VERSION 5.7 ;
  NOWIREEXTENSIONATPIN ON ;
  DIVIDERCHAR "/" ;
  BUSBITCHARS "[]" ;
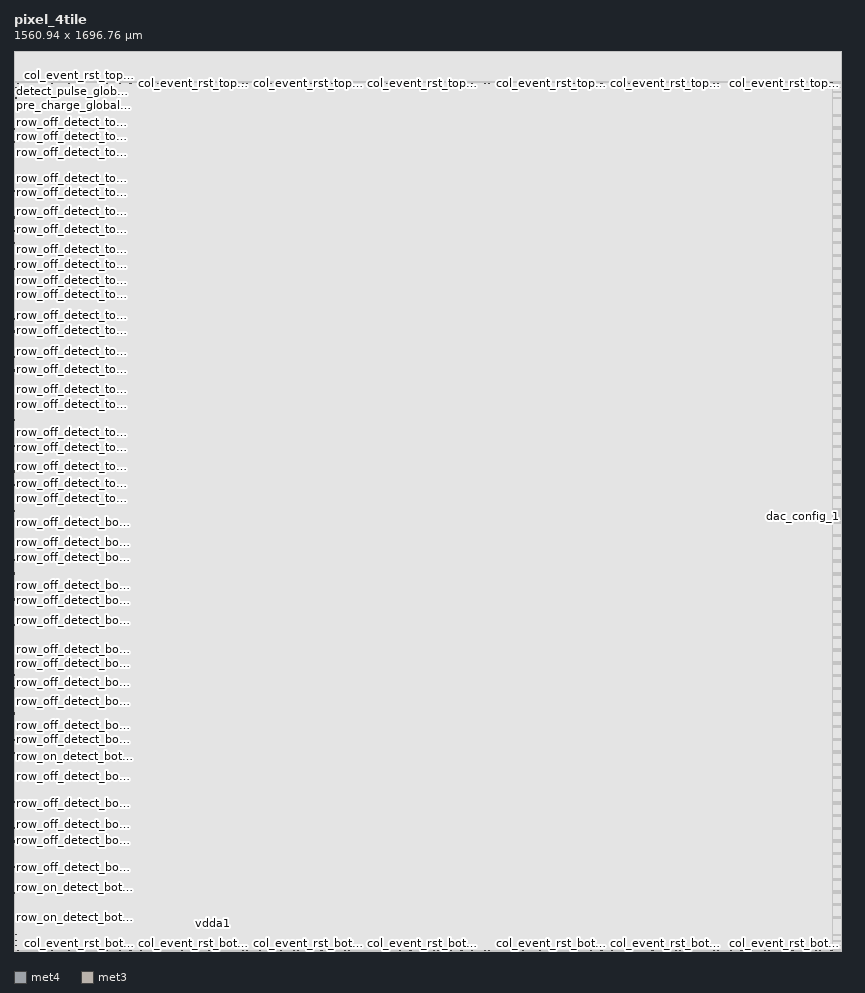
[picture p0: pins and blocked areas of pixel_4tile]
MACRO pixel_4tile
  CLASS BLOCK ;
  FOREIGN pixel_4tile ;
  ORIGIN 0.940 0.005 ;
  SIZE 1560.940 BY 1696.755 ;
  PIN vdda1
    ANTENNADIFFAREA 37975.105469 ;
    PORT
      LAYER met4 ;
        RECT 368.795 50.390 380.585 52.050 ;
    END
  END vdda1
  PIN array_col_top_right<8>
    ANTENNADIFFAREA 0.870000 ;
    PORT
      LAYER met3 ;
        RECT 1438.365 1635.345 1439.135 1635.645 ;
    END
  END array_col_top_right<8>
  PIN array_col_top_right<9>
    ANTENNADIFFAREA 0.870000 ;
    PORT
      LAYER met3 ;
        RECT 1422.245 1635.345 1423.015 1635.645 ;
    END
  END array_col_top_right<9>
  PIN array_col_top_right<12>
    ANTENNADIFFAREA 0.870000 ;
    PORT
      LAYER met3 ;
        RECT 1390.365 1635.345 1391.135 1635.645 ;
    END
  END array_col_top_right<12>
  PIN array_col_top_right<13>
    ANTENNADIFFAREA 0.870000 ;
    PORT
      LAYER met3 ;
        RECT 1374.245 1635.345 1375.015 1635.645 ;
    END
  END array_col_top_right<13>
  PIN array_col_top_right<16>
    ANTENNADIFFAREA 0.870000 ;
    PORT
      LAYER met3 ;
        RECT 1342.365 1635.345 1343.135 1635.645 ;
    END
  END array_col_top_right<16>
  PIN row_off_detect_bot<21>
    ANTENNAGATEAREA 8.064000 ;
    PORT
      LAYER met3 ;
        RECT 0.000 565.610 0.300 565.910 ;
    END
  END row_off_detect_bot<21>
  PIN array_col_top_right<26>
    ANTENNADIFFAREA 0.870000 ;
    PORT
      LAYER met3 ;
        RECT 1222.365 1635.345 1223.135 1635.645 ;
    END
  END array_col_top_right<26>
  PIN row_off_detect_bot<22>
    ANTENNAGATEAREA 8.064000 ;
    PORT
      LAYER met3 ;
        RECT 0.000 544.530 0.300 544.830 ;
    END
  END row_off_detect_bot<22>
  PIN detect_pulse_global_bot_left
    ANTENNAGATEAREA 147.199997 ;
    PORT
      LAYER met3 ;
        RECT 2.740 18.920 3.040 19.220 ;
    END
  END detect_pulse_global_bot_left
  PIN row_on_detect_bot<5>
    ANTENNAGATEAREA 16.128000 ;
    PORT
      LAYER met3 ;
        RECT 0.000 758.730 0.300 759.030 ;
    END
  END row_on_detect_bot<5>
  PIN row_off_detect_top<12>
    ANTENNAGATEAREA 8.064000 ;
    PORT
      LAYER met3 ;
        RECT 0.000 1432.610 0.300 1432.910 ;
    END
  END row_off_detect_top<12>
  PIN row_on_detect_top<13>
    ANTENNAGATEAREA 16.128000 ;
    PORT
      LAYER met3 ;
        RECT 0.000 1430.570 0.300 1430.870 ;
    END
  END row_on_detect_top<13>
  PIN detect_pulse_global_top_left
    ANTENNAGATEAREA 147.199997 ;
    PORT
      LAYER met3 ;
        RECT 2.740 1619.640 3.040 1619.940 ;
    END
  END detect_pulse_global_top_left
  PIN row_on_detect_top<1>
    ANTENNAGATEAREA 16.128000 ;
    PORT
      LAYER met3 ;
        RECT 0.000 1574.730 0.300 1575.030 ;
    END
  END row_on_detect_top<1>
  PIN col_event_rst_top_right<40>
    ANTENNAGATEAREA 4.032000 ;
    PORT
      LAYER met3 ;
        RECT 1057.595 1635.225 1057.895 1635.525 ;
    END
  END col_event_rst_top_right<40>
  PIN col_event_rst_top_right<39>
    ANTENNAGATEAREA 4.032000 ;
    PORT
      LAYER met3 ;
        RECT 1059.500 1635.225 1059.800 1635.525 ;
    END
  END col_event_rst_top_right<39>
  PIN col_event_rst_top_right<38>
    ANTENNAGATEAREA 4.032000 ;
    PORT
      LAYER met3 ;
        RECT 1081.595 1635.225 1081.895 1635.525 ;
    END
  END col_event_rst_top_right<38>
  PIN col_event_rst_top_right<37>
    ANTENNAGATEAREA 4.032000 ;
    PORT
      LAYER met3 ;
        RECT 1083.500 1635.225 1083.800 1635.525 ;
    END
  END col_event_rst_top_right<37>
  PIN col_event_rst_top_right<36>
    ANTENNAGATEAREA 4.032000 ;
    PORT
      LAYER met3 ;
        RECT 1105.595 1635.225 1105.895 1635.525 ;
    END
  END col_event_rst_top_right<36>
  PIN col_event_rst_top_right<35>
    ANTENNAGATEAREA 4.032000 ;
    PORT
      LAYER met3 ;
        RECT 1107.500 1635.225 1107.800 1635.525 ;
    END
  END col_event_rst_top_right<35>
  PIN col_event_rst_top_right<34>
    ANTENNAGATEAREA 4.032000 ;
    PORT
      LAYER met3 ;
        RECT 1129.595 1635.225 1129.895 1635.525 ;
    END
  END col_event_rst_top_right<34>
  PIN col_event_rst_top_right<33>
    ANTENNAGATEAREA 4.032000 ;
    PORT
      LAYER met3 ;
        RECT 1131.500 1635.225 1131.800 1635.525 ;
    END
  END col_event_rst_top_right<33>
  PIN col_event_rst_top_right<27>
    ANTENNAGATEAREA 4.032000 ;
    PORT
      LAYER met3 ;
        RECT 1203.500 1635.225 1203.800 1635.525 ;
    END
  END col_event_rst_top_right<27>
  PIN col_event_rst_top_right<32>
    ANTENNAGATEAREA 4.032000 ;
    PORT
      LAYER met3 ;
        RECT 1153.595 1635.225 1153.895 1635.525 ;
    END
  END col_event_rst_top_right<32>
  PIN col_event_rst_top_right<26>
    ANTENNAGATEAREA 4.032000 ;
    PORT
      LAYER met3 ;
        RECT 1225.595 1635.225 1225.895 1635.525 ;
    END
  END col_event_rst_top_right<26>
  PIN col_event_rst_top_right<25>
    ANTENNAGATEAREA 4.032000 ;
    PORT
      LAYER met3 ;
        RECT 1227.500 1635.225 1227.800 1635.525 ;
    END
  END col_event_rst_top_right<25>
  PIN col_event_rst_top_right<24>
    ANTENNAGATEAREA 4.032000 ;
    PORT
      LAYER met3 ;
        RECT 1249.595 1635.225 1249.895 1635.525 ;
    END
  END col_event_rst_top_right<24>
  PIN col_event_rst_top_right<23>
    ANTENNAGATEAREA 4.032000 ;
    PORT
      LAYER met3 ;
        RECT 1251.500 1635.225 1251.800 1635.525 ;
    END
  END col_event_rst_top_right<23>
  PIN col_event_rst_top_right<22>
    ANTENNAGATEAREA 4.032000 ;
    PORT
      LAYER met3 ;
        RECT 1273.595 1635.225 1273.895 1635.525 ;
    END
  END col_event_rst_top_right<22>
  PIN col_event_rst_top_right<21>
    ANTENNAGATEAREA 4.032000 ;
    PORT
      LAYER met3 ;
        RECT 1275.500 1635.225 1275.800 1635.525 ;
    END
  END col_event_rst_top_right<21>
  PIN col_event_rst_top_right<20>
    ANTENNAGATEAREA 4.032000 ;
    PORT
      LAYER met3 ;
        RECT 1297.595 1635.225 1297.895 1635.525 ;
    END
  END col_event_rst_top_right<20>
  PIN col_event_rst_top_right<19>
    ANTENNAGATEAREA 4.032000 ;
    PORT
      LAYER met3 ;
        RECT 1299.500 1635.225 1299.800 1635.525 ;
    END
  END col_event_rst_top_right<19>
  PIN col_event_rst_top_right<18>
    ANTENNAGATEAREA 4.032000 ;
    PORT
      LAYER met3 ;
        RECT 1321.595 1635.225 1321.895 1635.525 ;
    END
  END col_event_rst_top_right<18>
  PIN col_event_rst_top_right<17>
    ANTENNAGATEAREA 4.032000 ;
    PORT
      LAYER met3 ;
        RECT 1323.500 1635.225 1323.800 1635.525 ;
    END
  END col_event_rst_top_right<17>
  PIN col_event_rst_top_right<16>
    ANTENNAGATEAREA 4.032000 ;
    PORT
      LAYER met3 ;
        RECT 1345.595 1635.225 1345.895 1635.525 ;
    END
  END col_event_rst_top_right<16>
  PIN col_event_rst_top_right<15>
    ANTENNAGATEAREA 4.032000 ;
    PORT
      LAYER met3 ;
        RECT 1347.500 1635.225 1347.800 1635.525 ;
    END
  END col_event_rst_top_right<15>
  PIN col_event_rst_top_right<14>
    ANTENNAGATEAREA 4.032000 ;
    PORT
      LAYER met3 ;
        RECT 1369.595 1635.225 1369.895 1635.525 ;
    END
  END col_event_rst_top_right<14>
  PIN col_event_rst_top_right<13>
    ANTENNAGATEAREA 4.032000 ;
    PORT
      LAYER met3 ;
        RECT 1371.500 1635.225 1371.800 1635.525 ;
    END
  END col_event_rst_top_right<13>
  PIN col_event_rst_top_right<12>
    ANTENNAGATEAREA 4.032000 ;
    PORT
      LAYER met3 ;
        RECT 1393.595 1635.225 1393.895 1635.525 ;
    END
  END col_event_rst_top_right<12>
  PIN col_event_rst_top_right<11>
    ANTENNAGATEAREA 4.032000 ;
    PORT
      LAYER met3 ;
        RECT 1395.500 1635.225 1395.800 1635.525 ;
    END
  END col_event_rst_top_right<11>
  PIN col_event_rst_top_right<10>
    ANTENNAGATEAREA 4.032000 ;
    PORT
      LAYER met3 ;
        RECT 1417.595 1635.225 1417.895 1635.525 ;
    END
  END col_event_rst_top_right<10>
  PIN col_event_rst_top_right<9>
    ANTENNAGATEAREA 4.032000 ;
    PORT
      LAYER met3 ;
        RECT 1419.500 1635.225 1419.800 1635.525 ;
    END
  END col_event_rst_top_right<9>
  PIN col_event_rst_top_right<8>
    ANTENNAGATEAREA 4.032000 ;
    PORT
      LAYER met3 ;
        RECT 1441.595 1635.225 1441.895 1635.525 ;
    END
  END col_event_rst_top_right<8>
  PIN col_event_rst_top_right<7>
    ANTENNAGATEAREA 4.032000 ;
    PORT
      LAYER met3 ;
        RECT 1443.500 1635.225 1443.800 1635.525 ;
    END
  END col_event_rst_top_right<7>
  PIN col_event_rst_top_right<6>
    ANTENNAGATEAREA 4.032000 ;
    PORT
      LAYER met3 ;
        RECT 1465.595 1635.225 1465.895 1635.525 ;
    END
  END col_event_rst_top_right<6>
  PIN col_event_rst_top_right<5>
    ANTENNAGATEAREA 4.032000 ;
    PORT
      LAYER met3 ;
        RECT 1467.500 1635.225 1467.800 1635.525 ;
    END
  END col_event_rst_top_right<5>
  PIN col_event_rst_top_right<4>
    ANTENNAGATEAREA 4.032000 ;
    PORT
      LAYER met3 ;
        RECT 1489.595 1635.225 1489.895 1635.525 ;
    END
  END col_event_rst_top_right<4>
  PIN col_event_rst_top_right<3>
    ANTENNAGATEAREA 4.032000 ;
    PORT
      LAYER met3 ;
        RECT 1491.500 1635.225 1491.800 1635.525 ;
    END
  END col_event_rst_top_right<3>
  PIN col_event_rst_top_right<2>
    ANTENNAGATEAREA 4.032000 ;
    PORT
      LAYER met3 ;
        RECT 1513.595 1635.225 1513.895 1635.525 ;
    END
  END col_event_rst_top_right<2>
  PIN col_event_rst_top_right<1>
    ANTENNAGATEAREA 4.032000 ;
    PORT
      LAYER met3 ;
        RECT 1515.500 1635.225 1515.800 1635.525 ;
    END
  END col_event_rst_top_right<1>
  PIN col_event_rst_top_right<0>
    ANTENNAGATEAREA 4.032000 ;
    PORT
      LAYER met3 ;
        RECT 1537.595 1635.225 1537.895 1635.525 ;
    END
  END col_event_rst_top_right<0>
  PIN col_event_rst_bot_right<63>
    ANTENNAGATEAREA 4.032000 ;
    PORT
      LAYER met3 ;
        RECT 771.500 0.245 771.800 0.545 ;
    END
  END col_event_rst_bot_right<63>
  PIN col_event_rst_bot_right<62>
    ANTENNAGATEAREA 4.032000 ;
    PORT
      LAYER met3 ;
        RECT 793.595 1.580 793.895 1.880 ;
    END
  END col_event_rst_bot_right<62>
  PIN col_event_rst_bot_right<61>
    ANTENNAGATEAREA 4.032000 ;
    PORT
      LAYER met3 ;
        RECT 795.500 1.580 795.800 1.880 ;
    END
  END col_event_rst_bot_right<61>
  PIN col_event_rst_bot_right<60>
    ANTENNAGATEAREA 4.032000 ;
    PORT
      LAYER met3 ;
        RECT 817.595 1.580 817.895 1.880 ;
    END
  END col_event_rst_bot_right<60>
  PIN col_event_rst_bot_right<59>
    ANTENNAGATEAREA 4.032000 ;
    PORT
      LAYER met3 ;
        RECT 819.500 1.580 819.800 1.880 ;
    END
  END col_event_rst_bot_right<59>
  PIN col_event_rst_bot_right<58>
    ANTENNAGATEAREA 4.032000 ;
    PORT
      LAYER met3 ;
        RECT 841.595 1.580 841.895 1.880 ;
    END
  END col_event_rst_bot_right<58>
  PIN col_event_rst_bot_right<57>
    ANTENNAGATEAREA 4.032000 ;
    PORT
      LAYER met3 ;
        RECT 843.500 1.580 843.800 1.880 ;
    END
  END col_event_rst_bot_right<57>
  PIN col_event_rst_bot_right<56>
    ANTENNAGATEAREA 4.032000 ;
    PORT
      LAYER met3 ;
        RECT 865.595 1.580 865.895 1.880 ;
    END
  END col_event_rst_bot_right<56>
  PIN col_event_rst_bot_right<55>
    ANTENNAGATEAREA 4.032000 ;
    PORT
      LAYER met3 ;
        RECT 867.500 1.580 867.800 1.880 ;
    END
  END col_event_rst_bot_right<55>
  PIN col_event_rst_bot_right<54>
    ANTENNAGATEAREA 4.032000 ;
    PORT
      LAYER met3 ;
        RECT 889.595 1.580 889.895 1.880 ;
    END
  END col_event_rst_bot_right<54>
  PIN col_event_rst_bot_right<53>
    ANTENNAGATEAREA 4.032000 ;
    PORT
      LAYER met3 ;
        RECT 891.500 1.580 891.800 1.880 ;
    END
  END col_event_rst_bot_right<53>
  PIN col_event_rst_bot_right<52>
    ANTENNAGATEAREA 4.032000 ;
    PORT
      LAYER met3 ;
        RECT 913.595 1.580 913.895 1.880 ;
    END
  END col_event_rst_bot_right<52>
  PIN col_event_rst_bot_right<51>
    ANTENNAGATEAREA 4.032000 ;
    PORT
      LAYER met3 ;
        RECT 915.500 1.580 915.800 1.880 ;
    END
  END col_event_rst_bot_right<51>
  PIN col_event_rst_bot_right<50>
    ANTENNAGATEAREA 4.032000 ;
    PORT
      LAYER met3 ;
        RECT 937.595 1.580 937.895 1.880 ;
    END
  END col_event_rst_bot_right<50>
  PIN col_event_rst_bot_right<49>
    ANTENNAGATEAREA 4.032000 ;
    PORT
      LAYER met3 ;
        RECT 939.500 1.580 939.800 1.880 ;
    END
  END col_event_rst_bot_right<49>
  PIN col_event_rst_bot_right<48>
    ANTENNAGATEAREA 4.032000 ;
    PORT
      LAYER met3 ;
        RECT 961.595 1.580 961.895 1.880 ;
    END
  END col_event_rst_bot_right<48>
  PIN col_event_rst_bot_right<47>
    ANTENNAGATEAREA 4.032000 ;
    PORT
      LAYER met3 ;
        RECT 963.500 1.580 963.800 1.880 ;
    END
  END col_event_rst_bot_right<47>
  PIN col_event_rst_bot_right<46>
    ANTENNAGATEAREA 4.032000 ;
    PORT
      LAYER met3 ;
        RECT 985.595 1.580 985.895 1.880 ;
    END
  END col_event_rst_bot_right<46>
  PIN col_event_rst_bot_right<45>
    ANTENNAGATEAREA 4.032000 ;
    PORT
      LAYER met3 ;
        RECT 987.500 1.580 987.800 1.880 ;
    END
  END col_event_rst_bot_right<45>
  PIN col_event_rst_bot_right<44>
    ANTENNAGATEAREA 4.032000 ;
    PORT
      LAYER met3 ;
        RECT 1009.595 1.580 1009.895 1.880 ;
    END
  END col_event_rst_bot_right<44>
  PIN col_event_rst_bot_right<43>
    ANTENNAGATEAREA 4.032000 ;
    PORT
      LAYER met3 ;
        RECT 1011.500 1.580 1011.800 1.880 ;
    END
  END col_event_rst_bot_right<43>
  PIN col_event_rst_bot_right<42>
    ANTENNAGATEAREA 4.032000 ;
    PORT
      LAYER met3 ;
        RECT 1033.595 1.580 1033.895 1.880 ;
    END
  END col_event_rst_bot_right<42>
  PIN col_event_rst_bot_right<41>
    ANTENNAGATEAREA 4.032000 ;
    PORT
      LAYER met3 ;
        RECT 1035.500 1.580 1035.800 1.880 ;
    END
  END col_event_rst_bot_right<41>
  PIN col_event_rst_bot_right<40>
    ANTENNAGATEAREA 4.032000 ;
    PORT
      LAYER met3 ;
        RECT 1057.595 1.580 1057.895 1.880 ;
    END
  END col_event_rst_bot_right<40>
  PIN col_event_rst_bot_right<39>
    ANTENNAGATEAREA 4.032000 ;
    PORT
      LAYER met3 ;
        RECT 1059.500 1.580 1059.800 1.880 ;
    END
  END col_event_rst_bot_right<39>
  PIN col_event_rst_bot_right<38>
    ANTENNAGATEAREA 4.032000 ;
    PORT
      LAYER met3 ;
        RECT 1081.595 1.580 1081.895 1.880 ;
    END
  END col_event_rst_bot_right<38>
  PIN col_event_rst_bot_right<37>
    ANTENNAGATEAREA 4.032000 ;
    PORT
      LAYER met3 ;
        RECT 1083.500 1.580 1083.800 1.880 ;
    END
  END col_event_rst_bot_right<37>
  PIN col_event_rst_bot_right<36>
    ANTENNAGATEAREA 4.032000 ;
    PORT
      LAYER met3 ;
        RECT 1105.595 1.580 1105.895 1.880 ;
    END
  END col_event_rst_bot_right<36>
  PIN col_event_rst_bot_right<35>
    ANTENNAGATEAREA 4.032000 ;
    PORT
      LAYER met3 ;
        RECT 1107.500 1.580 1107.800 1.880 ;
    END
  END col_event_rst_bot_right<35>
  PIN col_event_rst_bot_right<34>
    ANTENNAGATEAREA 4.032000 ;
    PORT
      LAYER met3 ;
        RECT 1129.595 1.580 1129.895 1.880 ;
    END
  END col_event_rst_bot_right<34>
  PIN col_event_rst_bot_right<33>
    ANTENNAGATEAREA 4.032000 ;
    PORT
      LAYER met3 ;
        RECT 1131.500 1.580 1131.800 1.880 ;
    END
  END col_event_rst_bot_right<33>
  PIN col_event_rst_bot_right<32>
    ANTENNAGATEAREA 4.032000 ;
    PORT
      LAYER met3 ;
        RECT 1153.595 1.580 1153.895 1.880 ;
    END
  END col_event_rst_bot_right<32>
  PIN col_event_rst_bot_right<31>
    ANTENNAGATEAREA 4.032000 ;
    PORT
      LAYER met3 ;
        RECT 1155.500 1.580 1155.800 1.880 ;
    END
  END col_event_rst_bot_right<31>
  PIN col_event_rst_bot_right<30>
    ANTENNAGATEAREA 4.032000 ;
    PORT
      LAYER met3 ;
        RECT 1177.595 1.580 1177.895 1.880 ;
    END
  END col_event_rst_bot_right<30>
  PIN col_event_rst_bot_right<29>
    ANTENNAGATEAREA 4.032000 ;
    PORT
      LAYER met3 ;
        RECT 1179.500 1.580 1179.800 1.880 ;
    END
  END col_event_rst_bot_right<29>
  PIN col_event_rst_bot_right<28>
    ANTENNAGATEAREA 4.032000 ;
    PORT
      LAYER met3 ;
        RECT 1201.595 1.580 1201.895 1.880 ;
    END
  END col_event_rst_bot_right<28>
  PIN col_event_rst_bot_right<27>
    ANTENNAGATEAREA 4.032000 ;
    PORT
      LAYER met3 ;
        RECT 1203.500 1.580 1203.800 1.880 ;
    END
  END col_event_rst_bot_right<27>
  PIN col_event_rst_bot_right<26>
    ANTENNAGATEAREA 4.032000 ;
    PORT
      LAYER met3 ;
        RECT 1225.595 1.580 1225.895 1.880 ;
    END
  END col_event_rst_bot_right<26>
  PIN col_event_rst_bot_right<25>
    ANTENNAGATEAREA 4.032000 ;
    PORT
      LAYER met3 ;
        RECT 1227.500 1.580 1227.800 1.880 ;
    END
  END col_event_rst_bot_right<25>
  PIN col_event_rst_bot_right<24>
    ANTENNAGATEAREA 4.032000 ;
    PORT
      LAYER met3 ;
        RECT 1249.595 1.580 1249.895 1.880 ;
    END
  END col_event_rst_bot_right<24>
  PIN col_event_rst_bot_right<23>
    ANTENNAGATEAREA 4.032000 ;
    PORT
      LAYER met3 ;
        RECT 1251.500 1.580 1251.800 1.880 ;
    END
  END col_event_rst_bot_right<23>
  PIN col_event_rst_bot_right<22>
    ANTENNAGATEAREA 4.032000 ;
    PORT
      LAYER met3 ;
        RECT 1273.595 1.580 1273.895 1.880 ;
    END
  END col_event_rst_bot_right<22>
  PIN col_event_rst_bot_right<21>
    ANTENNAGATEAREA 4.032000 ;
    PORT
      LAYER met3 ;
        RECT 1275.500 1.580 1275.800 1.880 ;
    END
  END col_event_rst_bot_right<21>
  PIN col_event_rst_bot_right<20>
    ANTENNAGATEAREA 4.032000 ;
    PORT
      LAYER met3 ;
        RECT 1297.595 1.580 1297.895 1.880 ;
    END
  END col_event_rst_bot_right<20>
  PIN col_event_rst_bot_right<19>
    ANTENNAGATEAREA 4.032000 ;
    PORT
      LAYER met3 ;
        RECT 1299.500 1.580 1299.800 1.880 ;
    END
  END col_event_rst_bot_right<19>
  PIN col_event_rst_bot_right<18>
    ANTENNAGATEAREA 4.032000 ;
    PORT
      LAYER met3 ;
        RECT 1321.595 1.580 1321.895 1.880 ;
    END
  END col_event_rst_bot_right<18>
  PIN col_event_rst_bot_right<17>
    ANTENNAGATEAREA 4.032000 ;
    PORT
      LAYER met3 ;
        RECT 1323.500 1.580 1323.800 1.880 ;
    END
  END col_event_rst_bot_right<17>
  PIN col_event_rst_bot_right<16>
    ANTENNAGATEAREA 4.032000 ;
    PORT
      LAYER met3 ;
        RECT 1345.595 1.580 1345.895 1.880 ;
    END
  END col_event_rst_bot_right<16>
  PIN col_event_rst_bot_right<15>
    ANTENNAGATEAREA 4.032000 ;
    PORT
      LAYER met3 ;
        RECT 1347.500 1.580 1347.800 1.880 ;
    END
  END col_event_rst_bot_right<15>
  PIN col_event_rst_bot_right<14>
    ANTENNAGATEAREA 4.032000 ;
    PORT
      LAYER met3 ;
        RECT 1369.595 1.580 1369.895 1.880 ;
    END
  END col_event_rst_bot_right<14>
  PIN col_event_rst_bot_right<13>
    ANTENNAGATEAREA 4.032000 ;
    PORT
      LAYER met3 ;
        RECT 1371.500 1.580 1371.800 1.880 ;
    END
  END col_event_rst_bot_right<13>
  PIN col_event_rst_bot_right<12>
    ANTENNAGATEAREA 4.032000 ;
    PORT
      LAYER met3 ;
        RECT 1393.595 1.580 1393.895 1.880 ;
    END
  END col_event_rst_bot_right<12>
  PIN col_event_rst_bot_right<11>
    ANTENNAGATEAREA 4.032000 ;
    PORT
      LAYER met3 ;
        RECT 1395.500 1.580 1395.800 1.880 ;
    END
  END col_event_rst_bot_right<11>
  PIN col_event_rst_bot_right<10>
    ANTENNAGATEAREA 4.032000 ;
    PORT
      LAYER met3 ;
        RECT 1417.595 1.580 1417.895 1.880 ;
    END
  END col_event_rst_bot_right<10>
  PIN col_event_rst_bot_right<9>
    ANTENNAGATEAREA 4.032000 ;
    PORT
      LAYER met3 ;
        RECT 1419.500 1.580 1419.800 1.880 ;
    END
  END col_event_rst_bot_right<9>
  PIN col_event_rst_bot_right<8>
    ANTENNAGATEAREA 4.032000 ;
    PORT
      LAYER met3 ;
        RECT 1441.595 1.580 1441.895 1.880 ;
    END
  END col_event_rst_bot_right<8>
  PIN col_event_rst_bot_right<7>
    ANTENNAGATEAREA 4.032000 ;
    PORT
      LAYER met3 ;
        RECT 1443.500 1.580 1443.800 1.880 ;
    END
  END col_event_rst_bot_right<7>
  PIN col_event_rst_bot_right<6>
    ANTENNAGATEAREA 4.032000 ;
    PORT
      LAYER met3 ;
        RECT 1465.595 1.580 1465.895 1.880 ;
    END
  END col_event_rst_bot_right<6>
  PIN col_event_rst_bot_right<5>
    ANTENNAGATEAREA 4.032000 ;
    PORT
      LAYER met3 ;
        RECT 1467.500 1.580 1467.800 1.880 ;
    END
  END col_event_rst_bot_right<5>
  PIN col_event_rst_bot_right<4>
    ANTENNAGATEAREA 4.032000 ;
    PORT
      LAYER met3 ;
        RECT 1489.595 1.580 1489.895 1.880 ;
    END
  END col_event_rst_bot_right<4>
  PIN col_event_rst_bot_right<3>
    ANTENNAGATEAREA 4.032000 ;
    PORT
      LAYER met3 ;
        RECT 1491.500 1.580 1491.800 1.880 ;
    END
  END col_event_rst_bot_right<3>
  PIN col_event_rst_bot_right<2>
    ANTENNAGATEAREA 4.032000 ;
    PORT
      LAYER met3 ;
        RECT 1513.595 1.580 1513.895 1.880 ;
    END
  END col_event_rst_bot_right<2>
  PIN col_event_rst_bot_right<1>
    ANTENNAGATEAREA 4.032000 ;
    PORT
      LAYER met3 ;
        RECT 1515.500 1.580 1515.800 1.880 ;
    END
  END col_event_rst_bot_right<1>
  PIN col_event_rst_bot_right<0>
    ANTENNAGATEAREA 4.032000 ;
    PORT
      LAYER met3 ;
        RECT 1537.595 1.580 1537.895 1.880 ;
    END
  END col_event_rst_bot_right<0>
  PIN col_event_rst_bot_left<63>
    ANTENNAGATEAREA 4.032000 ;
    PORT
      LAYER met3 ;
        RECT 3.500 0.245 3.800 0.545 ;
    END
  END col_event_rst_bot_left<63>
  PIN col_event_rst_bot_left<62>
    ANTENNAGATEAREA 4.032000 ;
    PORT
      LAYER met3 ;
        RECT 25.595 1.580 25.895 1.880 ;
    END
  END col_event_rst_bot_left<62>
  PIN col_event_rst_bot_left<61>
    ANTENNAGATEAREA 4.032000 ;
    PORT
      LAYER met3 ;
        RECT 27.500 1.580 27.800 1.880 ;
    END
  END col_event_rst_bot_left<61>
  PIN col_event_rst_bot_left<60>
    ANTENNAGATEAREA 4.032000 ;
    PORT
      LAYER met3 ;
        RECT 49.595 1.580 49.895 1.880 ;
    END
  END col_event_rst_bot_left<60>
  PIN col_event_rst_bot_left<59>
    ANTENNAGATEAREA 4.032000 ;
    PORT
      LAYER met3 ;
        RECT 51.500 1.580 51.800 1.880 ;
    END
  END col_event_rst_bot_left<59>
  PIN col_event_rst_bot_left<58>
    ANTENNAGATEAREA 4.032000 ;
    PORT
      LAYER met3 ;
        RECT 73.595 1.580 73.895 1.880 ;
    END
  END col_event_rst_bot_left<58>
  PIN col_event_rst_bot_left<57>
    ANTENNAGATEAREA 4.032000 ;
    PORT
      LAYER met3 ;
        RECT 75.500 1.580 75.800 1.880 ;
    END
  END col_event_rst_bot_left<57>
  PIN col_event_rst_bot_left<56>
    ANTENNAGATEAREA 4.032000 ;
    PORT
      LAYER met3 ;
        RECT 97.595 1.580 97.895 1.880 ;
    END
  END col_event_rst_bot_left<56>
  PIN col_event_rst_bot_left<55>
    ANTENNAGATEAREA 4.032000 ;
    PORT
      LAYER met3 ;
        RECT 99.500 1.580 99.800 1.880 ;
    END
  END col_event_rst_bot_left<55>
  PIN col_event_rst_bot_left<54>
    ANTENNAGATEAREA 4.032000 ;
    PORT
      LAYER met3 ;
        RECT 121.595 1.580 121.895 1.880 ;
    END
  END col_event_rst_bot_left<54>
  PIN col_event_rst_bot_left<53>
    ANTENNAGATEAREA 4.032000 ;
    PORT
      LAYER met3 ;
        RECT 123.500 1.580 123.800 1.880 ;
    END
  END col_event_rst_bot_left<53>
  PIN col_event_rst_bot_left<52>
    ANTENNAGATEAREA 4.032000 ;
    PORT
      LAYER met3 ;
        RECT 145.595 1.580 145.895 1.880 ;
    END
  END col_event_rst_bot_left<52>
  PIN col_event_rst_bot_left<51>
    ANTENNAGATEAREA 4.032000 ;
    PORT
      LAYER met3 ;
        RECT 147.500 1.580 147.800 1.880 ;
    END
  END col_event_rst_bot_left<51>
  PIN col_event_rst_bot_left<50>
    ANTENNAGATEAREA 4.032000 ;
    PORT
      LAYER met3 ;
        RECT 169.595 1.580 169.895 1.880 ;
    END
  END col_event_rst_bot_left<50>
  PIN col_event_rst_bot_left<49>
    ANTENNAGATEAREA 4.032000 ;
    PORT
      LAYER met3 ;
        RECT 171.500 1.580 171.800 1.880 ;
    END
  END col_event_rst_bot_left<49>
  PIN col_event_rst_bot_left<48>
    ANTENNAGATEAREA 4.032000 ;
    PORT
      LAYER met3 ;
        RECT 193.595 1.580 193.895 1.880 ;
    END
  END col_event_rst_bot_left<48>
  PIN col_event_rst_bot_left<47>
    ANTENNAGATEAREA 4.032000 ;
    PORT
      LAYER met3 ;
        RECT 195.500 1.580 195.800 1.880 ;
    END
  END col_event_rst_bot_left<47>
  PIN col_event_rst_bot_left<46>
    ANTENNAGATEAREA 4.032000 ;
    PORT
      LAYER met3 ;
        RECT 217.595 1.580 217.895 1.880 ;
    END
  END col_event_rst_bot_left<46>
  PIN col_event_rst_bot_left<45>
    ANTENNAGATEAREA 4.032000 ;
    PORT
      LAYER met3 ;
        RECT 219.500 1.580 219.800 1.880 ;
    END
  END col_event_rst_bot_left<45>
  PIN col_event_rst_bot_left<44>
    ANTENNAGATEAREA 4.032000 ;
    PORT
      LAYER met3 ;
        RECT 241.595 1.580 241.895 1.880 ;
    END
  END col_event_rst_bot_left<44>
  PIN col_event_rst_bot_left<43>
    ANTENNAGATEAREA 4.032000 ;
    PORT
      LAYER met3 ;
        RECT 243.500 1.580 243.800 1.880 ;
    END
  END col_event_rst_bot_left<43>
  PIN col_event_rst_bot_left<42>
    ANTENNAGATEAREA 4.032000 ;
    PORT
      LAYER met3 ;
        RECT 265.595 1.580 265.895 1.880 ;
    END
  END col_event_rst_bot_left<42>
  PIN col_event_rst_bot_left<41>
    ANTENNAGATEAREA 4.032000 ;
    PORT
      LAYER met3 ;
        RECT 267.500 1.580 267.800 1.880 ;
    END
  END col_event_rst_bot_left<41>
  PIN col_event_rst_bot_left<40>
    ANTENNAGATEAREA 4.032000 ;
    PORT
      LAYER met3 ;
        RECT 289.595 1.580 289.895 1.880 ;
    END
  END col_event_rst_bot_left<40>
  PIN col_event_rst_bot_left<39>
    ANTENNAGATEAREA 4.032000 ;
    PORT
      LAYER met3 ;
        RECT 291.500 1.580 291.800 1.880 ;
    END
  END col_event_rst_bot_left<39>
  PIN col_event_rst_bot_left<38>
    ANTENNAGATEAREA 4.032000 ;
    PORT
      LAYER met3 ;
        RECT 313.595 1.580 313.895 1.880 ;
    END
  END col_event_rst_bot_left<38>
  PIN col_event_rst_bot_left<37>
    ANTENNAGATEAREA 4.032000 ;
    PORT
      LAYER met3 ;
        RECT 315.500 1.580 315.800 1.880 ;
    END
  END col_event_rst_bot_left<37>
  PIN col_event_rst_bot_left<36>
    ANTENNAGATEAREA 4.032000 ;
    PORT
      LAYER met3 ;
        RECT 337.595 1.580 337.895 1.880 ;
    END
  END col_event_rst_bot_left<36>
  PIN col_event_rst_bot_left<35>
    ANTENNAGATEAREA 4.032000 ;
    PORT
      LAYER met3 ;
        RECT 339.500 1.580 339.800 1.880 ;
    END
  END col_event_rst_bot_left<35>
  PIN col_event_rst_bot_left<34>
    ANTENNAGATEAREA 4.032000 ;
    PORT
      LAYER met3 ;
        RECT 361.595 1.580 361.895 1.880 ;
    END
  END col_event_rst_bot_left<34>
  PIN col_event_rst_bot_left<33>
    ANTENNAGATEAREA 4.032000 ;
    PORT
      LAYER met3 ;
        RECT 363.500 1.580 363.800 1.880 ;
    END
  END col_event_rst_bot_left<33>
  PIN col_event_rst_bot_left<32>
    ANTENNAGATEAREA 4.032000 ;
    PORT
      LAYER met3 ;
        RECT 385.595 1.580 385.895 1.880 ;
    END
  END col_event_rst_bot_left<32>
  PIN col_event_rst_bot_left<31>
    ANTENNAGATEAREA 4.032000 ;
    PORT
      LAYER met3 ;
        RECT 387.500 1.580 387.800 1.880 ;
    END
  END col_event_rst_bot_left<31>
  PIN col_event_rst_bot_left<30>
    ANTENNAGATEAREA 4.032000 ;
    PORT
      LAYER met3 ;
        RECT 409.595 1.580 409.895 1.880 ;
    END
  END col_event_rst_bot_left<30>
  PIN col_event_rst_bot_left<29>
    ANTENNAGATEAREA 4.032000 ;
    PORT
      LAYER met3 ;
        RECT 411.500 1.580 411.800 1.880 ;
    END
  END col_event_rst_bot_left<29>
  PIN col_event_rst_bot_left<28>
    ANTENNAGATEAREA 4.032000 ;
    PORT
      LAYER met3 ;
        RECT 433.595 1.580 433.895 1.880 ;
    END
  END col_event_rst_bot_left<28>
  PIN col_event_rst_bot_left<27>
    ANTENNAGATEAREA 4.032000 ;
    PORT
      LAYER met3 ;
        RECT 435.500 1.580 435.800 1.880 ;
    END
  END col_event_rst_bot_left<27>
  PIN col_event_rst_bot_left<26>
    ANTENNAGATEAREA 4.032000 ;
    PORT
      LAYER met3 ;
        RECT 457.595 1.580 457.895 1.880 ;
    END
  END col_event_rst_bot_left<26>
  PIN col_event_rst_bot_left<25>
    ANTENNAGATEAREA 4.032000 ;
    PORT
      LAYER met3 ;
        RECT 459.500 1.580 459.800 1.880 ;
    END
  END col_event_rst_bot_left<25>
  PIN col_event_rst_bot_left<24>
    ANTENNAGATEAREA 4.032000 ;
    PORT
      LAYER met3 ;
        RECT 481.595 1.580 481.895 1.880 ;
    END
  END col_event_rst_bot_left<24>
  PIN col_event_rst_bot_left<23>
    ANTENNAGATEAREA 4.032000 ;
    PORT
      LAYER met3 ;
        RECT 483.500 1.580 483.800 1.880 ;
    END
  END col_event_rst_bot_left<23>
  PIN col_event_rst_bot_left<22>
    ANTENNAGATEAREA 4.032000 ;
    PORT
      LAYER met3 ;
        RECT 505.595 1.580 505.895 1.880 ;
    END
  END col_event_rst_bot_left<22>
  PIN col_event_rst_bot_left<21>
    ANTENNAGATEAREA 4.032000 ;
    PORT
      LAYER met3 ;
        RECT 507.500 1.580 507.800 1.880 ;
    END
  END col_event_rst_bot_left<21>
  PIN col_event_rst_bot_left<20>
    ANTENNAGATEAREA 4.032000 ;
    PORT
      LAYER met3 ;
        RECT 529.595 1.580 529.895 1.880 ;
    END
  END col_event_rst_bot_left<20>
  PIN col_event_rst_bot_left<19>
    ANTENNAGATEAREA 4.032000 ;
    PORT
      LAYER met3 ;
        RECT 531.500 1.580 531.800 1.880 ;
    END
  END col_event_rst_bot_left<19>
  PIN col_event_rst_bot_left<18>
    ANTENNAGATEAREA 4.032000 ;
    PORT
      LAYER met3 ;
        RECT 553.595 1.580 553.895 1.880 ;
    END
  END col_event_rst_bot_left<18>
  PIN col_event_rst_bot_left<17>
    ANTENNAGATEAREA 4.032000 ;
    PORT
      LAYER met3 ;
        RECT 555.500 1.580 555.800 1.880 ;
    END
  END col_event_rst_bot_left<17>
  PIN col_event_rst_bot_left<16>
    ANTENNAGATEAREA 4.032000 ;
    PORT
      LAYER met3 ;
        RECT 577.595 1.580 577.895 1.880 ;
    END
  END col_event_rst_bot_left<16>
  PIN col_event_rst_bot_left<15>
    ANTENNAGATEAREA 4.032000 ;
    PORT
      LAYER met3 ;
        RECT 579.500 1.580 579.800 1.880 ;
    END
  END col_event_rst_bot_left<15>
  PIN col_event_rst_bot_left<14>
    ANTENNAGATEAREA 4.032000 ;
    PORT
      LAYER met3 ;
        RECT 601.595 1.580 601.895 1.880 ;
    END
  END col_event_rst_bot_left<14>
  PIN col_event_rst_bot_left<13>
    ANTENNAGATEAREA 4.032000 ;
    PORT
      LAYER met3 ;
        RECT 603.500 1.580 603.800 1.880 ;
    END
  END col_event_rst_bot_left<13>
  PIN col_event_rst_bot_left<12>
    ANTENNAGATEAREA 4.032000 ;
    PORT
      LAYER met3 ;
        RECT 625.595 1.580 625.895 1.880 ;
    END
  END col_event_rst_bot_left<12>
  PIN col_event_rst_bot_left<11>
    ANTENNAGATEAREA 4.032000 ;
    PORT
      LAYER met3 ;
        RECT 627.500 1.580 627.800 1.880 ;
    END
  END col_event_rst_bot_left<11>
  PIN col_event_rst_bot_left<10>
    ANTENNAGATEAREA 4.032000 ;
    PORT
      LAYER met3 ;
        RECT 649.595 1.580 649.895 1.880 ;
    END
  END col_event_rst_bot_left<10>
  PIN col_event_rst_bot_left<9>
    ANTENNAGATEAREA 4.032000 ;
    PORT
      LAYER met3 ;
        RECT 651.500 1.580 651.800 1.880 ;
    END
  END col_event_rst_bot_left<9>
  PIN col_event_rst_bot_left<8>
    ANTENNAGATEAREA 4.032000 ;
    PORT
      LAYER met3 ;
        RECT 673.595 1.580 673.895 1.880 ;
    END
  END col_event_rst_bot_left<8>
  PIN col_event_rst_bot_left<7>
    ANTENNAGATEAREA 4.032000 ;
    PORT
      LAYER met3 ;
        RECT 675.500 1.580 675.800 1.880 ;
    END
  END col_event_rst_bot_left<7>
  PIN col_event_rst_bot_left<6>
    ANTENNAGATEAREA 4.032000 ;
    PORT
      LAYER met3 ;
        RECT 697.595 1.580 697.895 1.880 ;
    END
  END col_event_rst_bot_left<6>
  PIN col_event_rst_bot_left<5>
    ANTENNAGATEAREA 4.032000 ;
    PORT
      LAYER met3 ;
        RECT 699.500 1.580 699.800 1.880 ;
    END
  END col_event_rst_bot_left<5>
  PIN col_event_rst_bot_left<4>
    ANTENNAGATEAREA 4.032000 ;
    PORT
      LAYER met3 ;
        RECT 721.595 1.580 721.895 1.880 ;
    END
  END col_event_rst_bot_left<4>
  PIN col_event_rst_bot_left<3>
    ANTENNAGATEAREA 4.032000 ;
    PORT
      LAYER met3 ;
        RECT 723.500 1.580 723.800 1.880 ;
    END
  END col_event_rst_bot_left<3>
  PIN col_event_rst_bot_left<2>
    ANTENNAGATEAREA 4.032000 ;
    PORT
      LAYER met3 ;
        RECT 745.595 1.580 745.895 1.880 ;
    END
  END col_event_rst_bot_left<2>
  PIN col_event_rst_bot_left<1>
    ANTENNAGATEAREA 4.032000 ;
    PORT
      LAYER met3 ;
        RECT 747.500 1.580 747.800 1.880 ;
    END
  END col_event_rst_bot_left<1>
  PIN col_event_rst_bot_left<0>
    ANTENNAGATEAREA 4.032000 ;
    PORT
      LAYER met3 ;
        RECT 769.595 1.580 769.895 1.880 ;
    END
  END col_event_rst_bot_left<0>
  PIN vssa1
    ANTENNADIFFAREA 30668.416016 ;
    PORT
      LAYER met3 ;
        RECT 1539.250 1637.930 1542.950 1638.230 ;
    END
    PORT
      LAYER met3 ;
        RECT 1539.250 0.295 1542.950 0.595 ;
    END
  END vssa1
  PIN array_col_top_left<9>
    ANTENNADIFFAREA 0.870000 ;
    PORT
      LAYER met3 ;
        RECT 654.245 1635.345 655.015 1635.645 ;
    END
  END array_col_top_left<9>
  PIN row_on_detect_top<35>
    ANTENNAGATEAREA 16.128000 ;
    PORT
      LAYER met3 ;
        RECT 0.000 1166.730 0.300 1167.030 ;
    END
  END row_on_detect_top<35>
  PIN row_off_detect_top<34>
    ANTENNAGATEAREA 8.064000 ;
    PORT
      LAYER met3 ;
        RECT 0.000 1168.770 0.300 1169.070 ;
    END
  END row_off_detect_top<34>
  PIN row_off_detect_top<14>
    ANTENNAGATEAREA 8.064000 ;
    PORT
      LAYER met3 ;
        RECT 0.000 1408.810 0.300 1409.110 ;
    END
  END row_off_detect_top<14>
  PIN array_col_top_left<13>
    ANTENNADIFFAREA 0.870000 ;
    PORT
      LAYER met3 ;
        RECT 606.245 1635.345 607.015 1635.645 ;
    END
  END array_col_top_left<13>
  PIN array_col_bot_left<60>
    ANTENNADIFFAREA 0.870000 ;
    PORT
      LAYER met3 ;
        RECT 46.365 1.460 47.135 1.760 ;
    END
  END array_col_bot_left<60>
  PIN array_col_bot_left<55>
    ANTENNADIFFAREA 0.870000 ;
    PORT
      LAYER met3 ;
        RECT 102.245 1.460 103.015 1.760 ;
    END
  END array_col_bot_left<55>
  PIN array_col_top_left<47>
    ANTENNADIFFAREA 0.870000 ;
    PORT
      LAYER met3 ;
        RECT 198.245 1635.345 199.015 1635.645 ;
    END
  END array_col_top_left<47>
  PIN array_col_bot_left<42>
    ANTENNADIFFAREA 0.870000 ;
    PORT
      LAYER met3 ;
        RECT 262.365 1.460 263.135 1.760 ;
    END
  END array_col_bot_left<42>
  PIN array_col_bot_left<41>
    ANTENNADIFFAREA 0.870000 ;
    PORT
      LAYER met3 ;
        RECT 270.245 1.460 271.015 1.760 ;
    END
  END array_col_bot_left<41>
  PIN array_col_top_right<25>
    ANTENNADIFFAREA 0.870000 ;
    PORT
      LAYER met3 ;
        RECT 1230.245 1635.345 1231.015 1635.645 ;
    END
  END array_col_top_right<25>
  PIN array_col_top_right<24>
    ANTENNADIFFAREA 0.870000 ;
    PORT
      LAYER met3 ;
        RECT 1246.365 1635.345 1247.135 1635.645 ;
    END
  END array_col_top_right<24>
  PIN array_col_bot_left<40>
    ANTENNADIFFAREA 0.870000 ;
    PORT
      LAYER met3 ;
        RECT 286.365 1.460 287.135 1.760 ;
    END
  END array_col_bot_left<40>
  PIN array_col_top_right<23>
    ANTENNADIFFAREA 0.870000 ;
    PORT
      LAYER met3 ;
        RECT 1254.245 1635.345 1255.015 1635.645 ;
    END
  END array_col_top_right<23>
  PIN array_col_top_right<22>
    ANTENNADIFFAREA 0.870000 ;
    PORT
      LAYER met3 ;
        RECT 1270.365 1635.345 1271.135 1635.645 ;
    END
  END array_col_top_right<22>
  PIN array_col_top_left<26>
    ANTENNADIFFAREA 0.870000 ;
    PORT
      LAYER met3 ;
        RECT 454.365 1635.345 455.135 1635.645 ;
    END
  END array_col_top_left<26>
  PIN array_col_top_right<21>
    ANTENNADIFFAREA 0.870000 ;
    PORT
      LAYER met3 ;
        RECT 1278.245 1635.345 1279.015 1635.645 ;
    END
  END array_col_top_right<21>
  PIN array_col_bot_left<20>
    ANTENNADIFFAREA 0.870000 ;
    PORT
      LAYER met3 ;
        RECT 526.365 1.460 527.135 1.760 ;
    END
  END array_col_bot_left<20>
  PIN array_col_bot_left<21>
    ANTENNADIFFAREA 0.870000 ;
    PORT
      LAYER met3 ;
        RECT 510.245 1.460 511.015 1.760 ;
    END
  END array_col_bot_left<21>
  PIN pre_charge_global_top_left
    ANTENNAGATEAREA 1024.000000 ;
    PORT
      LAYER met3 ;
        RECT 2.740 1608.050 3.040 1608.350 ;
    END
  END pre_charge_global_top_left
  PIN row_on_detect_bot<20>
    ANTENNAGATEAREA 16.128000 ;
    PORT
      LAYER met3 ;
        RECT 0.000 567.650 0.300 567.950 ;
    END
  END row_on_detect_bot<20>
  PIN row_on_detect_top<19>
    ANTENNAGATEAREA 16.128000 ;
    PORT
      LAYER met3 ;
        RECT 0.000 1358.490 0.300 1358.790 ;
    END
  END row_on_detect_top<19>
  PIN row_on_detect_top<18>
    ANTENNAGATEAREA 16.128000 ;
    PORT
      LAYER met3 ;
        RECT 0.000 1359.850 0.300 1360.150 ;
    END
  END row_on_detect_top<18>
  PIN col_event_rst_top_left<5>
    ANTENNAGATEAREA 4.032000 ;
    PORT
      LAYER met3 ;
        RECT 699.500 1635.225 699.800 1635.525 ;
    END
  END col_event_rst_top_left<5>
  PIN row_on_detect_bot<1>
    ANTENNAGATEAREA 16.128000 ;
    PORT
      LAYER met3 ;
        RECT 0.000 806.330 0.300 806.630 ;
    END
  END row_on_detect_bot<1>
  PIN row_on_detect_bot<0>
    ANTENNAGATEAREA 16.128000 ;
    PORT
      LAYER met3 ;
        RECT 0.000 807.690 0.300 807.990 ;
    END
  END row_on_detect_bot<0>
  PIN array_col_bot_left<22>
    ANTENNADIFFAREA 0.870000 ;
    PORT
      LAYER met3 ;
        RECT 502.365 1.460 503.135 1.760 ;
    END
  END array_col_bot_left<22>
  PIN array_col_bot_left<23>
    ANTENNADIFFAREA 0.870000 ;
    PORT
      LAYER met3 ;
        RECT 486.245 1.460 487.015 1.760 ;
    END
  END array_col_bot_left<23>
  PIN array_col_top_left<49>
    ANTENNADIFFAREA 0.870000 ;
    PORT
      LAYER met3 ;
        RECT 174.245 1635.345 175.015 1635.645 ;
    END
  END array_col_top_left<49>
  PIN array_col_top_right<20>
    ANTENNADIFFAREA 0.870000 ;
    PORT
      LAYER met3 ;
        RECT 1294.365 1635.345 1295.135 1635.645 ;
    END
  END array_col_top_right<20>
  PIN array_col_bot_left<16>
    ANTENNADIFFAREA 0.870000 ;
    PORT
      LAYER met3 ;
        RECT 574.365 1.460 575.135 1.760 ;
    END
  END array_col_bot_left<16>
  PIN row_on_detect_top<8>
    ANTENNAGATEAREA 16.128000 ;
    PORT
      LAYER met3 ;
        RECT 0.000 1479.530 0.300 1479.830 ;
    END
  END row_on_detect_top<8>
  PIN array_col_bot_left<45>
    ANTENNADIFFAREA 0.870000 ;
    PORT
      LAYER met3 ;
        RECT 222.245 1.460 223.015 1.760 ;
    END
  END array_col_bot_left<45>
  PIN array_col_top_left<17>
    ANTENNADIFFAREA 0.870000 ;
    PORT
      LAYER met3 ;
        RECT 558.245 1635.345 559.015 1635.645 ;
    END
  END array_col_top_left<17>
  PIN array_col_bot_right<3>
    ANTENNADIFFAREA 0.870000 ;
    PORT
      LAYER met3 ;
        RECT 1494.245 1.460 1495.015 1.760 ;
    END
  END array_col_bot_right<3>
  PIN array_col_bot_right<15>
    ANTENNADIFFAREA 0.870000 ;
    PORT
      LAYER met3 ;
        RECT 1350.245 1.460 1351.015 1.760 ;
    END
  END array_col_bot_right<15>
  PIN row_off_detect_bot<36>
    ANTENNAGATEAREA 8.064000 ;
    PORT
      LAYER met3 ;
        RECT 0.000 376.570 0.300 376.870 ;
    END
  END row_off_detect_bot<36>
  PIN row_on_detect_bot<26>
    ANTENNAGATEAREA 16.128000 ;
    PORT
      LAYER met3 ;
        RECT 0.000 495.570 0.300 495.870 ;
    END
  END row_on_detect_bot<26>
  PIN array_col_top_right<19>
    ANTENNADIFFAREA 0.870000 ;
    PORT
      LAYER met3 ;
        RECT 1302.245 1635.345 1303.015 1635.645 ;
    END
  END array_col_top_right<19>
  PIN array_col_bot_right<9>
    ANTENNADIFFAREA 0.870000 ;
    PORT
      LAYER met3 ;
        RECT 1422.245 1.460 1423.015 1.760 ;
    END
  END array_col_bot_right<9>
  PIN array_col_top_right<18>
    ANTENNADIFFAREA 0.870000 ;
    PORT
      LAYER met3 ;
        RECT 1318.365 1635.345 1319.135 1635.645 ;
    END
  END array_col_top_right<18>
  PIN array_col_top_right<15>
    ANTENNADIFFAREA 0.870000 ;
    PORT
      LAYER met3 ;
        RECT 1350.245 1635.345 1351.015 1635.645 ;
    END
  END array_col_top_right<15>
  PIN array_col_top_right<10>
    ANTENNADIFFAREA 0.870000 ;
    PORT
      LAYER met3 ;
        RECT 1414.365 1635.345 1415.135 1635.645 ;
    END
  END array_col_top_right<10>
  PIN array_col_top_right<7>
    ANTENNADIFFAREA 0.870000 ;
    PORT
      LAYER met3 ;
        RECT 1446.245 1635.345 1447.015 1635.645 ;
    END
  END array_col_top_right<7>
  PIN col_event_rst_top_left<38>
    ANTENNAGATEAREA 4.032000 ;
    PORT
      LAYER met3 ;
        RECT 313.595 1635.225 313.895 1635.525 ;
    END
  END col_event_rst_top_left<38>
  PIN col_event_rst_top_left<32>
    ANTENNAGATEAREA 4.032000 ;
    PORT
      LAYER met3 ;
        RECT 385.595 1635.225 385.895 1635.525 ;
    END
  END col_event_rst_top_left<32>
  PIN col_event_rst_top_left<21>
    ANTENNAGATEAREA 4.032000 ;
    PORT
      LAYER met3 ;
        RECT 507.500 1635.225 507.800 1635.525 ;
    END
  END col_event_rst_top_left<21>
  PIN col_event_rst_top_left<19>
    ANTENNAGATEAREA 4.032000 ;
    PORT
      LAYER met3 ;
        RECT 531.500 1635.225 531.800 1635.525 ;
    END
  END col_event_rst_top_left<19>
  PIN array_col_bot_right<16>
    ANTENNADIFFAREA 0.870000 ;
    PORT
      LAYER met3 ;
        RECT 1342.365 1.460 1343.135 1.760 ;
    END
  END array_col_bot_right<16>
  PIN array_col_bot_left<31>
    ANTENNADIFFAREA 0.870000 ;
    PORT
      LAYER met3 ;
        RECT 390.245 1.460 391.015 1.760 ;
    END
  END array_col_bot_left<31>
  PIN array_col_bot_left<7>
    ANTENNADIFFAREA 0.870000 ;
    PORT
      LAYER met3 ;
        RECT 678.245 1.460 679.015 1.760 ;
    END
  END array_col_bot_left<7>
  PIN row_off_detect_top<29>
    ANTENNAGATEAREA 8.064000 ;
    PORT
      LAYER met3 ;
        RECT 0.000 1237.450 0.300 1237.750 ;
    END
  END row_off_detect_top<29>
  PIN row_on_detect_top<28>
    ANTENNAGATEAREA 16.128000 ;
    PORT
      LAYER met3 ;
        RECT 0.000 1239.490 0.300 1239.790 ;
    END
  END row_on_detect_top<28>
  PIN col_event_rst_top_left<9>
    ANTENNAGATEAREA 4.032000 ;
    PORT
      LAYER met3 ;
        RECT 651.500 1635.225 651.800 1635.525 ;
    END
  END col_event_rst_top_left<9>
  PIN col_event_rst_top_left<60>
    ANTENNAGATEAREA 4.032000 ;
    PORT
      LAYER met3 ;
        RECT 49.595 1635.225 49.895 1635.525 ;
    END
  END col_event_rst_top_left<60>
  PIN col_event_rst_top_left<20>
    ANTENNAGATEAREA 4.032000 ;
    PORT
      LAYER met3 ;
        RECT 529.595 1635.225 529.895 1635.525 ;
    END
  END col_event_rst_top_left<20>
  PIN col_event_rst_top_left<12>
    ANTENNAGATEAREA 4.032000 ;
    PORT
      LAYER met3 ;
        RECT 625.595 1635.225 625.895 1635.525 ;
    END
  END col_event_rst_top_left<12>
  PIN array_col_bot_right<26>
    ANTENNADIFFAREA 0.870000 ;
    PORT
      LAYER met3 ;
        RECT 1222.365 1.460 1223.135 1.760 ;
    END
  END array_col_bot_right<26>
  PIN array_col_bot_right<23>
    ANTENNADIFFAREA 0.870000 ;
    PORT
      LAYER met3 ;
        RECT 1254.245 1.460 1255.015 1.760 ;
    END
  END array_col_bot_right<23>
  PIN row_off_detect_top<53>
    ANTENNAGATEAREA 8.064000 ;
    PORT
      LAYER met3 ;
        RECT 0.000 949.130 0.300 949.430 ;
    END
  END row_off_detect_top<53>
  PIN row_off_detect_bot<50>
    ANTENNAGATEAREA 8.064000 ;
    PORT
      LAYER met3 ;
        RECT 0.000 208.610 0.300 208.910 ;
    END
  END row_off_detect_bot<50>
  PIN row_off_detect_bot<52>
    ANTENNAGATEAREA 8.064000 ;
    PORT
      LAYER met3 ;
        RECT 0.000 184.810 0.300 185.110 ;
    END
  END row_off_detect_bot<52>
  PIN row_on_detect_top<9>
    ANTENNAGATEAREA 16.128000 ;
    PORT
      LAYER met3 ;
        RECT 0.000 1478.850 0.300 1479.150 ;
    END
  END row_on_detect_top<9>
  PIN row_off_detect_top<8>
    ANTENNAGATEAREA 8.064000 ;
    PORT
      LAYER met3 ;
        RECT 0.000 1480.890 0.300 1481.190 ;
    END
  END row_off_detect_top<8>
  PIN row_off_detect_top<46>
    ANTENNAGATEAREA 8.064000 ;
    PORT
      LAYER met3 ;
        RECT 0.000 1024.610 0.300 1024.910 ;
    END
  END row_off_detect_top<46>
  PIN array_col_top_left<34>
    ANTENNADIFFAREA 0.870000 ;
    PORT
      LAYER met3 ;
        RECT 358.365 1635.345 359.135 1635.645 ;
    END
  END array_col_top_left<34>
  PIN col_event_rst_top_left<6>
    ANTENNAGATEAREA 4.032000 ;
    PORT
      LAYER met3 ;
        RECT 697.595 1635.225 697.895 1635.525 ;
    END
  END col_event_rst_top_left<6>
  PIN array_col_bot_left<43>
    ANTENNADIFFAREA 0.870000 ;
    PORT
      LAYER met3 ;
        RECT 246.245 1.460 247.015 1.760 ;
    END
  END array_col_bot_left<43>
  PIN col_event_rst_top_left<61>
    ANTENNAGATEAREA 4.032000 ;
    PORT
      LAYER met3 ;
        RECT 27.500 1635.225 27.800 1635.525 ;
    END
  END col_event_rst_top_left<61>
  PIN col_event_rst_top_left<48>
    ANTENNAGATEAREA 4.032000 ;
    PORT
      LAYER met3 ;
        RECT 193.595 1635.225 193.895 1635.525 ;
    END
  END col_event_rst_top_left<48>
  PIN col_event_rst_top_left<36>
    ANTENNAGATEAREA 4.032000 ;
    PORT
      LAYER met3 ;
        RECT 337.595 1635.225 337.895 1635.525 ;
    END
  END col_event_rst_top_left<36>
  PIN array_col_top_left<50>
    ANTENNADIFFAREA 0.870000 ;
    PORT
      LAYER met3 ;
        RECT 166.365 1635.345 167.135 1635.645 ;
    END
  END array_col_top_left<50>
  PIN row_off_detect_bot<40>
    ANTENNAGATEAREA 8.064000 ;
    PORT
      LAYER met3 ;
        RECT 0.000 328.970 0.300 329.270 ;
    END
  END row_off_detect_bot<40>
  PIN array_col_top_left<12>
    ANTENNADIFFAREA 0.870000 ;
    PORT
      LAYER met3 ;
        RECT 622.365 1635.345 623.135 1635.645 ;
    END
  END array_col_top_left<12>
  PIN row_on_detect_bot<7>
    ANTENNAGATEAREA 16.128000 ;
    PORT
      LAYER met3 ;
        RECT 0.000 734.930 0.300 735.230 ;
    END
  END row_on_detect_bot<7>
  PIN row_on_detect_bot<13>
    ANTENNAGATEAREA 16.128000 ;
    PORT
      LAYER met3 ;
        RECT 0.000 662.850 0.300 663.150 ;
    END
  END row_on_detect_bot<13>
  PIN row_off_detect_top<7>
    ANTENNAGATEAREA 8.064000 ;
    PORT
      LAYER met3 ;
        RECT 0.000 1501.290 0.300 1501.590 ;
    END
  END row_off_detect_top<7>
  PIN array_col_top_right<31>
    ANTENNADIFFAREA 0.870000 ;
    PORT
      LAYER met3 ;
        RECT 1158.245 1635.345 1159.015 1635.645 ;
    END
  END array_col_top_right<31>
  PIN array_col_bot_right<11>
    ANTENNADIFFAREA 0.870000 ;
    PORT
      LAYER met3 ;
        RECT 1398.245 1.460 1399.015 1.760 ;
    END
  END array_col_bot_right<11>
  PIN array_col_top_left<51>
    ANTENNADIFFAREA 0.870000 ;
    PORT
      LAYER met3 ;
        RECT 150.245 1635.345 151.015 1635.645 ;
    END
  END array_col_top_left<51>
  PIN col_event_rst_top_left<24>
    ANTENNAGATEAREA 4.032000 ;
    PORT
      LAYER met3 ;
        RECT 481.595 1635.225 481.895 1635.525 ;
    END
  END col_event_rst_top_left<24>
  PIN array_col_top_left<25>
    ANTENNADIFFAREA 0.870000 ;
    PORT
      LAYER met3 ;
        RECT 462.245 1635.345 463.015 1635.645 ;
    END
  END array_col_top_left<25>
  PIN row_on_detect_top<4>
    ANTENNAGATEAREA 16.128000 ;
    PORT
      LAYER met3 ;
        RECT 0.000 1527.810 0.300 1528.110 ;
    END
  END row_on_detect_top<4>
  PIN array_col_top_left<8>
    ANTENNADIFFAREA 0.870000 ;
    PORT
      LAYER met3 ;
        RECT 670.365 1635.345 671.135 1635.645 ;
    END
  END array_col_top_left<8>
  PIN array_col_top_left<53>
    ANTENNADIFFAREA 0.870000 ;
    PORT
      LAYER met3 ;
        RECT 126.245 1635.345 127.015 1635.645 ;
    END
  END array_col_top_left<53>
  PIN array_col_top_left<38>
    ANTENNADIFFAREA 0.870000 ;
    PORT
      LAYER met3 ;
        RECT 310.365 1635.345 311.135 1635.645 ;
    END
  END array_col_top_left<38>
  PIN array_col_top_left<54>
    ANTENNADIFFAREA 0.870000 ;
    PORT
      LAYER met3 ;
        RECT 118.365 1635.345 119.135 1635.645 ;
    END
  END array_col_top_left<54>
  PIN row_on_detect_top<25>
    ANTENNAGATEAREA 16.128000 ;
    PORT
      LAYER met3 ;
        RECT 0.000 1286.410 0.300 1286.710 ;
    END
  END row_on_detect_top<25>
  PIN row_on_detect_top<24>
    ANTENNAGATEAREA 16.128000 ;
    PORT
      LAYER met3 ;
        RECT 0.000 1287.770 0.300 1288.070 ;
    END
  END row_on_detect_top<24>
  PIN row_on_detect_top<36>
    ANTENNAGATEAREA 16.128000 ;
    PORT
      LAYER met3 ;
        RECT 0.000 1143.610 0.300 1143.910 ;
    END
  END row_on_detect_top<36>
  PIN array_col_top_left<40>
    ANTENNADIFFAREA 0.870000 ;
    PORT
      LAYER met3 ;
        RECT 286.365 1635.345 287.135 1635.645 ;
    END
  END array_col_top_left<40>
  PIN row_off_detect_top<40>
    ANTENNAGATEAREA 8.064000 ;
    PORT
      LAYER met3 ;
        RECT 0.000 1096.690 0.300 1096.990 ;
    END
  END row_off_detect_top<40>
  PIN array_col_top_left<41>
    ANTENNADIFFAREA 0.870000 ;
    PORT
      LAYER met3 ;
        RECT 270.245 1635.345 271.015 1635.645 ;
    END
  END array_col_top_left<41>
  PIN array_col_top_left<57>
    ANTENNADIFFAREA 0.870000 ;
    PORT
      LAYER met3 ;
        RECT 78.245 1635.345 79.015 1635.645 ;
    END
  END array_col_top_left<57>
  PIN array_col_top_left<58>
    ANTENNADIFFAREA 0.870000 ;
    PORT
      LAYER met3 ;
        RECT 70.365 1635.345 71.135 1635.645 ;
    END
  END array_col_top_left<58>
  PIN array_col_top_left<27>
    ANTENNADIFFAREA 0.870000 ;
    PORT
      LAYER met3 ;
        RECT 438.245 1635.345 439.015 1635.645 ;
    END
  END array_col_top_left<27>
  PIN array_col_top_left<60>
    ANTENNADIFFAREA 0.870000 ;
    PORT
      LAYER met3 ;
        RECT 46.365 1635.345 47.135 1635.645 ;
    END
  END array_col_top_left<60>
  PIN array_col_top_left<45>
    ANTENNADIFFAREA 0.870000 ;
    PORT
      LAYER met3 ;
        RECT 222.245 1635.345 223.015 1635.645 ;
    END
  END array_col_top_left<45>
  PIN array_col_top_left<61>
    ANTENNADIFFAREA 0.870000 ;
    PORT
      LAYER met3 ;
        RECT 30.245 1635.345 31.015 1635.645 ;
    END
  END array_col_top_left<61>
  PIN row_on_detect_top<11>
    ANTENNAGATEAREA 16.128000 ;
    PORT
      LAYER met3 ;
        RECT 0.000 1454.370 0.300 1454.670 ;
    END
  END row_on_detect_top<11>
  PIN array_col_bot_left<1>
    ANTENNADIFFAREA 0.870000 ;
    PORT
      LAYER met3 ;
        RECT 750.245 1.460 751.015 1.760 ;
    END
  END array_col_bot_left<1>
  PIN dac_config_0
    ANTENNAGATEAREA 36576.000000 ;
    PORT
      LAYER met3 ;
        RECT 1559.700 816.530 1560.000 816.830 ;
    END
  END dac_config_0
  PIN row_on_detect_top<14>
    ANTENNAGATEAREA 16.128000 ;
    PORT
      LAYER met3 ;
        RECT 0.000 1407.450 0.300 1407.750 ;
    END
  END row_on_detect_top<14>
  PIN array_col_top_left<32>
    ANTENNADIFFAREA 0.870000 ;
    PORT
      LAYER met3 ;
        RECT 382.365 1635.345 383.135 1635.645 ;
    END
  END array_col_top_left<32>
  PIN array_col_bot_right<14>
    ANTENNADIFFAREA 0.870000 ;
    PORT
      LAYER met3 ;
        RECT 1366.365 1.460 1367.135 1.760 ;
    END
  END array_col_bot_right<14>
  PIN row_on_detect_top<38>
    ANTENNAGATEAREA 16.128000 ;
    PORT
      LAYER met3 ;
        RECT 0.000 1119.810 0.300 1120.110 ;
    END
  END row_on_detect_top<38>
  PIN row_off_detect_top<38>
    ANTENNAGATEAREA 8.064000 ;
    PORT
      LAYER met3 ;
        RECT 0.000 1120.490 0.300 1120.790 ;
    END
  END row_off_detect_top<38>
  PIN row_off_detect_top<43>
    ANTENNAGATEAREA 8.064000 ;
    PORT
      LAYER met3 ;
        RECT 0.000 1069.490 0.300 1069.790 ;
    END
  END row_off_detect_top<43>
  PIN row_on_detect_top<41>
    ANTENNAGATEAREA 16.128000 ;
    PORT
      LAYER met3 ;
        RECT 0.000 1094.650 0.300 1094.950 ;
    END
  END row_on_detect_top<41>
  PIN row_on_detect_top<30>
    ANTENNAGATEAREA 16.128000 ;
    PORT
      LAYER met3 ;
        RECT 0.000 1215.690 0.300 1215.990 ;
    END
  END row_on_detect_top<30>
  PIN row_off_detect_top<30>
    ANTENNAGATEAREA 8.064000 ;
    PORT
      LAYER met3 ;
        RECT 0.000 1216.370 0.300 1216.670 ;
    END
  END row_off_detect_top<30>
  PIN dac_config_2
    ANTENNAGATEAREA 36864.000000 ;
    PORT
      LAYER met3 ;
        RECT 1559.700 826.730 1560.000 827.030 ;
    END
  END dac_config_2
  PIN array_col_top_left<48>
    ANTENNADIFFAREA 0.870000 ;
    PORT
      LAYER met3 ;
        RECT 190.365 1635.345 191.135 1635.645 ;
    END
  END array_col_top_left<48>
  PIN dac_config_6
    ANTENNAGATEAREA 38.399998 ;
    PORT
      LAYER met3 ;
        RECT 1559.700 814.490 1560.000 814.790 ;
    END
  END dac_config_6
  PIN array_col_top_left<19>
    ANTENNADIFFAREA 0.870000 ;
    PORT
      LAYER met3 ;
        RECT 534.245 1635.345 535.015 1635.645 ;
    END
  END array_col_top_left<19>
  PIN row_on_detect_bot<21>
    ANTENNAGATEAREA 16.128000 ;
    PORT
      LAYER met3 ;
        RECT 0.000 566.290 0.300 566.590 ;
    END
  END row_on_detect_bot<21>
  PIN array_col_top_right<29>
    ANTENNADIFFAREA 0.870000 ;
    PORT
      LAYER met3 ;
        RECT 1182.245 1635.345 1183.015 1635.645 ;
    END
  END array_col_top_right<29>
  PIN dac_config_3
    ANTENNAGATEAREA 1228.799927 ;
    PORT
      LAYER met3 ;
        RECT 1559.700 822.650 1560.000 822.950 ;
    END
  END dac_config_3
  PIN row_off_detect_top<15>
    ANTENNAGATEAREA 8.064000 ;
    PORT
      LAYER met3 ;
        RECT 0.000 1405.410 0.300 1405.710 ;
    END
  END row_off_detect_top<15>
  PIN row_on_detect_top<15>
    ANTENNAGATEAREA 16.128000 ;
    PORT
      LAYER met3 ;
        RECT 0.000 1406.090 0.300 1406.390 ;
    END
  END row_on_detect_top<15>
  PIN row_off_detect_top<9>
    ANTENNAGATEAREA 8.064000 ;
    PORT
      LAYER met3 ;
        RECT 0.000 1477.490 0.300 1477.790 ;
    END
  END row_off_detect_top<9>
  PIN col_event_rst_top_right<62>
    ANTENNAGATEAREA 4.032000 ;
    PORT
      LAYER met3 ;
        RECT 793.595 1635.225 793.895 1635.525 ;
    END
  END col_event_rst_top_right<62>
  PIN col_event_rst_top_left<1>
    ANTENNAGATEAREA 4.032000 ;
    PORT
      LAYER met3 ;
        RECT 747.500 1635.225 747.800 1635.525 ;
    END
  END col_event_rst_top_left<1>
  PIN col_event_rst_top_left<2>
    ANTENNAGATEAREA 4.032000 ;
    PORT
      LAYER met3 ;
        RECT 745.595 1635.225 745.895 1635.525 ;
    END
  END col_event_rst_top_left<2>
  PIN array_col_bot_right<17>
    ANTENNADIFFAREA 0.870000 ;
    PORT
      LAYER met3 ;
        RECT 1326.245 1.460 1327.015 1.760 ;
    END
  END array_col_bot_right<17>
  PIN row_on_detect_bot<34>
    ANTENNAGATEAREA 16.128000 ;
    PORT
      LAYER met3 ;
        RECT 0.000 399.690 0.300 399.990 ;
    END
  END row_on_detect_bot<34>
  PIN row_on_detect_bot<35>
    ANTENNAGATEAREA 16.128000 ;
    PORT
      LAYER met3 ;
        RECT 0.000 398.330 0.300 398.630 ;
    END
  END row_on_detect_bot<35>
  PIN row_off_detect_bot<35>
    ANTENNAGATEAREA 8.064000 ;
    PORT
      LAYER met3 ;
        RECT 0.000 397.650 0.300 397.950 ;
    END
  END row_off_detect_bot<35>
  PIN row_off_detect_bot<25>
    ANTENNAGATEAREA 8.064000 ;
    PORT
      LAYER met3 ;
        RECT 0.000 517.330 0.300 517.630 ;
    END
  END row_off_detect_bot<25>
  PIN row_off_detect_top<55>
    ANTENNAGATEAREA 8.064000 ;
    PORT
      LAYER met3 ;
        RECT 0.000 925.330 0.300 925.630 ;
    END
  END row_off_detect_top<55>
  PIN row_on_detect_top<53>
    ANTENNAGATEAREA 16.128000 ;
    PORT
      LAYER met3 ;
        RECT 0.000 950.490 0.300 950.790 ;
    END
  END row_on_detect_top<53>
  PIN array_col_top_right<14>
    ANTENNADIFFAREA 0.870000 ;
    PORT
      LAYER met3 ;
        RECT 1366.365 1635.345 1367.135 1635.645 ;
    END
  END array_col_top_right<14>
  PIN array_col_top_right<11>
    ANTENNADIFFAREA 0.870000 ;
    PORT
      LAYER met3 ;
        RECT 1398.245 1635.345 1399.015 1635.645 ;
    END
  END array_col_top_right<11>
  PIN array_col_top_right<6>
    ANTENNADIFFAREA 0.870000 ;
    PORT
      LAYER met3 ;
        RECT 1462.365 1635.345 1463.135 1635.645 ;
    END
  END array_col_top_right<6>
  PIN col_event_rst_top_left<41>
    ANTENNAGATEAREA 4.032000 ;
    PORT
      LAYER met3 ;
        RECT 267.500 1635.225 267.800 1635.525 ;
    END
  END col_event_rst_top_left<41>
  PIN col_event_rst_top_left<34>
    ANTENNAGATEAREA 4.032000 ;
    PORT
      LAYER met3 ;
        RECT 361.595 1635.225 361.895 1635.525 ;
    END
  END col_event_rst_top_left<34>
  PIN col_event_rst_top_left<28>
    ANTENNAGATEAREA 4.032000 ;
    PORT
      LAYER met3 ;
        RECT 433.595 1635.225 433.895 1635.525 ;
    END
  END col_event_rst_top_left<28>
  PIN col_event_rst_top_left<27>
    ANTENNAGATEAREA 4.032000 ;
    PORT
      LAYER met3 ;
        RECT 435.500 1635.225 435.800 1635.525 ;
    END
  END col_event_rst_top_left<27>
  PIN col_event_rst_top_left<16>
    ANTENNAGATEAREA 4.032000 ;
    PORT
      LAYER met3 ;
        RECT 577.595 1635.225 577.895 1635.525 ;
    END
  END col_event_rst_top_left<16>
  PIN col_event_rst_top_left<15>
    ANTENNAGATEAREA 4.032000 ;
    PORT
      LAYER met3 ;
        RECT 579.500 1635.225 579.800 1635.525 ;
    END
  END col_event_rst_top_left<15>
  PIN row_off_detect_bot<28>
    ANTENNAGATEAREA 8.064000 ;
    PORT
      LAYER met3 ;
        RECT 0.000 472.450 0.300 472.750 ;
    END
  END row_off_detect_bot<28>
  PIN array_col_bot_left<32>
    ANTENNADIFFAREA 0.870000 ;
    PORT
      LAYER met3 ;
        RECT 382.365 1.460 383.135 1.760 ;
    END
  END array_col_bot_left<32>
  PIN col_event_rst_top_left<53>
    ANTENNAGATEAREA 4.032000 ;
    PORT
      LAYER met3 ;
        RECT 123.500 1635.225 123.800 1635.525 ;
    END
  END col_event_rst_top_left<53>
  PIN col_event_rst_top_left<10>
    ANTENNAGATEAREA 4.032000 ;
    PORT
      LAYER met3 ;
        RECT 649.595 1635.225 649.895 1635.525 ;
    END
  END col_event_rst_top_left<10>
  PIN col_event_rst_top_left<50>
    ANTENNAGATEAREA 4.032000 ;
    PORT
      LAYER met3 ;
        RECT 169.595 1635.225 169.895 1635.525 ;
    END
  END col_event_rst_top_left<50>
  PIN array_col_bot_right<27>
    ANTENNADIFFAREA 0.870000 ;
    PORT
      LAYER met3 ;
        RECT 1206.245 1.460 1207.015 1.760 ;
    END
  END array_col_bot_right<27>
  PIN row_on_detect_top<55>
    ANTENNAGATEAREA 16.128000 ;
    PORT
      LAYER met3 ;
        RECT 0.000 926.690 0.300 926.990 ;
    END
  END row_on_detect_top<55>
  PIN row_off_detect_top<47>
    ANTENNAGATEAREA 8.064000 ;
    PORT
      LAYER met3 ;
        RECT 0.000 1021.210 0.300 1021.510 ;
    END
  END row_off_detect_top<47>
  PIN row_on_detect_bot<38>
    ANTENNAGATEAREA 16.128000 ;
    PORT
      LAYER met3 ;
        RECT 0.000 351.410 0.300 351.710 ;
    END
  END row_on_detect_bot<38>
  PIN row_on_detect_bot<39>
    ANTENNAGATEAREA 16.128000 ;
    PORT
      LAYER met3 ;
        RECT 0.000 350.730 0.300 351.030 ;
    END
  END row_on_detect_bot<39>
  PIN col_event_rst_top_right<43>
    ANTENNAGATEAREA 4.032000 ;
    PORT
      LAYER met3 ;
        RECT 1011.500 1635.225 1011.800 1635.525 ;
    END
  END col_event_rst_top_right<43>
  PIN col_event_rst_top_right<44>
    ANTENNAGATEAREA 4.032000 ;
    PORT
      LAYER met3 ;
        RECT 1009.595 1635.225 1009.895 1635.525 ;
    END
  END col_event_rst_top_right<44>
  PIN row_off_detect_top<48>
    ANTENNAGATEAREA 8.064000 ;
    PORT
      LAYER met3 ;
        RECT 0.000 1000.810 0.300 1001.110 ;
    END
  END row_off_detect_top<48>
  PIN row_on_detect_top<47>
    ANTENNAGATEAREA 16.128000 ;
    PORT
      LAYER met3 ;
        RECT 0.000 1022.570 0.300 1022.870 ;
    END
  END row_on_detect_top<47>
  PIN col_event_rst_top_right<47>
    ANTENNAGATEAREA 4.032000 ;
    PORT
      LAYER met3 ;
        RECT 963.500 1635.225 963.800 1635.525 ;
    END
  END col_event_rst_top_right<47>
  PIN col_event_rst_top_right<48>
    ANTENNAGATEAREA 4.032000 ;
    PORT
      LAYER met3 ;
        RECT 961.595 1635.225 961.895 1635.525 ;
    END
  END col_event_rst_top_right<48>
  PIN row_on_detect_bot<57>
    ANTENNAGATEAREA 16.128000 ;
    PORT
      LAYER met3 ;
        RECT 0.000 134.490 0.300 134.790 ;
    END
  END row_on_detect_bot<57>
  PIN col_event_rst_top_right<51>
    ANTENNAGATEAREA 4.032000 ;
    PORT
      LAYER met3 ;
        RECT 915.500 1635.225 915.800 1635.525 ;
    END
  END col_event_rst_top_right<51>
  PIN col_event_rst_top_right<52>
    ANTENNAGATEAREA 4.032000 ;
    PORT
      LAYER met3 ;
        RECT 913.595 1635.225 913.895 1635.525 ;
    END
  END col_event_rst_top_right<52>
  PIN dac_config_1
    ANTENNAGATEAREA 36864.000000 ;
    PORT
      LAYER met3 ;
        RECT 1559.700 818.570 1560.000 818.870 ;
    END
  END dac_config_1
  PIN col_event_rst_top_right<55>
    ANTENNAGATEAREA 4.032000 ;
    PORT
      LAYER met3 ;
        RECT 867.500 1635.225 867.800 1635.525 ;
    END
  END col_event_rst_top_right<55>
  PIN col_event_rst_top_right<56>
    ANTENNAGATEAREA 4.032000 ;
    PORT
      LAYER met3 ;
        RECT 865.595 1635.225 865.895 1635.525 ;
    END
  END col_event_rst_top_right<56>
  PIN col_event_rst_top_right<59>
    ANTENNAGATEAREA 4.032000 ;
    PORT
      LAYER met3 ;
        RECT 819.500 1635.225 819.800 1635.525 ;
    END
  END col_event_rst_top_right<59>
  PIN array_col_top_right<27>
    ANTENNADIFFAREA 0.870000 ;
    PORT
      LAYER met3 ;
        RECT 1206.245 1635.345 1207.015 1635.645 ;
    END
  END array_col_top_right<27>
  PIN array_col_top_right<38>
    ANTENNADIFFAREA 0.870000 ;
    PORT
      LAYER met3 ;
        RECT 1078.365 1635.345 1079.135 1635.645 ;
    END
  END array_col_top_right<38>
  PIN row_off_detect_bot<39>
    ANTENNAGATEAREA 8.064000 ;
    PORT
      LAYER met3 ;
        RECT 0.000 349.370 0.300 349.670 ;
    END
  END row_off_detect_bot<39>
  PIN array_col_top_right<3>
    ANTENNADIFFAREA 0.870000 ;
    PORT
      LAYER met3 ;
        RECT 1494.245 1635.345 1495.015 1635.645 ;
    END
  END array_col_top_right<3>
  PIN row_off_detect_bot<9>
    ANTENNAGATEAREA 8.064000 ;
    PORT
      LAYER met3 ;
        RECT 0.000 709.090 0.300 709.390 ;
    END
  END row_off_detect_bot<9>
  PIN row_off_detect_bot<12>
    ANTENNAGATEAREA 8.064000 ;
    PORT
      LAYER met3 ;
        RECT 0.000 664.890 0.300 665.190 ;
    END
  END row_off_detect_bot<12>
  PIN row_on_detect_bot<18>
    ANTENNAGATEAREA 16.128000 ;
    PORT
      LAYER met3 ;
        RECT 0.000 591.450 0.300 591.750 ;
    END
  END row_on_detect_bot<18>
  PIN row_off_detect_bot<18>
    ANTENNAGATEAREA 8.064000 ;
    PORT
      LAYER met3 ;
        RECT 0.000 592.810 0.300 593.110 ;
    END
  END row_off_detect_bot<18>
  PIN array_col_top_left<33>
    ANTENNADIFFAREA 0.870000 ;
    PORT
      LAYER met3 ;
        RECT 366.245 1635.345 367.015 1635.645 ;
    END
  END array_col_top_left<33>
  PIN row_on_detect_top<6>
    ANTENNAGATEAREA 16.128000 ;
    PORT
      LAYER met3 ;
        RECT 0.000 1503.330 0.300 1503.630 ;
    END
  END row_on_detect_top<6>
  PIN pre_charge_global_bot_left
    ANTENNAGATEAREA 1024.000000 ;
    PORT
      LAYER met3 ;
        RECT 2.740 30.450 3.040 30.750 ;
    END
  END pre_charge_global_bot_left
  PIN array_col_top_right<30>
    ANTENNADIFFAREA 0.870000 ;
    PORT
      LAYER met3 ;
        RECT 1174.365 1635.345 1175.135 1635.645 ;
    END
  END array_col_top_right<30>
  PIN row_off_detect_bot<14>
    ANTENNAGATEAREA 8.064000 ;
    PORT
      LAYER met3 ;
        RECT 0.000 640.410 0.300 640.710 ;
    END
  END row_off_detect_bot<14>
  PIN row_on_detect_bot<14>
    ANTENNAGATEAREA 16.128000 ;
    PORT
      LAYER met3 ;
        RECT 0.000 639.730 0.300 640.030 ;
    END
  END row_on_detect_bot<14>
  PIN array_col_top_left<52>
    ANTENNADIFFAREA 0.870000 ;
    PORT
      LAYER met3 ;
        RECT 142.365 1635.345 143.135 1635.645 ;
    END
  END array_col_top_left<52>
  PIN row_on_detect_top<5>
    ANTENNAGATEAREA 16.128000 ;
    PORT
      LAYER met3 ;
        RECT 0.000 1526.450 0.300 1526.750 ;
    END
  END row_on_detect_top<5>
  PIN array_col_top_left<37>
    ANTENNADIFFAREA 0.870000 ;
    PORT
      LAYER met3 ;
        RECT 318.245 1635.345 319.015 1635.645 ;
    END
  END array_col_top_left<37>
  PIN array_col_bot_left<0>
    ANTENNADIFFAREA 0.870000 ;
    PORT
      LAYER met3 ;
        RECT 766.365 1.460 767.135 1.760 ;
    END
  END array_col_bot_left<0>
  PIN array_col_top_left<39>
    ANTENNADIFFAREA 0.870000 ;
    PORT
      LAYER met3 ;
        RECT 294.245 1635.345 295.015 1635.645 ;
    END
  END array_col_top_left<39>
  PIN array_col_top_left<2>
    ANTENNADIFFAREA 0.870000 ;
    PORT
      LAYER met3 ;
        RECT 742.365 1635.345 743.135 1635.645 ;
    END
  END array_col_top_left<2>
  PIN array_col_top_left<55>
    ANTENNADIFFAREA 0.870000 ;
    PORT
      LAYER met3 ;
        RECT 102.245 1635.345 103.015 1635.645 ;
    END
  END array_col_top_left<55>
  PIN row_off_detect_top<37>
    ANTENNAGATEAREA 8.064000 ;
    PORT
      LAYER met3 ;
        RECT 0.000 1141.570 0.300 1141.870 ;
    END
  END row_off_detect_top<37>
  PIN row_on_detect_top<39>
    ANTENNAGATEAREA 16.128000 ;
    PORT
      LAYER met3 ;
        RECT 0.000 1118.450 0.300 1118.750 ;
    END
  END row_on_detect_top<39>
  PIN array_col_top_left<56>
    ANTENNADIFFAREA 0.870000 ;
    PORT
      LAYER met3 ;
        RECT 94.365 1635.345 95.135 1635.645 ;
    END
  END array_col_top_left<56>
  PIN array_col_top_left<63>
    ANTENNADIFFAREA 0.870000 ;
    PORT
      LAYER met3 ;
        RECT 6.245 1635.345 7.015 1635.645 ;
    END
  END array_col_top_left<63>
  PIN array_col_top_left<42>
    ANTENNADIFFAREA 0.870000 ;
    PORT
      LAYER met3 ;
        RECT 262.365 1635.345 263.135 1635.645 ;
    END
  END array_col_top_left<42>
  PIN array_col_top_left<59>
    ANTENNADIFFAREA 0.870000 ;
    PORT
      LAYER met3 ;
        RECT 54.245 1635.345 55.015 1635.645 ;
    END
  END array_col_top_left<59>
  PIN array_col_top_left<43>
    ANTENNADIFFAREA 0.870000 ;
    PORT
      LAYER met3 ;
        RECT 246.245 1635.345 247.015 1635.645 ;
    END
  END array_col_top_left<43>
  PIN array_col_top_left<44>
    ANTENNADIFFAREA 0.870000 ;
    PORT
      LAYER met3 ;
        RECT 238.365 1635.345 239.135 1635.645 ;
    END
  END array_col_top_left<44>
  PIN array_col_top_left<11>
    ANTENNADIFFAREA 0.870000 ;
    PORT
      LAYER met3 ;
        RECT 630.245 1635.345 631.015 1635.645 ;
    END
  END array_col_top_left<11>
  PIN col_event_rst_top_right<60>
    ANTENNAGATEAREA 4.032000 ;
    PORT
      LAYER met3 ;
        RECT 817.595 1635.225 817.895 1635.525 ;
    END
  END col_event_rst_top_right<60>
  PIN col_event_rst_top_right<63>
    ANTENNAGATEAREA 4.032000 ;
    PORT
      LAYER met3 ;
        RECT 771.500 1636.475 771.800 1636.775 ;
    END
  END col_event_rst_top_right<63>
  PIN array_col_top_left<46>
    ANTENNADIFFAREA 0.870000 ;
    PORT
      LAYER met3 ;
        RECT 214.365 1635.345 215.135 1635.645 ;
    END
  END array_col_top_left<46>
  PIN row_off_detect_top<11>
    ANTENNAGATEAREA 8.064000 ;
    PORT
      LAYER met3 ;
        RECT 0.000 1453.690 0.300 1453.990 ;
    END
  END row_off_detect_top<11>
  PIN col_event_rst_top_left<0>
    ANTENNAGATEAREA 4.032000 ;
    PORT
      LAYER met3 ;
        RECT 769.595 1635.225 769.895 1635.525 ;
    END
  END col_event_rst_top_left<0>
  PIN col_event_rst_top_left<3>
    ANTENNAGATEAREA 4.032000 ;
    PORT
      LAYER met3 ;
        RECT 723.500 1635.225 723.800 1635.525 ;
    END
  END col_event_rst_top_left<3>
  PIN col_event_rst_top_left<4>
    ANTENNAGATEAREA 4.032000 ;
    PORT
      LAYER met3 ;
        RECT 721.595 1635.225 721.895 1635.525 ;
    END
  END col_event_rst_top_left<4>
  PIN col_event_rst_top_left<7>
    ANTENNAGATEAREA 4.032000 ;
    PORT
      LAYER met3 ;
        RECT 675.500 1635.225 675.800 1635.525 ;
    END
  END col_event_rst_top_left<7>
  PIN row_off_detect_bot<4>
    ANTENNAGATEAREA 8.064000 ;
    PORT
      LAYER met3 ;
        RECT 0.000 760.770 0.300 761.070 ;
    END
  END row_off_detect_bot<4>
  PIN row_on_detect_top<22>
    ANTENNAGATEAREA 16.128000 ;
    PORT
      LAYER met3 ;
        RECT 0.000 1311.570 0.300 1311.870 ;
    END
  END row_on_detect_top<22>
  PIN row_off_detect_bot<53>
    ANTENNAGATEAREA 8.064000 ;
    PORT
      LAYER met3 ;
        RECT 0.000 181.410 0.300 181.710 ;
    END
  END row_off_detect_bot<53>
  PIN row_off_detect_bot<54>
    ANTENNAGATEAREA 8.064000 ;
    PORT
      LAYER met3 ;
        RECT 0.000 161.010 0.300 161.310 ;
    END
  END row_off_detect_bot<54>
  PIN row_off_detect_top<61>
    ANTENNAGATEAREA 8.064000 ;
    PORT
      LAYER met3 ;
        RECT 0.000 853.250 0.300 853.550 ;
    END
  END row_off_detect_top<61>
  PIN row_on_detect_top<58>
    ANTENNAGATEAREA 16.128000 ;
    PORT
      LAYER met3 ;
        RECT 0.000 879.770 0.300 880.070 ;
    END
  END row_on_detect_top<58>
  PIN row_off_detect_top<58>
    ANTENNAGATEAREA 8.064000 ;
    PORT
      LAYER met3 ;
        RECT 0.000 880.450 0.300 880.750 ;
    END
  END row_off_detect_top<58>
  PIN row_off_detect_bot<37>
    ANTENNAGATEAREA 8.064000 ;
    PORT
      LAYER met3 ;
        RECT 0.000 373.170 0.300 373.470 ;
    END
  END row_off_detect_bot<37>
  PIN row_off_detect_bot<27>
    ANTENNAGATEAREA 8.064000 ;
    PORT
      LAYER met3 ;
        RECT 0.000 493.530 0.300 493.830 ;
    END
  END row_off_detect_bot<27>
  PIN row_off_detect_top<10>
    ANTENNAGATEAREA 8.064000 ;
    PORT
      LAYER met3 ;
        RECT 0.000 1456.410 0.300 1456.710 ;
    END
  END row_off_detect_top<10>
  PIN row_on_detect_top<10>
    ANTENNAGATEAREA 16.128000 ;
    PORT
      LAYER met3 ;
        RECT 0.000 1455.730 0.300 1456.030 ;
    END
  END row_on_detect_top<10>
  PIN row_on_detect_bot<22>
    ANTENNAGATEAREA 16.128000 ;
    PORT
      LAYER met3 ;
        RECT 0.000 543.850 0.300 544.150 ;
    END
  END row_on_detect_bot<22>
  PIN row_off_detect_top<13>
    ANTENNAGATEAREA 8.064000 ;
    PORT
      LAYER met3 ;
        RECT 0.000 1429.210 0.300 1429.510 ;
    END
  END row_off_detect_top<13>
  PIN row_on_detect_top<12>
    ANTENNAGATEAREA 16.128000 ;
    PORT
      LAYER met3 ;
        RECT 0.000 1431.250 0.300 1431.550 ;
    END
  END row_on_detect_top<12>
  PIN row_on_detect_bot<19>
    ANTENNAGATEAREA 16.128000 ;
    PORT
      LAYER met3 ;
        RECT 0.000 590.090 0.300 590.390 ;
    END
  END row_on_detect_bot<19>
  PIN row_off_detect_bot<15>
    ANTENNAGATEAREA 8.064000 ;
    PORT
      LAYER met3 ;
        RECT 0.000 637.690 0.300 637.990 ;
    END
  END row_off_detect_bot<15>
  PIN array_col_bot_right<18>
    ANTENNADIFFAREA 0.870000 ;
    PORT
      LAYER met3 ;
        RECT 1318.365 1.460 1319.135 1.760 ;
    END
  END array_col_bot_right<18>
  PIN row_on_detect_top<20>
    ANTENNAGATEAREA 16.128000 ;
    PORT
      LAYER met3 ;
        RECT 0.000 1336.050 0.300 1336.350 ;
    END
  END row_on_detect_top<20>
  PIN row_off_detect_bot<13>
    ANTENNAGATEAREA 8.064000 ;
    PORT
      LAYER met3 ;
        RECT 0.000 661.490 0.300 661.790 ;
    END
  END row_off_detect_bot<13>
  PIN row_on_detect_bot<9>
    ANTENNAGATEAREA 16.128000 ;
    PORT
      LAYER met3 ;
        RECT 0.000 710.450 0.300 710.750 ;
    END
  END row_on_detect_bot<9>
  PIN row_on_detect_bot<8>
    ANTENNAGATEAREA 16.128000 ;
    PORT
      LAYER met3 ;
        RECT 0.000 711.810 0.300 712.110 ;
    END
  END row_on_detect_bot<8>
  PIN row_on_detect_bot<47>
    ANTENNAGATEAREA 16.128000 ;
    PORT
      LAYER met3 ;
        RECT 0.000 254.850 0.300 255.150 ;
    END
  END row_on_detect_bot<47>
  PIN row_on_detect_bot<46>
    ANTENNAGATEAREA 16.128000 ;
    PORT
      LAYER met3 ;
        RECT 0.000 255.530 0.300 255.830 ;
    END
  END row_on_detect_bot<46>
  PIN row_on_detect_bot<28>
    ANTENNAGATEAREA 16.128000 ;
    PORT
      LAYER met3 ;
        RECT 0.000 471.770 0.300 472.070 ;
    END
  END row_on_detect_bot<28>
  PIN row_off_detect_bot<20>
    ANTENNAGATEAREA 8.064000 ;
    PORT
      LAYER met3 ;
        RECT 0.000 569.010 0.300 569.310 ;
    END
  END row_off_detect_bot<20>
  PIN row_on_detect_bot<17>
    ANTENNAGATEAREA 16.128000 ;
    PORT
      LAYER met3 ;
        RECT 0.000 614.570 0.300 614.870 ;
    END
  END row_on_detect_bot<17>
  PIN row_off_detect_bot<16>
    ANTENNAGATEAREA 8.064000 ;
    PORT
      LAYER met3 ;
        RECT 0.000 616.610 0.300 616.910 ;
    END
  END row_off_detect_bot<16>
  PIN row_on_detect_bot<16>
    ANTENNAGATEAREA 16.128000 ;
    PORT
      LAYER met3 ;
        RECT 0.000 615.250 0.300 615.550 ;
    END
  END row_on_detect_bot<16>
  PIN row_on_detect_top<49>
    ANTENNAGATEAREA 16.128000 ;
    PORT
      LAYER met3 ;
        RECT 0.000 998.090 0.300 998.390 ;
    END
  END row_on_detect_top<49>
  PIN array_col_bot_right<19>
    ANTENNADIFFAREA 0.870000 ;
    PORT
      LAYER met3 ;
        RECT 1302.245 1.460 1303.015 1.760 ;
    END
  END array_col_bot_right<19>
  PIN row_on_detect_bot<10>
    ANTENNAGATEAREA 16.128000 ;
    PORT
      LAYER met3 ;
        RECT 0.000 687.330 0.300 687.630 ;
    END
  END row_on_detect_bot<10>
  PIN row_off_detect_top<60>
    ANTENNAGATEAREA 8.064000 ;
    PORT
      LAYER met3 ;
        RECT 0.000 856.650 0.300 856.950 ;
    END
  END row_off_detect_top<60>
  PIN row_on_detect_bot<2>
    ANTENNAGATEAREA 16.128000 ;
    PORT
      LAYER met3 ;
        RECT 0.000 783.210 0.300 783.510 ;
    END
  END row_on_detect_bot<2>
  PIN array_col_top_left<16>
    ANTENNADIFFAREA 0.870000 ;
    PORT
      LAYER met3 ;
        RECT 574.365 1635.345 575.135 1635.645 ;
    END
  END array_col_top_left<16>
  PIN array_col_top_right<36>
    ANTENNADIFFAREA 0.870000 ;
    PORT
      LAYER met3 ;
        RECT 1102.365 1635.345 1103.135 1635.645 ;
    END
  END array_col_top_right<36>
  PIN row_off_detect_top<24>
    ANTENNAGATEAREA 8.064000 ;
    PORT
      LAYER met3 ;
        RECT 0.000 1288.450 0.300 1288.750 ;
    END
  END row_off_detect_top<24>
  PIN array_col_top_right<34>
    ANTENNADIFFAREA 0.870000 ;
    PORT
      LAYER met3 ;
        RECT 1126.365 1635.345 1127.135 1635.645 ;
    END
  END array_col_top_right<34>
  PIN array_col_top_right<33>
    ANTENNADIFFAREA 0.870000 ;
    PORT
      LAYER met3 ;
        RECT 1134.245 1635.345 1135.015 1635.645 ;
    END
  END array_col_top_right<33>
  PIN row_on_detect_top<3>
    ANTENNAGATEAREA 16.128000 ;
    PORT
      LAYER met3 ;
        RECT 0.000 1550.930 0.300 1551.230 ;
    END
  END row_on_detect_top<3>
  PIN row_off_detect_bot<48>
    ANTENNAGATEAREA 8.064000 ;
    PORT
      LAYER met3 ;
        RECT 0.000 232.410 0.300 232.710 ;
    END
  END row_off_detect_bot<48>
  PIN row_off_detect_bot<51>
    ANTENNAGATEAREA 8.064000 ;
    PORT
      LAYER met3 ;
        RECT 0.000 205.210 0.300 205.510 ;
    END
  END row_off_detect_bot<51>
  PIN row_off_detect_top<31>
    ANTENNAGATEAREA 8.064000 ;
    PORT
      LAYER met3 ;
        RECT 0.000 1213.650 0.300 1213.950 ;
    END
  END row_off_detect_top<31>
  PIN row_on_detect_top<31>
    ANTENNAGATEAREA 16.128000 ;
    PORT
      LAYER met3 ;
        RECT 0.000 1214.330 0.300 1214.630 ;
    END
  END row_on_detect_top<31>
  PIN array_col_top_left<31>
    ANTENNADIFFAREA 0.870000 ;
    PORT
      LAYER met3 ;
        RECT 390.245 1635.345 391.015 1635.645 ;
    END
  END array_col_top_left<31>
  PIN row_off_detect_top<25>
    ANTENNAGATEAREA 8.064000 ;
    PORT
      LAYER met3 ;
        RECT 0.000 1285.730 0.300 1286.030 ;
    END
  END row_off_detect_top<25>
  PIN array_col_top_left<15>
    ANTENNADIFFAREA 0.870000 ;
    PORT
      LAYER met3 ;
        RECT 582.245 1635.345 583.015 1635.645 ;
    END
  END array_col_top_left<15>
  PIN row_on_detect_bot<51>
    ANTENNAGATEAREA 16.128000 ;
    PORT
      LAYER met3 ;
        RECT 0.000 206.570 0.300 206.870 ;
    END
  END row_on_detect_bot<51>
  PIN row_on_detect_bot<50>
    ANTENNAGATEAREA 16.128000 ;
    PORT
      LAYER met3 ;
        RECT 0.000 207.250 0.300 207.550 ;
    END
  END row_on_detect_bot<50>
  PIN row_on_detect_bot<48>
    ANTENNAGATEAREA 16.128000 ;
    PORT
      LAYER met3 ;
        RECT 0.000 231.730 0.300 232.030 ;
    END
  END row_on_detect_bot<48>
  PIN col_event_rst_top_left<46>
    ANTENNAGATEAREA 4.032000 ;
    PORT
      LAYER met3 ;
        RECT 217.595 1635.225 217.895 1635.525 ;
    END
  END col_event_rst_top_left<46>
  PIN ndetect_pulse_global_top_left
    ANTENNAGATEAREA 64.000000 ;
    PORT
      LAYER met3 ;
        RECT 2.740 1627.800 3.040 1628.100 ;
    END
  END ndetect_pulse_global_top_left
  PIN array_col_bot_left<44>
    ANTENNADIFFAREA 0.870000 ;
    PORT
      LAYER met3 ;
        RECT 238.365 1.460 239.135 1.760 ;
    END
  END array_col_bot_left<44>
  PIN row_off_detect_top<2>
    ANTENNAGATEAREA 8.064000 ;
    PORT
      LAYER met3 ;
        RECT 0.000 1552.970 0.300 1553.270 ;
    END
  END row_off_detect_top<2>
  PIN array_col_top_left<6>
    ANTENNADIFFAREA 0.870000 ;
    PORT
      LAYER met3 ;
        RECT 694.365 1635.345 695.135 1635.645 ;
    END
  END array_col_top_left<6>
  PIN row_off_detect_top<57>
    ANTENNAGATEAREA 8.064000 ;
    PORT
      LAYER met3 ;
        RECT 0.000 901.530 0.300 901.830 ;
    END
  END row_off_detect_top<57>
  PIN row_on_detect_top<56>
    ANTENNAGATEAREA 16.128000 ;
    PORT
      LAYER met3 ;
        RECT 0.000 903.570 0.300 903.870 ;
    END
  END row_on_detect_top<56>
  PIN row_on_detect_top<61>
    ANTENNAGATEAREA 16.128000 ;
    PORT
      LAYER met3 ;
        RECT 0.000 854.610 0.300 854.910 ;
    END
  END row_on_detect_top<61>
  PIN row_off_detect_top<22>
    ANTENNAGATEAREA 8.064000 ;
    PORT
      LAYER met3 ;
        RECT 0.000 1312.930 0.300 1313.230 ;
    END
  END row_off_detect_top<22>
  PIN row_off_detect_bot<58>
    ANTENNAGATEAREA 8.064000 ;
    PORT
      LAYER met3 ;
        RECT 0.000 112.730 0.300 113.030 ;
    END
  END row_off_detect_bot<58>
  PIN row_off_detect_bot<55>
    ANTENNAGATEAREA 8.064000 ;
    PORT
      LAYER met3 ;
        RECT 0.000 157.610 0.300 157.910 ;
    END
  END row_off_detect_bot<55>
  PIN array_col_top_right<62>
    ANTENNADIFFAREA 0.870000 ;
    PORT
      LAYER met3 ;
        RECT 790.365 1635.345 791.135 1635.645 ;
    END
  END array_col_top_right<62>
  PIN array_col_top_right<61>
    ANTENNADIFFAREA 0.870000 ;
    PORT
      LAYER met3 ;
        RECT 798.245 1635.345 799.015 1635.645 ;
    END
  END array_col_top_right<61>
  PIN row_off_detect_bot<0>
    ANTENNAGATEAREA 8.064000 ;
    PORT
      LAYER met3 ;
        RECT 0.000 808.370 0.300 808.670 ;
    END
  END row_off_detect_bot<0>
  PIN row_off_detect_top<63>
    ANTENNAGATEAREA 8.064000 ;
    PORT
      LAYER met3 ;
        RECT 0.000 829.450 0.300 829.750 ;
    END
  END row_off_detect_top<63>
  PIN col_event_rst_top_left<62>
    ANTENNAGATEAREA 4.032000 ;
    PORT
      LAYER met3 ;
        RECT 25.595 1635.225 25.895 1635.525 ;
    END
  END col_event_rst_top_left<62>
  PIN col_event_rst_top_left<57>
    ANTENNAGATEAREA 4.032000 ;
    PORT
      LAYER met3 ;
        RECT 75.500 1635.225 75.800 1635.525 ;
    END
  END col_event_rst_top_left<57>
  PIN col_event_rst_top_left<56>
    ANTENNAGATEAREA 4.032000 ;
    PORT
      LAYER met3 ;
        RECT 97.595 1635.225 97.895 1635.525 ;
    END
  END col_event_rst_top_left<56>
  PIN col_event_rst_top_left<51>
    ANTENNAGATEAREA 4.032000 ;
    PORT
      LAYER met3 ;
        RECT 147.500 1635.225 147.800 1635.525 ;
    END
  END col_event_rst_top_left<51>
  PIN array_col_bot_right<62>
    ANTENNADIFFAREA 0.870000 ;
    PORT
      LAYER met3 ;
        RECT 790.365 1.460 791.135 1.760 ;
    END
  END array_col_bot_right<62>
  PIN array_col_top_right<28>
    ANTENNADIFFAREA 0.870000 ;
    PORT
      LAYER met3 ;
        RECT 1198.365 1635.345 1199.135 1635.645 ;
    END
  END array_col_top_right<28>
  PIN array_col_bot_right<6>
    ANTENNADIFFAREA 0.870000 ;
    PORT
      LAYER met3 ;
        RECT 1462.365 1.460 1463.135 1.760 ;
    END
  END array_col_bot_right<6>
  PIN row_on_detect_top<34>
    ANTENNAGATEAREA 16.128000 ;
    PORT
      LAYER met3 ;
        RECT 0.000 1167.410 0.300 1167.710 ;
    END
  END row_on_detect_top<34>
  PIN row_on_detect_top<29>
    ANTENNAGATEAREA 16.128000 ;
    PORT
      LAYER met3 ;
        RECT 0.000 1238.810 0.300 1239.110 ;
    END
  END row_on_detect_top<29>
  PIN row_off_detect_top<28>
    ANTENNAGATEAREA 8.064000 ;
    PORT
      LAYER met3 ;
        RECT 0.000 1240.850 0.300 1241.150 ;
    END
  END row_off_detect_top<28>
  PIN row_on_detect_top<27>
    ANTENNAGATEAREA 16.128000 ;
    PORT
      LAYER met3 ;
        RECT 0.000 1262.610 0.300 1262.910 ;
    END
  END row_on_detect_top<27>
  PIN array_col_bot_right<58>
    ANTENNADIFFAREA 0.870000 ;
    PORT
      LAYER met3 ;
        RECT 838.365 1.460 839.135 1.760 ;
    END
  END array_col_bot_right<58>
  PIN array_col_bot_right<55>
    ANTENNADIFFAREA 0.870000 ;
    PORT
      LAYER met3 ;
        RECT 870.245 1.460 871.015 1.760 ;
    END
  END array_col_bot_right<55>
  PIN row_on_detect_bot<40>
    ANTENNAGATEAREA 16.128000 ;
    PORT
      LAYER met3 ;
        RECT 0.000 327.610 0.300 327.910 ;
    END
  END row_on_detect_bot<40>
  PIN array_col_top_right<37>
    ANTENNADIFFAREA 0.870000 ;
    PORT
      LAYER met3 ;
        RECT 1086.245 1635.345 1087.015 1635.645 ;
    END
  END array_col_top_right<37>
  PIN row_on_detect_bot<59>
    ANTENNAGATEAREA 16.128000 ;
    PORT
      LAYER met3 ;
        RECT 0.000 110.690 0.300 110.990 ;
    END
  END row_on_detect_bot<59>
  PIN row_off_detect_bot<57>
    ANTENNAGATEAREA 8.064000 ;
    PORT
      LAYER met3 ;
        RECT 0.000 133.130 0.300 133.430 ;
    END
  END row_off_detect_bot<57>
  PIN row_on_detect_bot<25>
    ANTENNAGATEAREA 16.128000 ;
    PORT
      LAYER met3 ;
        RECT 0.000 518.690 0.300 518.990 ;
    END
  END row_on_detect_bot<25>
  PIN array_col_top_left<1>
    ANTENNADIFFAREA 0.870000 ;
    PORT
      LAYER met3 ;
        RECT 750.245 1635.345 751.015 1635.645 ;
    END
  END array_col_top_left<1>
  PIN row_on_detect_bot<27>
    ANTENNAGATEAREA 16.128000 ;
    PORT
      LAYER met3 ;
        RECT 0.000 494.890 0.300 495.190 ;
    END
  END row_on_detect_bot<27>
  PIN row_off_detect_bot<29>
    ANTENNAGATEAREA 8.064000 ;
    PORT
      LAYER met3 ;
        RECT 0.000 469.730 0.300 470.030 ;
    END
  END row_off_detect_bot<29>
  PIN row_off_detect_bot<30>
    ANTENNAGATEAREA 8.064000 ;
    PORT
      LAYER met3 ;
        RECT 0.000 448.650 0.300 448.950 ;
    END
  END row_off_detect_bot<30>
  PIN row_off_detect_bot<33>
    ANTENNAGATEAREA 8.064000 ;
    PORT
      LAYER met3 ;
        RECT 0.000 421.450 0.300 421.750 ;
    END
  END row_off_detect_bot<33>
  PIN row_off_detect_bot<34>
    ANTENNAGATEAREA 8.064000 ;
    PORT
      LAYER met3 ;
        RECT 0.000 400.370 0.300 400.670 ;
    END
  END row_off_detect_bot<34>
  PIN row_on_detect_bot<36>
    ANTENNAGATEAREA 16.128000 ;
    PORT
      LAYER met3 ;
        RECT 0.000 375.210 0.300 375.510 ;
    END
  END row_on_detect_bot<36>
  PIN row_on_detect_top<59>
    ANTENNAGATEAREA 16.128000 ;
    PORT
      LAYER met3 ;
        RECT 0.000 878.410 0.300 878.710 ;
    END
  END row_on_detect_top<59>
  PIN row_off_detect_bot<7>
    ANTENNAGATEAREA 8.064000 ;
    PORT
      LAYER met3 ;
        RECT 0.000 733.570 0.300 733.870 ;
    END
  END row_off_detect_bot<7>
  PIN array_col_top_right<58>
    ANTENNADIFFAREA 0.870000 ;
    PORT
      LAYER met3 ;
        RECT 838.365 1635.345 839.135 1635.645 ;
    END
  END array_col_top_right<58>
  PIN array_col_top_right<55>
    ANTENNADIFFAREA 0.870000 ;
    PORT
      LAYER met3 ;
        RECT 870.245 1635.345 871.015 1635.645 ;
    END
  END array_col_top_right<55>
  PIN array_col_top_right<54>
    ANTENNADIFFAREA 0.870000 ;
    PORT
      LAYER met3 ;
        RECT 886.365 1635.345 887.135 1635.645 ;
    END
  END array_col_top_right<54>
  PIN array_col_top_right<52>
    ANTENNADIFFAREA 0.870000 ;
    PORT
      LAYER met3 ;
        RECT 910.365 1635.345 911.135 1635.645 ;
    END
  END array_col_top_right<52>
  PIN array_col_top_right<51>
    ANTENNADIFFAREA 0.870000 ;
    PORT
      LAYER met3 ;
        RECT 918.245 1635.345 919.015 1635.645 ;
    END
  END array_col_top_right<51>
  PIN array_col_top_right<49>
    ANTENNADIFFAREA 0.870000 ;
    PORT
      LAYER met3 ;
        RECT 942.245 1635.345 943.015 1635.645 ;
    END
  END array_col_top_right<49>
  PIN array_col_top_right<46>
    ANTENNADIFFAREA 0.870000 ;
    PORT
      LAYER met3 ;
        RECT 982.365 1635.345 983.135 1635.645 ;
    END
  END array_col_top_right<46>
  PIN row_on_detect_top<23>
    ANTENNAGATEAREA 16.128000 ;
    PORT
      LAYER met3 ;
        RECT 0.000 1310.890 0.300 1311.190 ;
    END
  END row_on_detect_top<23>
  PIN row_off_detect_top<20>
    ANTENNAGATEAREA 8.064000 ;
    PORT
      LAYER met3 ;
        RECT 0.000 1336.730 0.300 1337.030 ;
    END
  END row_off_detect_top<20>
  PIN array_col_top_right<43>
    ANTENNADIFFAREA 0.870000 ;
    PORT
      LAYER met3 ;
        RECT 1014.245 1635.345 1015.015 1635.645 ;
    END
  END array_col_top_right<43>
  PIN array_col_top_right<42>
    ANTENNADIFFAREA 0.870000 ;
    PORT
      LAYER met3 ;
        RECT 1030.365 1635.345 1031.135 1635.645 ;
    END
  END array_col_top_right<42>
  PIN row_off_detect_bot<10>
    ANTENNAGATEAREA 8.064000 ;
    PORT
      LAYER met3 ;
        RECT 0.000 688.690 0.300 688.990 ;
    END
  END row_off_detect_bot<10>
  PIN array_col_top_left<3>
    ANTENNADIFFAREA 0.870000 ;
    PORT
      LAYER met3 ;
        RECT 726.245 1635.345 727.015 1635.645 ;
    END
  END array_col_top_left<3>
  PIN array_col_bot_right<2>
    ANTENNADIFFAREA 0.870000 ;
    PORT
      LAYER met3 ;
        RECT 1510.365 1.460 1511.135 1.760 ;
    END
  END array_col_bot_right<2>
  PIN row_off_detect_bot<2>
    ANTENNAGATEAREA 8.064000 ;
    PORT
      LAYER met3 ;
        RECT 0.000 784.570 0.300 784.870 ;
    END
  END row_off_detect_bot<2>
  PIN row_off_detect_bot<1>
    ANTENNAGATEAREA 8.064000 ;
    PORT
      LAYER met3 ;
        RECT 0.000 805.650 0.300 805.950 ;
    END
  END row_off_detect_bot<1>
  PIN row_on_detect_bot<3>
    ANTENNAGATEAREA 16.128000 ;
    PORT
      LAYER met3 ;
        RECT 0.000 782.530 0.300 782.830 ;
    END
  END row_on_detect_bot<3>
  PIN row_off_detect_bot<56>
    ANTENNAGATEAREA 8.064000 ;
    PORT
      LAYER met3 ;
        RECT 0.000 136.530 0.300 136.830 ;
    END
  END row_off_detect_bot<56>
  PIN row_off_detect_bot<59>
    PORT
      LAYER met3 ;
        RECT 0.000 109.330 0.300 109.630 ;
    END
  END row_off_detect_bot<59>
  PIN row_off_detect_top<21>
    ANTENNAGATEAREA 8.064000 ;
    PORT
      LAYER met3 ;
        RECT 0.000 1333.330 0.300 1333.630 ;
    END
  END row_off_detect_top<21>
  PIN array_col_top_left<22>
    ANTENNADIFFAREA 0.870000 ;
    PORT
      LAYER met3 ;
        RECT 502.365 1635.345 503.135 1635.645 ;
    END
  END array_col_top_left<22>
  PIN array_col_top_left<23>
    ANTENNADIFFAREA 0.870000 ;
    PORT
      LAYER met3 ;
        RECT 486.245 1635.345 487.015 1635.645 ;
    END
  END array_col_top_left<23>
  PIN row_on_detect_top<62>
    ANTENNAGATEAREA 16.128000 ;
    PORT
      LAYER met3 ;
        RECT 0.000 831.490 0.300 831.790 ;
    END
  END row_on_detect_top<62>
  PIN row_off_detect_bot<38>
    ANTENNAGATEAREA 8.064000 ;
    PORT
      LAYER met3 ;
        RECT 0.000 352.770 0.300 353.070 ;
    END
  END row_off_detect_bot<38>
  PIN row_on_detect_bot<29>
    ANTENNAGATEAREA 16.128000 ;
    PORT
      LAYER met3 ;
        RECT 0.000 470.410 0.300 470.710 ;
    END
  END row_on_detect_bot<29>
  PIN row_on_detect_bot<23>
    ANTENNAGATEAREA 16.128000 ;
    PORT
      LAYER met3 ;
        RECT 0.000 542.490 0.300 542.790 ;
    END
  END row_on_detect_bot<23>
  PIN row_off_detect_bot<19>
    ANTENNAGATEAREA 8.064000 ;
    PORT
      LAYER met3 ;
        RECT 0.000 589.410 0.300 589.710 ;
    END
  END row_off_detect_bot<19>
  PIN row_on_detect_bot<15>
    ANTENNAGATEAREA 16.128000 ;
    PORT
      LAYER met3 ;
        RECT 0.000 638.370 0.300 638.670 ;
    END
  END row_on_detect_bot<15>
  PIN row_on_detect_top<21>
    ANTENNAGATEAREA 16.128000 ;
    PORT
      LAYER met3 ;
        RECT 0.000 1334.690 0.300 1334.990 ;
    END
  END row_on_detect_top<21>
  PIN row_on_detect_top<50>
    ANTENNAGATEAREA 16.128000 ;
    PORT
      LAYER met3 ;
        RECT 0.000 975.650 0.300 975.950 ;
    END
  END row_on_detect_top<50>
  PIN row_off_detect_top<49>
    ANTENNAGATEAREA 8.064000 ;
    PORT
      LAYER met3 ;
        RECT 0.000 997.410 0.300 997.710 ;
    END
  END row_off_detect_top<49>
  PIN row_on_detect_bot<12>
    ANTENNAGATEAREA 16.128000 ;
    PORT
      LAYER met3 ;
        RECT 0.000 663.530 0.300 663.830 ;
    END
  END row_on_detect_bot<12>
  PIN row_off_detect_bot<23>
    ANTENNAGATEAREA 8.064000 ;
    PORT
      LAYER met3 ;
        RECT 0.000 541.130 0.300 541.430 ;
    END
  END row_off_detect_bot<23>
  PIN row_off_detect_bot<17>
    ANTENNAGATEAREA 8.064000 ;
    PORT
      LAYER met3 ;
        RECT 0.000 613.210 0.300 613.510 ;
    END
  END row_off_detect_bot<17>
  PIN row_off_detect_top<44>
    ANTENNAGATEAREA 8.064000 ;
    PORT
      LAYER met3 ;
        RECT 0.000 1048.410 0.300 1048.710 ;
    END
  END row_off_detect_top<44>
  PIN row_on_detect_top<2>
    ANTENNAGATEAREA 16.128000 ;
    PORT
      LAYER met3 ;
        RECT 0.000 1551.610 0.300 1551.910 ;
    END
  END row_on_detect_top<2>
  PIN row_off_detect_bot<11>
    ANTENNAGATEAREA 8.064000 ;
    PORT
      LAYER met3 ;
        RECT 0.000 685.290 0.300 685.590 ;
    END
  END row_off_detect_bot<11>
  PIN row_on_detect_top<60>
    ANTENNAGATEAREA 16.128000 ;
    PORT
      LAYER met3 ;
        RECT 0.000 855.290 0.300 855.590 ;
    END
  END row_on_detect_top<60>
  PIN row_on_detect_bot<4>
    ANTENNAGATEAREA 16.128000 ;
    PORT
      LAYER met3 ;
        RECT 0.000 759.410 0.300 759.710 ;
    END
  END row_on_detect_bot<4>
  PIN array_col_top_right<35>
    ANTENNADIFFAREA 0.870000 ;
    PORT
      LAYER met3 ;
        RECT 1110.245 1635.345 1111.015 1635.645 ;
    END
  END array_col_top_right<35>
  PIN row_off_detect_bot<60>
    ANTENNAGATEAREA 8.064000 ;
    PORT
      LAYER met3 ;
        RECT 0.000 88.930 0.300 89.230 ;
    END
  END row_off_detect_bot<60>
  PIN row_on_detect_bot<60>
    ANTENNAGATEAREA 16.128000 ;
    PORT
      LAYER met3 ;
        RECT 0.000 87.570 0.300 87.870 ;
    END
  END row_on_detect_bot<60>
  PIN row_off_detect_top<5>
    ANTENNAGATEAREA 8.064000 ;
    PORT
      LAYER met3 ;
        RECT 0.000 1525.090 0.300 1525.390 ;
    END
  END row_off_detect_top<5>
  PIN array_col_bot_right<1>
    ANTENNADIFFAREA 0.870000 ;
    PORT
      LAYER met3 ;
        RECT 1518.245 1.460 1519.015 1.760 ;
    END
  END array_col_bot_right<1>
  PIN array_col_top_left<14>
    ANTENNADIFFAREA 0.870000 ;
    PORT
      LAYER met3 ;
        RECT 598.365 1635.345 599.135 1635.645 ;
    END
  END array_col_top_left<14>
  PIN row_off_detect_top<27>
    ANTENNAGATEAREA 8.064000 ;
    PORT
      LAYER met3 ;
        RECT 0.000 1261.250 0.300 1261.550 ;
    END
  END row_off_detect_top<27>
  PIN row_off_detect_bot<26>
    ANTENNAGATEAREA 8.064000 ;
    PORT
      LAYER met3 ;
        RECT 0.000 496.930 0.300 497.230 ;
    END
  END row_off_detect_bot<26>
  PIN row_on_detect_bot<49>
    ANTENNAGATEAREA 16.128000 ;
    PORT
      LAYER met3 ;
        RECT 0.000 230.370 0.300 230.670 ;
    END
  END row_on_detect_bot<49>
  PIN ndetect_pulse_global_bot_left
    ANTENNAGATEAREA 64.000000 ;
    PORT
      LAYER met3 ;
        RECT 2.740 10.080 3.040 10.380 ;
    END
  END ndetect_pulse_global_bot_left
  PIN row_off_detect_top<1>
    ANTENNAGATEAREA 8.064000 ;
    PORT
      LAYER met3 ;
        RECT 0.000 1573.370 0.300 1573.670 ;
    END
  END row_off_detect_top<1>
  PIN row_on_detect_top<17>
    ANTENNAGATEAREA 16.128000 ;
    PORT
      LAYER met3 ;
        RECT 0.000 1382.290 0.300 1382.590 ;
    END
  END row_on_detect_top<17>
  PIN row_on_detect_top<16>
    ANTENNAGATEAREA 16.128000 ;
    PORT
      LAYER met3 ;
        RECT 0.000 1383.650 0.300 1383.950 ;
    END
  END row_on_detect_top<16>
  PIN array_col_top_left<28>
    ANTENNADIFFAREA 0.870000 ;
    PORT
      LAYER met3 ;
        RECT 430.365 1635.345 431.135 1635.645 ;
    END
  END array_col_top_left<28>
  PIN row_off_detect_top<19>
    ANTENNAGATEAREA 8.064000 ;
    PORT
      LAYER met3 ;
        RECT 0.000 1357.130 0.300 1357.430 ;
    END
  END row_off_detect_top<19>
  PIN row_off_detect_top<16>
    ANTENNAGATEAREA 8.064000 ;
    PORT
      LAYER met3 ;
        RECT 0.000 1385.010 0.300 1385.310 ;
    END
  END row_off_detect_top<16>
  PIN row_off_detect_top<62>
    ANTENNAGATEAREA 8.064000 ;
    PORT
      LAYER met3 ;
        RECT 0.000 832.850 0.300 833.150 ;
    END
  END row_off_detect_top<62>
  PIN row_on_detect_bot<58>
    ANTENNAGATEAREA 16.128000 ;
    PORT
      LAYER met3 ;
        RECT 0.000 112.050 0.300 112.350 ;
    END
  END row_on_detect_bot<58>
  PIN array_col_top_right<63>
    ANTENNADIFFAREA 0.870000 ;
    PORT
      LAYER met3 ;
        RECT 774.245 1635.345 775.015 1635.645 ;
    END
  END array_col_top_right<63>
  PIN array_col_top_right<60>
    ANTENNADIFFAREA 0.870000 ;
    PORT
      LAYER met3 ;
        RECT 814.365 1635.345 815.135 1635.645 ;
    END
  END array_col_top_right<60>
  PIN array_col_top_left<10>
    ANTENNADIFFAREA 0.870000 ;
    PORT
      LAYER met3 ;
        RECT 646.365 1635.345 647.135 1635.645 ;
    END
  END array_col_top_left<10>
  PIN array_col_top_left<30>
    ANTENNADIFFAREA 0.870000 ;
    PORT
      LAYER met3 ;
        RECT 406.365 1635.345 407.135 1635.645 ;
    END
  END array_col_top_left<30>
  PIN col_event_rst_top_right<61>
    ANTENNAGATEAREA 4.032000 ;
    PORT
      LAYER met3 ;
        RECT 795.500 1635.225 795.800 1635.525 ;
    END
  END col_event_rst_top_right<61>
  PIN col_event_rst_top_right<58>
    ANTENNAGATEAREA 4.032000 ;
    PORT
      LAYER met3 ;
        RECT 841.595 1635.225 841.895 1635.525 ;
    END
  END col_event_rst_top_right<58>
  PIN array_col_bot_right<4>
    ANTENNADIFFAREA 0.870000 ;
    PORT
      LAYER met3 ;
        RECT 1486.365 1.460 1487.135 1.760 ;
    END
  END array_col_bot_right<4>
  PIN dac_config_5
    ANTENNAGATEAREA 10321.919922 ;
    PORT
      LAYER met3 ;
        RECT 1559.700 824.690 1560.000 824.990 ;
    END
  END dac_config_5
  PIN col_event_rst_top_left<49>
    ANTENNAGATEAREA 4.032000 ;
    PORT
      LAYER met3 ;
        RECT 171.500 1635.225 171.800 1635.525 ;
    END
  END col_event_rst_top_left<49>
  PIN col_event_rst_top_left<45>
    ANTENNAGATEAREA 4.032000 ;
    PORT
      LAYER met3 ;
        RECT 219.500 1635.225 219.800 1635.525 ;
    END
  END col_event_rst_top_left<45>
  PIN row_on_detect_top<52>
    ANTENNAGATEAREA 16.128000 ;
    PORT
      LAYER met3 ;
        RECT 0.000 951.850 0.300 952.150 ;
    END
  END row_on_detect_top<52>
  PIN row_off_detect_top<52>
    ANTENNAGATEAREA 8.064000 ;
    PORT
      LAYER met3 ;
        RECT 0.000 952.530 0.300 952.830 ;
    END
  END row_off_detect_top<52>
  PIN array_col_top_left<35>
    ANTENNADIFFAREA 0.870000 ;
    PORT
      LAYER met3 ;
        RECT 342.245 1635.345 343.015 1635.645 ;
    END
  END array_col_top_left<35>
  PIN array_col_bot_right<22>
    ANTENNADIFFAREA 0.870000 ;
    PORT
      LAYER met3 ;
        RECT 1270.365 1.460 1271.135 1.760 ;
    END
  END array_col_bot_right<22>
  PIN row_off_detect_top<35>
    ANTENNAGATEAREA 8.064000 ;
    PORT
      LAYER met3 ;
        RECT 0.000 1165.370 0.300 1165.670 ;
    END
  END row_off_detect_top<35>
  PIN row_off_detect_top<26>
    ANTENNAGATEAREA 8.064000 ;
    PORT
      LAYER met3 ;
        RECT 0.000 1264.650 0.300 1264.950 ;
    END
  END row_off_detect_top<26>
  PIN array_col_bot_right<59>
    ANTENNADIFFAREA 0.870000 ;
    PORT
      LAYER met3 ;
        RECT 822.245 1.460 823.015 1.760 ;
    END
  END array_col_bot_right<59>
  PIN array_col_bot_right<0>
    ANTENNADIFFAREA 0.870000 ;
    PORT
      LAYER met3 ;
        RECT 1534.365 1.460 1535.135 1.760 ;
    END
  END array_col_bot_right<0>
  PIN row_on_detect_bot<41>
    ANTENNAGATEAREA 16.128000 ;
    PORT
      LAYER met3 ;
        RECT 0.000 326.930 0.300 327.230 ;
    END
  END row_on_detect_bot<41>
  PIN array_col_bot_right<54>
    ANTENNADIFFAREA 0.870000 ;
    PORT
      LAYER met3 ;
        RECT 886.365 1.460 887.135 1.760 ;
    END
  END array_col_bot_right<54>
  PIN array_col_bot_right<10>
    ANTENNADIFFAREA 0.870000 ;
    PORT
      LAYER met3 ;
        RECT 1414.365 1.460 1415.135 1.760 ;
    END
  END array_col_bot_right<10>
  PIN row_on_detect_bot<24>
    ANTENNAGATEAREA 16.128000 ;
    PORT
      LAYER met3 ;
        RECT 0.000 520.050 0.300 520.350 ;
    END
  END row_on_detect_bot<24>
  PIN row_off_detect_bot<24>
    ANTENNAGATEAREA 8.064000 ;
    PORT
      LAYER met3 ;
        RECT 0.000 520.730 0.300 521.030 ;
    END
  END row_off_detect_bot<24>
  PIN row_off_detect_top<45>
    ANTENNAGATEAREA 8.064000 ;
    PORT
      LAYER met3 ;
        RECT 0.000 1045.690 0.300 1045.990 ;
    END
  END row_off_detect_top<45>
  PIN row_on_detect_top<42>
    ANTENNAGATEAREA 16.128000 ;
    PORT
      LAYER met3 ;
        RECT 0.000 1071.530 0.300 1071.830 ;
    END
  END row_on_detect_top<42>
  PIN array_col_top_left<21>
    ANTENNADIFFAREA 0.870000 ;
    PORT
      LAYER met3 ;
        RECT 510.245 1635.345 511.015 1635.645 ;
    END
  END array_col_top_left<21>
  PIN row_on_detect_bot<32>
    ANTENNAGATEAREA 16.128000 ;
    PORT
      LAYER met3 ;
        RECT 0.000 423.490 0.300 423.790 ;
    END
  END row_on_detect_bot<32>
  PIN row_on_detect_bot<33>
    ANTENNAGATEAREA 16.128000 ;
    PORT
      LAYER met3 ;
        RECT 0.000 422.810 0.300 423.110 ;
    END
  END row_on_detect_bot<33>
  PIN row_on_detect_bot<6>
    ANTENNAGATEAREA 16.128000 ;
    PORT
      LAYER met3 ;
        RECT 0.000 735.610 0.300 735.910 ;
    END
  END row_on_detect_bot<6>
  PIN row_on_detect_bot<37>
    ANTENNAGATEAREA 16.128000 ;
    PORT
      LAYER met3 ;
        RECT 0.000 374.530 0.300 374.830 ;
    END
  END row_on_detect_bot<37>
  PIN array_col_top_left<5>
    ANTENNADIFFAREA 0.870000 ;
    PORT
      LAYER met3 ;
        RECT 702.245 1635.345 703.015 1635.645 ;
    END
  END array_col_top_left<5>
  PIN array_col_top_right<59>
    ANTENNADIFFAREA 0.870000 ;
    PORT
      LAYER met3 ;
        RECT 822.245 1635.345 823.015 1635.645 ;
    END
  END array_col_top_right<59>
  PIN row_off_detect_bot<8>
    ANTENNAGATEAREA 8.064000 ;
    PORT
      LAYER met3 ;
        RECT 0.000 712.490 0.300 712.790 ;
    END
  END row_off_detect_bot<8>
  PIN array_col_top_right<57>
    ANTENNADIFFAREA 0.870000 ;
    PORT
      LAYER met3 ;
        RECT 846.245 1635.345 847.015 1635.645 ;
    END
  END array_col_top_right<57>
  PIN array_col_top_right<56>
    ANTENNADIFFAREA 0.870000 ;
    PORT
      LAYER met3 ;
        RECT 862.365 1635.345 863.135 1635.645 ;
    END
  END array_col_top_right<56>
  PIN array_col_top_right<53>
    ANTENNADIFFAREA 0.870000 ;
    PORT
      LAYER met3 ;
        RECT 894.245 1635.345 895.015 1635.645 ;
    END
  END array_col_top_right<53>
  PIN array_col_top_right<50>
    ANTENNADIFFAREA 0.870000 ;
    PORT
      LAYER met3 ;
        RECT 934.365 1635.345 935.135 1635.645 ;
    END
  END array_col_top_right<50>
  PIN array_col_top_left<4>
    ANTENNADIFFAREA 0.870000 ;
    PORT
      LAYER met3 ;
        RECT 718.365 1635.345 719.135 1635.645 ;
    END
  END array_col_top_left<4>
  PIN array_col_top_right<48>
    ANTENNADIFFAREA 0.870000 ;
    PORT
      LAYER met3 ;
        RECT 958.365 1635.345 959.135 1635.645 ;
    END
  END array_col_top_right<48>
  PIN array_col_top_right<47>
    ANTENNADIFFAREA 0.870000 ;
    PORT
      LAYER met3 ;
        RECT 966.245 1635.345 967.015 1635.645 ;
    END
  END array_col_top_right<47>
  PIN array_col_top_right<45>
    ANTENNADIFFAREA 0.870000 ;
    PORT
      LAYER met3 ;
        RECT 990.245 1635.345 991.015 1635.645 ;
    END
  END array_col_top_right<45>
  PIN array_col_top_right<44>
    ANTENNADIFFAREA 0.870000 ;
    PORT
      LAYER met3 ;
        RECT 1006.365 1635.345 1007.135 1635.645 ;
    END
  END array_col_top_right<44>
  PIN array_col_top_right<41>
    ANTENNADIFFAREA 0.870000 ;
    PORT
      LAYER met3 ;
        RECT 1038.245 1635.345 1039.015 1635.645 ;
    END
  END array_col_top_right<41>
  PIN array_col_top_right<40>
    ANTENNADIFFAREA 0.870000 ;
    PORT
      LAYER met3 ;
        RECT 1054.365 1635.345 1055.135 1635.645 ;
    END
  END array_col_top_right<40>
  PIN row_on_detect_bot<11>
    ANTENNAGATEAREA 16.128000 ;
    PORT
      LAYER met3 ;
        RECT 0.000 686.650 0.300 686.950 ;
    END
  END row_on_detect_bot<11>
  PIN array_col_top_right<39>
    ANTENNADIFFAREA 0.870000 ;
    PORT
      LAYER met3 ;
        RECT 1062.245 1635.345 1063.015 1635.645 ;
    END
  END array_col_top_right<39>
  PIN row_on_detect_bot<56>
    ANTENNAGATEAREA 16.128000 ;
    PORT
      LAYER met3 ;
        RECT 0.000 135.850 0.300 136.150 ;
    END
  END row_on_detect_bot<56>
  PIN row_off_detect_bot<3>
    ANTENNAGATEAREA 8.064000 ;
    PORT
      LAYER met3 ;
        RECT 0.000 781.170 0.300 781.470 ;
    END
  END row_off_detect_bot<3>
  PIN row_on_detect_top<63>
    ANTENNAGATEAREA 16.128000 ;
    PORT
      LAYER met3 ;
        RECT 0.000 830.810 0.300 831.110 ;
    END
  END row_on_detect_top<63>
  PIN row_on_detect_top<44>
    ANTENNAGATEAREA 16.128000 ;
    PORT
      LAYER met3 ;
        RECT 0.000 1047.730 0.300 1048.030 ;
    END
  END row_on_detect_top<44>
  PIN row_on_detect_top<45>
    ANTENNAGATEAREA 16.128000 ;
    PORT
      LAYER met3 ;
        RECT 0.000 1046.370 0.300 1046.670 ;
    END
  END row_on_detect_top<45>
  PIN row_on_detect_bot<61>
    ANTENNAGATEAREA 16.128000 ;
    PORT
      LAYER met3 ;
        RECT 0.000 86.890 0.300 87.190 ;
    END
  END row_on_detect_bot<61>
  PIN row_off_detect_bot<61>
    ANTENNAGATEAREA 8.064000 ;
    PORT
      LAYER met3 ;
        RECT 0.000 85.530 0.300 85.830 ;
    END
  END row_off_detect_bot<61>
  PIN array_col_top_left<18>
    ANTENNADIFFAREA 0.870000 ;
    PORT
      LAYER met3 ;
        RECT 550.365 1635.345 551.135 1635.645 ;
    END
  END array_col_top_left<18>
  PIN array_col_bot_left<62>
    ANTENNADIFFAREA 0.870000 ;
    PORT
      LAYER met3 ;
        RECT 22.365 1.460 23.135 1.760 ;
    END
  END array_col_bot_left<62>
  PIN array_col_bot_left<15>
    ANTENNADIFFAREA 0.870000 ;
    PORT
      LAYER met3 ;
        RECT 582.245 1.460 583.015 1.760 ;
    END
  END array_col_bot_left<15>
  PIN array_col_bot_left<14>
    ANTENNADIFFAREA 0.870000 ;
    PORT
      LAYER met3 ;
        RECT 598.365 1.460 599.135 1.760 ;
    END
  END array_col_bot_left<14>
  PIN array_col_bot_left<5>
    ANTENNADIFFAREA 0.870000 ;
    PORT
      LAYER met3 ;
        RECT 702.245 1.460 703.015 1.760 ;
    END
  END array_col_bot_left<5>
  PIN col_event_rst_top_left<47>
    ANTENNAGATEAREA 4.032000 ;
    PORT
      LAYER met3 ;
        RECT 195.500 1635.225 195.800 1635.525 ;
    END
  END col_event_rst_top_left<47>
  PIN array_col_top_left<24>
    ANTENNADIFFAREA 0.870000 ;
    PORT
      LAYER met3 ;
        RECT 478.365 1635.345 479.135 1635.645 ;
    END
  END array_col_top_left<24>
  PIN array_col_bot_left<4>
    ANTENNADIFFAREA 0.870000 ;
    PORT
      LAYER met3 ;
        RECT 718.365 1.460 719.135 1.760 ;
    END
  END array_col_bot_left<4>
  PIN array_col_bot_right<13>
    ANTENNADIFFAREA 0.870000 ;
    PORT
      LAYER met3 ;
        RECT 1374.245 1.460 1375.015 1.760 ;
    END
  END array_col_bot_right<13>
  PIN array_col_top_right<1>
    ANTENNADIFFAREA 0.870000 ;
    PORT
      LAYER met3 ;
        RECT 1518.245 1635.345 1519.015 1635.645 ;
    END
  END array_col_top_right<1>
  PIN array_col_top_right<0>
    ANTENNADIFFAREA 0.870000 ;
    PORT
      LAYER met3 ;
        RECT 1534.365 1635.345 1535.135 1635.645 ;
    END
  END array_col_top_right<0>
  PIN col_event_rst_top_left<29>
    ANTENNAGATEAREA 4.032000 ;
    PORT
      LAYER met3 ;
        RECT 411.500 1635.225 411.800 1635.525 ;
    END
  END col_event_rst_top_left<29>
  PIN col_event_rst_top_left<25>
    ANTENNAGATEAREA 4.032000 ;
    PORT
      LAYER met3 ;
        RECT 459.500 1635.225 459.800 1635.525 ;
    END
  END col_event_rst_top_left<25>
  PIN col_event_rst_top_left<23>
    ANTENNAGATEAREA 4.032000 ;
    PORT
      LAYER met3 ;
        RECT 483.500 1635.225 483.800 1635.525 ;
    END
  END col_event_rst_top_left<23>
  PIN col_event_rst_top_left<18>
    ANTENNAGATEAREA 4.032000 ;
    PORT
      LAYER met3 ;
        RECT 553.595 1635.225 553.895 1635.525 ;
    END
  END col_event_rst_top_left<18>
  PIN col_event_rst_top_left<17>
    ANTENNAGATEAREA 4.032000 ;
    PORT
      LAYER met3 ;
        RECT 555.500 1635.225 555.800 1635.525 ;
    END
  END col_event_rst_top_left<17>
  PIN col_event_rst_top_left<14>
    ANTENNAGATEAREA 4.032000 ;
    PORT
      LAYER met3 ;
        RECT 601.595 1635.225 601.895 1635.525 ;
    END
  END col_event_rst_top_left<14>
  PIN array_col_bot_left<30>
    ANTENNADIFFAREA 0.870000 ;
    PORT
      LAYER met3 ;
        RECT 406.365 1.460 407.135 1.760 ;
    END
  END array_col_bot_left<30>
  PIN array_col_bot_left<33>
    ANTENNADIFFAREA 0.870000 ;
    PORT
      LAYER met3 ;
        RECT 366.245 1.460 367.015 1.760 ;
    END
  END array_col_bot_left<33>
  PIN array_col_top_left<20>
    ANTENNADIFFAREA 0.870000 ;
    PORT
      LAYER met3 ;
        RECT 526.365 1635.345 527.135 1635.645 ;
    END
  END array_col_top_left<20>
  PIN array_col_bot_left<26>
    ANTENNADIFFAREA 0.870000 ;
    PORT
      LAYER met3 ;
        RECT 454.365 1.460 455.135 1.760 ;
    END
  END array_col_bot_left<26>
  PIN array_col_bot_left<58>
    ANTENNADIFFAREA 0.870000 ;
    PORT
      LAYER met3 ;
        RECT 70.365 1.460 71.135 1.760 ;
    END
  END array_col_bot_left<58>
  PIN col_event_rst_top_left<39>
    ANTENNAGATEAREA 4.032000 ;
    PORT
      LAYER met3 ;
        RECT 291.500 1635.225 291.800 1635.525 ;
    END
  END col_event_rst_top_left<39>
  PIN col_event_rst_top_left<26>
    ANTENNAGATEAREA 4.032000 ;
    PORT
      LAYER met3 ;
        RECT 457.595 1635.225 457.895 1635.525 ;
    END
  END col_event_rst_top_left<26>
  PIN array_col_bot_left<2>
    ANTENNADIFFAREA 0.870000 ;
    PORT
      LAYER met3 ;
        RECT 742.365 1.460 743.135 1.760 ;
    END
  END array_col_bot_left<2>
  PIN array_col_bot_left<3>
    ANTENNADIFFAREA 0.870000 ;
    PORT
      LAYER met3 ;
        RECT 726.245 1.460 727.015 1.760 ;
    END
  END array_col_bot_left<3>
  PIN col_event_rst_top_left<40>
    ANTENNAGATEAREA 4.032000 ;
    PORT
      LAYER met3 ;
        RECT 289.595 1635.225 289.895 1635.525 ;
    END
  END col_event_rst_top_left<40>
  PIN col_event_rst_top_left<30>
    ANTENNAGATEAREA 4.032000 ;
    PORT
      LAYER met3 ;
        RECT 409.595 1635.225 409.895 1635.525 ;
    END
  END col_event_rst_top_left<30>
  PIN array_col_bot_right<29>
    ANTENNADIFFAREA 0.870000 ;
    PORT
      LAYER met3 ;
        RECT 1182.245 1.460 1183.015 1.760 ;
    END
  END array_col_bot_right<29>
  PIN array_col_bot_right<28>
    ANTENNADIFFAREA 0.870000 ;
    PORT
      LAYER met3 ;
        RECT 1198.365 1.460 1199.135 1.760 ;
    END
  END array_col_bot_right<28>
  PIN col_event_rst_top_right<57>
    ANTENNAGATEAREA 4.032000 ;
    PORT
      LAYER met3 ;
        RECT 843.500 1635.225 843.800 1635.525 ;
    END
  END col_event_rst_top_right<57>
  PIN col_event_rst_top_right<54>
    ANTENNAGATEAREA 4.032000 ;
    PORT
      LAYER met3 ;
        RECT 889.595 1635.225 889.895 1635.525 ;
    END
  END col_event_rst_top_right<54>
  PIN col_event_rst_top_right<53>
    ANTENNAGATEAREA 4.032000 ;
    PORT
      LAYER met3 ;
        RECT 891.500 1635.225 891.800 1635.525 ;
    END
  END col_event_rst_top_right<53>
  PIN col_event_rst_top_right<50>
    ANTENNAGATEAREA 4.032000 ;
    PORT
      LAYER met3 ;
        RECT 937.595 1635.225 937.895 1635.525 ;
    END
  END col_event_rst_top_right<50>
  PIN col_event_rst_top_right<49>
    ANTENNAGATEAREA 4.032000 ;
    PORT
      LAYER met3 ;
        RECT 939.500 1635.225 939.800 1635.525 ;
    END
  END col_event_rst_top_right<49>
  PIN col_event_rst_top_right<46>
    ANTENNAGATEAREA 4.032000 ;
    PORT
      LAYER met3 ;
        RECT 985.595 1635.225 985.895 1635.525 ;
    END
  END col_event_rst_top_right<46>
  PIN col_event_rst_top_right<45>
    ANTENNAGATEAREA 4.032000 ;
    PORT
      LAYER met3 ;
        RECT 987.500 1635.225 987.800 1635.525 ;
    END
  END col_event_rst_top_right<45>
  PIN col_event_rst_top_right<42>
    ANTENNAGATEAREA 4.032000 ;
    PORT
      LAYER met3 ;
        RECT 1033.595 1635.225 1033.895 1635.525 ;
    END
  END col_event_rst_top_right<42>
  PIN row_on_detect_bot<44>
    ANTENNAGATEAREA 16.128000 ;
    PORT
      LAYER met3 ;
        RECT 0.000 279.330 0.300 279.630 ;
    END
  END row_on_detect_bot<44>
  PIN row_on_detect_bot<45>
    ANTENNAGATEAREA 16.128000 ;
    PORT
      LAYER met3 ;
        RECT 0.000 278.650 0.300 278.950 ;
    END
  END row_on_detect_bot<45>
  PIN col_event_rst_top_right<41>
    ANTENNAGATEAREA 4.032000 ;
    PORT
      LAYER met3 ;
        RECT 1035.500 1635.225 1035.800 1635.525 ;
    END
  END col_event_rst_top_right<41>
  PIN row_on_detect_bot<52>
    ANTENNAGATEAREA 16.128000 ;
    PORT
      LAYER met3 ;
        RECT 0.000 183.450 0.300 183.750 ;
    END
  END row_on_detect_bot<52>
  PIN row_on_detect_bot<53>
    ANTENNAGATEAREA 16.128000 ;
    PORT
      LAYER met3 ;
        RECT 0.000 182.090 0.300 182.390 ;
    END
  END row_on_detect_bot<53>
  PIN row_off_detect_bot<41>
    ANTENNAGATEAREA 8.064000 ;
    PORT
      LAYER met3 ;
        RECT 0.000 325.570 0.300 325.870 ;
    END
  END row_off_detect_bot<41>
  PIN row_off_detect_bot<42>
    ANTENNAGATEAREA 8.064000 ;
    PORT
      LAYER met3 ;
        RECT 0.000 304.490 0.300 304.790 ;
    END
  END row_off_detect_bot<42>
  PIN row_on_detect_bot<42>
    ANTENNAGATEAREA 16.128000 ;
    PORT
      LAYER met3 ;
        RECT 0.000 303.810 0.300 304.110 ;
    END
  END row_on_detect_bot<42>
  PIN row_on_detect_bot<43>
    ANTENNAGATEAREA 16.128000 ;
    PORT
      LAYER met3 ;
        RECT 0.000 302.450 0.300 302.750 ;
    END
  END row_on_detect_bot<43>
  PIN row_off_detect_bot<45>
    ANTENNAGATEAREA 8.064000 ;
    PORT
      LAYER met3 ;
        RECT 0.000 277.290 0.300 277.590 ;
    END
  END row_off_detect_bot<45>
  PIN row_off_detect_bot<47>
    ANTENNAGATEAREA 8.064000 ;
    PORT
      LAYER met3 ;
        RECT 0.000 253.490 0.300 253.790 ;
    END
  END row_off_detect_bot<47>
  PIN row_on_detect_top<40>
    ANTENNAGATEAREA 16.128000 ;
    PORT
      LAYER met3 ;
        RECT 0.000 1095.330 0.300 1095.630 ;
    END
  END row_on_detect_top<40>
  PIN row_off_detect_top<39>
    ANTENNAGATEAREA 8.064000 ;
    PORT
      LAYER met3 ;
        RECT 0.000 1117.090 0.300 1117.390 ;
    END
  END row_off_detect_top<39>
  PIN row_on_detect_top<57>
    ANTENNAGATEAREA 16.128000 ;
    PORT
      LAYER met3 ;
        RECT 0.000 902.890 0.300 903.190 ;
    END
  END row_on_detect_top<57>
  PIN row_off_detect_top<54>
    ANTENNAGATEAREA 8.064000 ;
    PORT
      LAYER met3 ;
        RECT 0.000 928.730 0.300 929.030 ;
    END
  END row_off_detect_top<54>
  PIN row_on_detect_top<54>
    ANTENNAGATEAREA 16.128000 ;
    PORT
      LAYER met3 ;
        RECT 0.000 928.050 0.300 928.350 ;
    END
  END row_on_detect_top<54>
  PIN row_off_detect_top<50>
    ANTENNAGATEAREA 8.064000 ;
    PORT
      LAYER met3 ;
        RECT 0.000 977.010 0.300 977.310 ;
    END
  END row_off_detect_top<50>
  PIN row_on_detect_top<48>
    ANTENNAGATEAREA 16.128000 ;
    PORT
      LAYER met3 ;
        RECT 0.000 999.450 0.300 999.750 ;
    END
  END row_on_detect_top<48>
  PIN row_on_detect_top<46>
    ANTENNAGATEAREA 16.128000 ;
    PORT
      LAYER met3 ;
        RECT 0.000 1023.250 0.300 1023.550 ;
    END
  END row_on_detect_top<46>
  PIN row_on_detect_top<43>
    ANTENNAGATEAREA 16.128000 ;
    PORT
      LAYER met3 ;
        RECT 0.000 1070.850 0.300 1071.150 ;
    END
  END row_on_detect_top<43>
  PIN row_off_detect_top<42>
    ANTENNAGATEAREA 8.064000 ;
    PORT
      LAYER met3 ;
        RECT 0.000 1072.890 0.300 1073.190 ;
    END
  END row_off_detect_top<42>
  PIN row_off_detect_top<41>
    ANTENNAGATEAREA 8.064000 ;
    PORT
      LAYER met3 ;
        RECT 0.000 1093.290 0.300 1093.590 ;
    END
  END row_off_detect_top<41>
  PIN row_off_detect_top<51>
    ANTENNAGATEAREA 8.064000 ;
    PORT
      LAYER met3 ;
        RECT 0.000 973.610 0.300 973.910 ;
    END
  END row_off_detect_top<51>
  PIN row_on_detect_top<51>
    ANTENNAGATEAREA 16.128000 ;
    PORT
      LAYER met3 ;
        RECT 0.000 974.290 0.300 974.590 ;
    END
  END row_on_detect_top<51>
  PIN row_on_detect_top<37>
    ANTENNAGATEAREA 16.128000 ;
    PORT
      LAYER met3 ;
        RECT 0.000 1142.930 0.300 1143.230 ;
    END
  END row_on_detect_top<37>
  PIN row_off_detect_top<36>
    ANTENNAGATEAREA 8.064000 ;
    PORT
      LAYER met3 ;
        RECT 0.000 1144.970 0.300 1145.270 ;
    END
  END row_off_detect_top<36>
  PIN array_col_top_left<29>
    ANTENNADIFFAREA 0.870000 ;
    PORT
      LAYER met3 ;
        RECT 414.245 1635.345 415.015 1635.645 ;
    END
  END array_col_top_left<29>
  PIN row_on_detect_top<32>
    ANTENNAGATEAREA 16.128000 ;
    PORT
      LAYER met3 ;
        RECT 0.000 1191.210 0.300 1191.510 ;
    END
  END row_on_detect_top<32>
  PIN row_off_detect_top<33>
    ANTENNAGATEAREA 8.064000 ;
    PORT
      LAYER met3 ;
        RECT 0.000 1189.170 0.300 1189.470 ;
    END
  END row_off_detect_top<33>
  PIN row_on_detect_top<26>
    ANTENNAGATEAREA 16.128000 ;
    PORT
      LAYER met3 ;
        RECT 0.000 1263.290 0.300 1263.590 ;
    END
  END row_on_detect_top<26>
  PIN row_off_detect_top<56>
    ANTENNAGATEAREA 8.064000 ;
    PORT
      LAYER met3 ;
        RECT 0.000 904.930 0.300 905.230 ;
    END
  END row_off_detect_top<56>
  PIN row_off_detect_bot<6>
    ANTENNAGATEAREA 8.064000 ;
    PORT
      LAYER met3 ;
        RECT 0.000 736.970 0.300 737.270 ;
    END
  END row_off_detect_bot<6>
  PIN row_off_detect_bot<5>
    ANTENNAGATEAREA 8.064000 ;
    PORT
      LAYER met3 ;
        RECT 0.000 757.370 0.300 757.670 ;
    END
  END row_off_detect_bot<5>
  PIN array_col_bot_right<25>
    ANTENNADIFFAREA 0.870000 ;
    PORT
      LAYER met3 ;
        RECT 1230.245 1.460 1231.015 1.760 ;
    END
  END array_col_bot_right<25>
  PIN array_col_bot_left<54>
    ANTENNADIFFAREA 0.870000 ;
    PORT
      LAYER met3 ;
        RECT 118.365 1.460 119.135 1.760 ;
    END
  END array_col_bot_left<54>
  PIN array_col_bot_right<24>
    ANTENNADIFFAREA 0.870000 ;
    PORT
      LAYER met3 ;
        RECT 1246.365 1.460 1247.135 1.760 ;
    END
  END array_col_bot_right<24>
  PIN array_col_bot_right<21>
    ANTENNADIFFAREA 0.870000 ;
    PORT
      LAYER met3 ;
        RECT 1278.245 1.460 1279.015 1.760 ;
    END
  END array_col_bot_right<21>
  PIN array_col_bot_right<20>
    ANTENNADIFFAREA 0.870000 ;
    PORT
      LAYER met3 ;
        RECT 1294.365 1.460 1295.135 1.760 ;
    END
  END array_col_bot_right<20>
  PIN row_on_detect_bot<30>
    ANTENNAGATEAREA 16.128000 ;
    PORT
      LAYER met3 ;
        RECT 0.000 447.290 0.300 447.590 ;
    END
  END row_on_detect_bot<30>
  PIN row_on_detect_bot<31>
    ANTENNAGATEAREA 16.128000 ;
    PORT
      LAYER met3 ;
        RECT 0.000 446.610 0.300 446.910 ;
    END
  END row_on_detect_bot<31>
  PIN row_off_detect_bot<31>
    ANTENNAGATEAREA 8.064000 ;
    PORT
      LAYER met3 ;
        RECT 0.000 445.250 0.300 445.550 ;
    END
  END row_off_detect_bot<31>
  PIN row_off_detect_bot<32>
    ANTENNAGATEAREA 8.064000 ;
    PORT
      LAYER met3 ;
        RECT 0.000 424.850 0.300 425.150 ;
    END
  END row_off_detect_bot<32>
  PIN array_col_bot_right<7>
    ANTENNADIFFAREA 0.870000 ;
    PORT
      LAYER met3 ;
        RECT 1446.245 1.460 1447.015 1.760 ;
    END
  END array_col_bot_right<7>
  PIN col_event_rst_top_left<43>
    ANTENNAGATEAREA 4.032000 ;
    PORT
      LAYER met3 ;
        RECT 243.500 1635.225 243.800 1635.525 ;
    END
  END col_event_rst_top_left<43>
  PIN row_off_detect_top<18>
    ANTENNAGATEAREA 8.064000 ;
    PORT
      LAYER met3 ;
        RECT 0.000 1360.530 0.300 1360.830 ;
    END
  END row_off_detect_top<18>
  PIN row_off_detect_top<17>
    ANTENNAGATEAREA 8.064000 ;
    PORT
      LAYER met3 ;
        RECT 0.000 1381.610 0.300 1381.910 ;
    END
  END row_off_detect_top<17>
  PIN array_col_top_left<7>
    ANTENNADIFFAREA 0.870000 ;
    PORT
      LAYER met3 ;
        RECT 678.245 1635.345 679.015 1635.645 ;
    END
  END array_col_top_left<7>
  PIN row_off_detect_top<23>
    ANTENNAGATEAREA 8.064000 ;
    PORT
      LAYER met3 ;
        RECT 0.000 1309.530 0.300 1309.830 ;
    END
  END row_off_detect_top<23>
  PIN array_col_bot_right<12>
    ANTENNADIFFAREA 0.870000 ;
    PORT
      LAYER met3 ;
        RECT 1390.365 1.460 1391.135 1.760 ;
    END
  END array_col_bot_right<12>
  PIN array_col_bot_left<53>
    ANTENNADIFFAREA 0.870000 ;
    PORT
      LAYER met3 ;
        RECT 126.245 1.460 127.015 1.760 ;
    END
  END array_col_bot_left<53>
  PIN array_col_bot_left<50>
    ANTENNADIFFAREA 0.870000 ;
    PORT
      LAYER met3 ;
        RECT 166.365 1.460 167.135 1.760 ;
    END
  END array_col_bot_left<50>
  PIN array_col_bot_right<61>
    ANTENNADIFFAREA 0.870000 ;
    PORT
      LAYER met3 ;
        RECT 798.245 1.460 799.015 1.760 ;
    END
  END array_col_bot_right<61>
  PIN col_event_rst_top_left<59>
    ANTENNAGATEAREA 4.032000 ;
    PORT
      LAYER met3 ;
        RECT 51.500 1635.225 51.800 1635.525 ;
    END
  END col_event_rst_top_left<59>
  PIN array_col_bot_right<60>
    ANTENNADIFFAREA 0.870000 ;
    PORT
      LAYER met3 ;
        RECT 814.365 1.460 815.135 1.760 ;
    END
  END array_col_bot_right<60>
  PIN array_col_bot_right<57>
    ANTENNADIFFAREA 0.870000 ;
    PORT
      LAYER met3 ;
        RECT 846.245 1.460 847.015 1.760 ;
    END
  END array_col_bot_right<57>
  PIN array_col_bot_right<56>
    ANTENNADIFFAREA 0.870000 ;
    PORT
      LAYER met3 ;
        RECT 862.365 1.460 863.135 1.760 ;
    END
  END array_col_bot_right<56>
  PIN array_col_bot_right<53>
    ANTENNADIFFAREA 0.870000 ;
    PORT
      LAYER met3 ;
        RECT 894.245 1.460 895.015 1.760 ;
    END
  END array_col_bot_right<53>
  PIN array_col_bot_right<52>
    ANTENNADIFFAREA 0.870000 ;
    PORT
      LAYER met3 ;
        RECT 910.365 1.460 911.135 1.760 ;
    END
  END array_col_bot_right<52>
  PIN array_col_bot_right<49>
    ANTENNADIFFAREA 0.870000 ;
    PORT
      LAYER met3 ;
        RECT 942.245 1.460 943.015 1.760 ;
    END
  END array_col_bot_right<49>
  PIN array_col_bot_right<48>
    ANTENNADIFFAREA 0.870000 ;
    PORT
      LAYER met3 ;
        RECT 958.365 1.460 959.135 1.760 ;
    END
  END array_col_bot_right<48>
  PIN row_off_detect_top<4>
    ANTENNAGATEAREA 8.064000 ;
    PORT
      LAYER met3 ;
        RECT 0.000 1528.490 0.300 1528.790 ;
    END
  END row_off_detect_top<4>
  PIN row_off_detect_top<3>
    ANTENNAGATEAREA 8.064000 ;
    PORT
      LAYER met3 ;
        RECT 0.000 1549.570 0.300 1549.870 ;
    END
  END row_off_detect_top<3>
  PIN array_col_bot_right<45>
    ANTENNADIFFAREA 0.870000 ;
    PORT
      LAYER met3 ;
        RECT 990.245 1.460 991.015 1.760 ;
    END
  END array_col_bot_right<45>
  PIN array_col_bot_right<44>
    ANTENNADIFFAREA 0.870000 ;
    PORT
      LAYER met3 ;
        RECT 1006.365 1.460 1007.135 1.760 ;
    END
  END array_col_bot_right<44>
  PIN col_event_rst_top_left<58>
    ANTENNAGATEAREA 4.032000 ;
    PORT
      LAYER met3 ;
        RECT 73.595 1635.225 73.895 1635.525 ;
    END
  END col_event_rst_top_left<58>
  PIN array_col_bot_right<41>
    ANTENNADIFFAREA 0.870000 ;
    PORT
      LAYER met3 ;
        RECT 1038.245 1.460 1039.015 1.760 ;
    END
  END array_col_bot_right<41>
  PIN array_col_bot_right<40>
    ANTENNADIFFAREA 0.870000 ;
    PORT
      LAYER met3 ;
        RECT 1054.365 1.460 1055.135 1.760 ;
    END
  END array_col_bot_right<40>
  PIN array_col_bot_right<37>
    ANTENNADIFFAREA 0.870000 ;
    PORT
      LAYER met3 ;
        RECT 1086.245 1.460 1087.015 1.760 ;
    END
  END array_col_bot_right<37>
  PIN array_col_bot_right<36>
    ANTENNADIFFAREA 0.870000 ;
    PORT
      LAYER met3 ;
        RECT 1102.365 1.460 1103.135 1.760 ;
    END
  END array_col_bot_right<36>
  PIN array_col_bot_right<33>
    ANTENNADIFFAREA 0.870000 ;
    PORT
      LAYER met3 ;
        RECT 1134.245 1.460 1135.015 1.760 ;
    END
  END array_col_bot_right<33>
  PIN array_col_bot_right<32>
    ANTENNADIFFAREA 0.870000 ;
    PORT
      LAYER met3 ;
        RECT 1150.365 1.460 1151.135 1.760 ;
    END
  END array_col_bot_right<32>
  PIN array_col_bot_left<10>
    ANTENNADIFFAREA 0.870000 ;
    PORT
      LAYER met3 ;
        RECT 646.365 1.460 647.135 1.760 ;
    END
  END array_col_bot_left<10>
  PIN array_col_bot_left<11>
    ANTENNADIFFAREA 0.870000 ;
    PORT
      LAYER met3 ;
        RECT 630.245 1.460 631.015 1.760 ;
    END
  END array_col_bot_left<11>
  PIN array_col_bot_left<6>
    ANTENNADIFFAREA 0.870000 ;
    PORT
      LAYER met3 ;
        RECT 694.365 1.460 695.135 1.760 ;
    END
  END array_col_bot_left<6>
  PIN col_event_rst_top_left<54>
    ANTENNAGATEAREA 4.032000 ;
    PORT
      LAYER met3 ;
        RECT 121.595 1635.225 121.895 1635.525 ;
    END
  END col_event_rst_top_left<54>
  PIN col_event_rst_top_left<55>
    ANTENNAGATEAREA 4.032000 ;
    PORT
      LAYER met3 ;
        RECT 99.500 1635.225 99.800 1635.525 ;
    END
  END col_event_rst_top_left<55>
  PIN col_event_rst_top_left<22>
    ANTENNAGATEAREA 4.032000 ;
    PORT
      LAYER met3 ;
        RECT 505.595 1635.225 505.895 1635.525 ;
    END
  END col_event_rst_top_left<22>
  PIN col_event_rst_top_left<13>
    ANTENNAGATEAREA 4.032000 ;
    PORT
      LAYER met3 ;
        RECT 603.500 1635.225 603.800 1635.525 ;
    END
  END col_event_rst_top_left<13>
  PIN array_col_bot_left<37>
    ANTENNADIFFAREA 0.870000 ;
    PORT
      LAYER met3 ;
        RECT 318.245 1.460 319.015 1.760 ;
    END
  END array_col_bot_left<37>
  PIN array_col_bot_left<36>
    ANTENNADIFFAREA 0.870000 ;
    PORT
      LAYER met3 ;
        RECT 334.365 1.460 335.135 1.760 ;
    END
  END array_col_bot_left<36>
  PIN array_col_bot_left<29>
    ANTENNADIFFAREA 0.870000 ;
    PORT
      LAYER met3 ;
        RECT 414.245 1.460 415.015 1.760 ;
    END
  END array_col_bot_left<29>
  PIN array_col_bot_left<28>
    ANTENNADIFFAREA 0.870000 ;
    PORT
      LAYER met3 ;
        RECT 430.365 1.460 431.135 1.760 ;
    END
  END array_col_bot_left<28>
  PIN array_col_bot_left<24>
    ANTENNADIFFAREA 0.870000 ;
    PORT
      LAYER met3 ;
        RECT 478.365 1.460 479.135 1.760 ;
    END
  END array_col_bot_left<24>
  PIN array_col_bot_left<19>
    ANTENNADIFFAREA 0.870000 ;
    PORT
      LAYER met3 ;
        RECT 534.245 1.460 535.015 1.760 ;
    END
  END array_col_bot_left<19>
  PIN row_off_detect_top<59>
    ANTENNAGATEAREA 8.064000 ;
    PORT
      LAYER met3 ;
        RECT 0.000 877.730 0.300 878.030 ;
    END
  END row_off_detect_top<59>
  PIN col_event_rst_top_left<52>
    ANTENNAGATEAREA 4.032000 ;
    PORT
      LAYER met3 ;
        RECT 145.595 1635.225 145.895 1635.525 ;
    END
  END col_event_rst_top_left<52>
  PIN array_col_bot_left<61>
    ANTENNADIFFAREA 0.870000 ;
    PORT
      LAYER met3 ;
        RECT 30.245 1.460 31.015 1.760 ;
    END
  END array_col_bot_left<61>
  PIN array_col_bot_left<57>
    ANTENNADIFFAREA 0.870000 ;
    PORT
      LAYER met3 ;
        RECT 78.245 1.460 79.015 1.760 ;
    END
  END array_col_bot_left<57>
  PIN array_col_bot_left<56>
    ANTENNADIFFAREA 0.870000 ;
    PORT
      LAYER met3 ;
        RECT 94.365 1.460 95.135 1.760 ;
    END
  END array_col_bot_left<56>
  PIN array_col_bot_left<52>
    ANTENNADIFFAREA 0.870000 ;
    PORT
      LAYER met3 ;
        RECT 142.365 1.460 143.135 1.760 ;
    END
  END array_col_bot_left<52>
  PIN array_col_bot_left<51>
    ANTENNADIFFAREA 0.870000 ;
    PORT
      LAYER met3 ;
        RECT 150.245 1.460 151.015 1.760 ;
    END
  END array_col_bot_left<51>
  PIN array_col_bot_left<48>
    ANTENNADIFFAREA 0.870000 ;
    PORT
      LAYER met3 ;
        RECT 190.365 1.460 191.135 1.760 ;
    END
  END array_col_bot_left<48>
  PIN array_col_bot_left<47>
    ANTENNADIFFAREA 0.870000 ;
    PORT
      LAYER met3 ;
        RECT 198.245 1.460 199.015 1.760 ;
    END
  END array_col_bot_left<47>
  PIN array_col_bot_left<49>
    ANTENNADIFFAREA 0.870000 ;
    PORT
      LAYER met3 ;
        RECT 174.245 1.460 175.015 1.760 ;
    END
  END array_col_bot_left<49>
  PIN array_col_bot_left<46>
    ANTENNADIFFAREA 0.870000 ;
    PORT
      LAYER met3 ;
        RECT 214.365 1.460 215.135 1.760 ;
    END
  END array_col_bot_left<46>
  PIN col_event_rst_top_left<11>
    ANTENNAGATEAREA 4.032000 ;
    PORT
      LAYER met3 ;
        RECT 627.500 1635.225 627.800 1635.525 ;
    END
  END col_event_rst_top_left<11>
  PIN array_col_top_right<17>
    ANTENNADIFFAREA 0.870000 ;
    PORT
      LAYER met3 ;
        RECT 1326.245 1635.345 1327.015 1635.645 ;
    END
  END array_col_top_right<17>
  PIN array_col_bot_left<63>
    ANTENNADIFFAREA 0.870000 ;
    PORT
      LAYER met3 ;
        RECT 6.245 1.460 7.015 1.760 ;
    END
  END array_col_bot_left<63>
  PIN array_col_bot_right<51>
    ANTENNADIFFAREA 0.870000 ;
    PORT
      LAYER met3 ;
        RECT 918.245 1.460 919.015 1.760 ;
    END
  END array_col_bot_right<51>
  PIN array_col_bot_right<50>
    ANTENNADIFFAREA 0.870000 ;
    PORT
      LAYER met3 ;
        RECT 934.365 1.460 935.135 1.760 ;
    END
  END array_col_bot_right<50>
  PIN array_col_bot_right<47>
    ANTENNADIFFAREA 0.870000 ;
    PORT
      LAYER met3 ;
        RECT 966.245 1.460 967.015 1.760 ;
    END
  END array_col_bot_right<47>
  PIN array_col_bot_right<46>
    ANTENNADIFFAREA 0.870000 ;
    PORT
      LAYER met3 ;
        RECT 982.365 1.460 983.135 1.760 ;
    END
  END array_col_bot_right<46>
  PIN array_col_bot_right<43>
    ANTENNADIFFAREA 0.870000 ;
    PORT
      LAYER met3 ;
        RECT 1014.245 1.460 1015.015 1.760 ;
    END
  END array_col_bot_right<43>
  PIN array_col_bot_right<42>
    ANTENNADIFFAREA 0.870000 ;
    PORT
      LAYER met3 ;
        RECT 1030.365 1.460 1031.135 1.760 ;
    END
  END array_col_bot_right<42>
  PIN array_col_bot_right<39>
    ANTENNADIFFAREA 0.870000 ;
    PORT
      LAYER met3 ;
        RECT 1062.245 1.460 1063.015 1.760 ;
    END
  END array_col_bot_right<39>
  PIN array_col_bot_right<38>
    ANTENNADIFFAREA 0.870000 ;
    PORT
      LAYER met3 ;
        RECT 1078.365 1.460 1079.135 1.760 ;
    END
  END array_col_bot_right<38>
  PIN array_col_bot_right<35>
    ANTENNADIFFAREA 0.870000 ;
    PORT
      LAYER met3 ;
        RECT 1110.245 1.460 1111.015 1.760 ;
    END
  END array_col_bot_right<35>
  PIN array_col_bot_right<8>
    ANTENNADIFFAREA 0.870000 ;
    PORT
      LAYER met3 ;
        RECT 1438.365 1.460 1439.135 1.760 ;
    END
  END array_col_bot_right<8>
  PIN array_col_bot_right<34>
    ANTENNADIFFAREA 0.870000 ;
    PORT
      LAYER met3 ;
        RECT 1126.365 1.460 1127.135 1.760 ;
    END
  END array_col_bot_right<34>
  PIN array_col_top_right<32>
    ANTENNADIFFAREA 0.870000 ;
    PORT
      LAYER met3 ;
        RECT 1150.365 1635.345 1151.135 1635.645 ;
    END
  END array_col_top_right<32>
  PIN array_col_top_right<4>
    ANTENNADIFFAREA 0.870000 ;
    PORT
      LAYER met3 ;
        RECT 1486.365 1635.345 1487.135 1635.645 ;
    END
  END array_col_top_right<4>
  PIN array_col_top_left<62>
    ANTENNADIFFAREA 0.870000 ;
    PORT
      LAYER met3 ;
        RECT 22.365 1635.345 23.135 1635.645 ;
    END
  END array_col_top_left<62>
  PIN array_col_top_left<0>
    ANTENNADIFFAREA 0.870000 ;
    PORT
      LAYER met3 ;
        RECT 766.365 1635.345 767.135 1635.645 ;
    END
  END array_col_top_left<0>
  PIN row_off_detect_bot<43>
    ANTENNAGATEAREA 8.064000 ;
    PORT
      LAYER met3 ;
        RECT 0.000 301.090 0.300 301.390 ;
    END
  END row_off_detect_bot<43>
  PIN row_off_detect_bot<44>
    ANTENNAGATEAREA 8.064000 ;
    PORT
      LAYER met3 ;
        RECT 0.000 280.690 0.300 280.990 ;
    END
  END row_off_detect_bot<44>
  PIN row_on_detect_bot<63>
    ANTENNAGATEAREA 16.128000 ;
    PORT
      LAYER met3 ;
        RECT 0.000 62.410 0.300 62.710 ;
    END
  END row_on_detect_bot<63>
  PIN row_off_detect_bot<63>
    ANTENNAGATEAREA 8.064000 ;
    PORT
      LAYER met3 ;
        RECT 0.000 61.730 0.300 62.030 ;
    END
  END row_off_detect_bot<63>
  PIN row_on_detect_top<33>
    ANTENNAGATEAREA 16.128000 ;
    PORT
      LAYER met3 ;
        RECT 0.000 1190.530 0.300 1190.830 ;
    END
  END row_on_detect_top<33>
  PIN row_off_detect_top<32>
    ANTENNAGATEAREA 8.064000 ;
    PORT
      LAYER met3 ;
        RECT 0.000 1192.570 0.300 1192.870 ;
    END
  END row_off_detect_top<32>
  PIN row_on_detect_top<0>
    ANTENNAGATEAREA 16.128000 ;
    PORT
      LAYER met3 ;
        RECT 0.000 1575.410 0.300 1575.710 ;
    END
  END row_on_detect_top<0>
  PIN row_on_detect_top<7>
    ANTENNAGATEAREA 16.128000 ;
    PORT
      LAYER met3 ;
        RECT 0.000 1502.650 0.300 1502.950 ;
    END
  END row_on_detect_top<7>
  PIN row_off_detect_top<6>
    ANTENNAGATEAREA 8.064000 ;
    PORT
      LAYER met3 ;
        RECT 0.000 1504.690 0.300 1504.990 ;
    END
  END row_off_detect_top<6>
  PIN row_off_detect_bot<46>
    ANTENNAGATEAREA 8.064000 ;
    PORT
      LAYER met3 ;
        RECT 0.000 256.890 0.300 257.190 ;
    END
  END row_off_detect_bot<46>
  PIN row_off_detect_bot<49>
    ANTENNAGATEAREA 8.064000 ;
    PORT
      LAYER met3 ;
        RECT 0.000 229.690 0.300 229.990 ;
    END
  END row_off_detect_bot<49>
  PIN dac_config_4
    ANTENNAGATEAREA 10321.919922 ;
    PORT
      LAYER met3 ;
        RECT 1559.700 820.610 1560.000 820.910 ;
    END
  END dac_config_4
  PIN row_on_detect_bot<54>
    ANTENNAGATEAREA 16.128000 ;
    PORT
      LAYER met3 ;
        RECT 0.000 159.650 0.300 159.950 ;
    END
  END row_on_detect_bot<54>
  PIN row_on_detect_bot<55>
    ANTENNAGATEAREA 16.128000 ;
    PORT
      LAYER met3 ;
        RECT 0.000 158.290 0.300 158.590 ;
    END
  END row_on_detect_bot<55>
  PIN array_col_bot_right<31>
    ANTENNADIFFAREA 0.870000 ;
    PORT
      LAYER met3 ;
        RECT 1158.245 1.460 1159.015 1.760 ;
    END
  END array_col_bot_right<31>
  PIN array_col_bot_right<30>
    ANTENNADIFFAREA 0.870000 ;
    PORT
      LAYER met3 ;
        RECT 1174.365 1.460 1175.135 1.760 ;
    END
  END array_col_bot_right<30>
  PIN array_col_bot_left<12>
    ANTENNADIFFAREA 0.870000 ;
    PORT
      LAYER met3 ;
        RECT 622.365 1.460 623.135 1.760 ;
    END
  END array_col_bot_left<12>
  PIN array_col_bot_left<13>
    ANTENNADIFFAREA 0.870000 ;
    PORT
      LAYER met3 ;
        RECT 606.245 1.460 607.015 1.760 ;
    END
  END array_col_bot_left<13>
  PIN col_event_rst_top_left<44>
    ANTENNAGATEAREA 4.032000 ;
    PORT
      LAYER met3 ;
        RECT 241.595 1635.225 241.895 1635.525 ;
    END
  END col_event_rst_top_left<44>
  PIN col_event_rst_top_left<33>
    ANTENNAGATEAREA 4.032000 ;
    PORT
      LAYER met3 ;
        RECT 363.500 1635.225 363.800 1635.525 ;
    END
  END col_event_rst_top_left<33>
  PIN array_col_bot_left<39>
    ANTENNADIFFAREA 0.870000 ;
    PORT
      LAYER met3 ;
        RECT 294.245 1.460 295.015 1.760 ;
    END
  END array_col_bot_left<39>
  PIN array_col_top_right<2>
    ANTENNADIFFAREA 0.870000 ;
    PORT
      LAYER met3 ;
        RECT 1510.365 1635.345 1511.135 1635.645 ;
    END
  END array_col_top_right<2>
  PIN array_col_bot_left<38>
    ANTENNADIFFAREA 0.870000 ;
    PORT
      LAYER met3 ;
        RECT 310.365 1.460 311.135 1.760 ;
    END
  END array_col_bot_left<38>
  PIN array_col_bot_left<35>
    ANTENNADIFFAREA 0.870000 ;
    PORT
      LAYER met3 ;
        RECT 342.245 1.460 343.015 1.760 ;
    END
  END array_col_bot_left<35>
  PIN array_col_bot_right<5>
    ANTENNADIFFAREA 0.870000 ;
    PORT
      LAYER met3 ;
        RECT 1470.245 1.460 1471.015 1.760 ;
    END
  END array_col_bot_right<5>
  PIN array_col_bot_left<34>
    ANTENNADIFFAREA 0.870000 ;
    PORT
      LAYER met3 ;
        RECT 358.365 1.460 359.135 1.760 ;
    END
  END array_col_bot_left<34>
  PIN array_col_bot_left<27>
    ANTENNADIFFAREA 0.870000 ;
    PORT
      LAYER met3 ;
        RECT 438.245 1.460 439.015 1.760 ;
    END
  END array_col_bot_left<27>
  PIN array_col_bot_left<25>
    ANTENNADIFFAREA 0.870000 ;
    PORT
      LAYER met3 ;
        RECT 462.245 1.460 463.015 1.760 ;
    END
  END array_col_bot_left<25>
  PIN array_col_bot_left<18>
    ANTENNADIFFAREA 0.870000 ;
    PORT
      LAYER met3 ;
        RECT 550.365 1.460 551.135 1.760 ;
    END
  END array_col_bot_left<18>
  PIN array_col_bot_left<17>
    ANTENNADIFFAREA 0.870000 ;
    PORT
      LAYER met3 ;
        RECT 558.245 1.460 559.015 1.760 ;
    END
  END array_col_bot_left<17>
  PIN array_col_bot_left<9>
    ANTENNADIFFAREA 0.870000 ;
    PORT
      LAYER met3 ;
        RECT 654.245 1.460 655.015 1.760 ;
    END
  END array_col_bot_left<9>
  PIN array_col_bot_right<63>
    ANTENNADIFFAREA 0.870000 ;
    PORT
      LAYER met3 ;
        RECT 774.245 1.460 775.015 1.760 ;
    END
  END array_col_bot_right<63>
  PIN array_col_bot_left<8>
    ANTENNADIFFAREA 0.870000 ;
    PORT
      LAYER met3 ;
        RECT 670.365 1.460 671.135 1.760 ;
    END
  END array_col_bot_left<8>
  PIN col_event_rst_top_left<63>
    ANTENNAGATEAREA 4.032000 ;
    PORT
      LAYER met3 ;
        RECT 3.500 1636.475 3.800 1636.775 ;
    END
  END col_event_rst_top_left<63>
  PIN row_off_detect_bot<62>
    ANTENNAGATEAREA 8.064000 ;
    PORT
      LAYER met3 ;
        RECT 0.000 64.450 0.300 64.750 ;
    END
  END row_off_detect_bot<62>
  PIN row_on_detect_bot<62>
    ANTENNAGATEAREA 16.128000 ;
    PORT
      LAYER met3 ;
        RECT 0.000 63.770 0.300 64.070 ;
    END
  END row_on_detect_bot<62>
  PIN array_col_top_right<5>
    ANTENNADIFFAREA 0.870000 ;
    PORT
      LAYER met3 ;
        RECT 1470.245 1635.345 1471.015 1635.645 ;
    END
  END array_col_top_right<5>
  PIN col_event_rst_top_left<42>
    ANTENNAGATEAREA 4.032000 ;
    PORT
      LAYER met3 ;
        RECT 265.595 1635.225 265.895 1635.525 ;
    END
  END col_event_rst_top_left<42>
  PIN col_event_rst_top_left<37>
    ANTENNAGATEAREA 4.032000 ;
    PORT
      LAYER met3 ;
        RECT 315.500 1635.225 315.800 1635.525 ;
    END
  END col_event_rst_top_left<37>
  PIN col_event_rst_top_left<35>
    ANTENNAGATEAREA 4.032000 ;
    PORT
      LAYER met3 ;
        RECT 339.500 1635.225 339.800 1635.525 ;
    END
  END col_event_rst_top_left<35>
  PIN col_event_rst_top_left<31>
    ANTENNAGATEAREA 4.032000 ;
    PORT
      LAYER met3 ;
        RECT 387.500 1635.225 387.800 1635.525 ;
    END
  END col_event_rst_top_left<31>
  PIN array_col_bot_left<59>
    ANTENNADIFFAREA 0.870000 ;
    PORT
      LAYER met3 ;
        RECT 54.245 1.460 55.015 1.760 ;
    END
  END array_col_bot_left<59>
  PIN array_col_top_left<36>
    ANTENNADIFFAREA 0.870000 ;
    PORT
      LAYER met3 ;
        RECT 334.365 1635.345 335.135 1635.645 ;
    END
  END array_col_top_left<36>
  PIN row_off_detect_top<0>
    ANTENNAGATEAREA 8.064000 ;
    PORT
      LAYER met3 ;
        RECT 0.000 1576.770 0.300 1577.070 ;
    END
  END row_off_detect_top<0>
  PIN col_event_rst_top_left<8>
    ANTENNAGATEAREA 4.032000 ;
    PORT
      LAYER met3 ;
        RECT 673.595 1635.225 673.895 1635.525 ;
    END
  END col_event_rst_top_left<8>
  PIN col_event_rst_top_right<31>
    ANTENNAGATEAREA 4.032000 ;
    PORT
      LAYER met3 ;
        RECT 1155.500 1635.225 1155.800 1635.525 ;
    END
  END col_event_rst_top_right<31>
  PIN col_event_rst_top_right<30>
    ANTENNAGATEAREA 4.032000 ;
    PORT
      LAYER met3 ;
        RECT 1177.595 1635.225 1177.895 1635.525 ;
    END
  END col_event_rst_top_right<30>
  PIN col_event_rst_top_right<29>
    ANTENNAGATEAREA 4.032000 ;
    PORT
      LAYER met3 ;
        RECT 1179.500 1635.225 1179.800 1635.525 ;
    END
  END col_event_rst_top_right<29>
  PIN col_event_rst_top_right<28>
    ANTENNAGATEAREA 4.032000 ;
    PORT
      LAYER met3 ;
        RECT 1201.595 1635.225 1201.895 1635.525 ;
    END
  END col_event_rst_top_right<28>
  OBS
      LAYER nwell ;
        RECT -0.940 -0.005 1542.320 1638.445 ;
      LAYER li1 ;
        RECT -0.605 0.125 1541.985 1638.315 ;
      LAYER met1 ;
        RECT -0.665 0.065 1542.950 1638.375 ;
      LAYER met2 ;
        RECT 0.765 0.295 1560.000 1638.230 ;
      LAYER met3 ;
        RECT 0.000 1638.630 1560.000 1696.750 ;
        RECT 0.000 1637.530 1538.850 1638.630 ;
        RECT 1543.350 1637.530 1560.000 1638.630 ;
        RECT 0.000 1637.175 1560.000 1637.530 ;
        RECT 0.000 1636.075 3.100 1637.175 ;
        RECT 4.200 1636.075 771.100 1637.175 ;
        RECT 772.200 1636.075 1560.000 1637.175 ;
        RECT 0.000 1636.045 1560.000 1636.075 ;
        RECT 0.000 1634.945 5.845 1636.045 ;
        RECT 7.415 1634.945 21.965 1636.045 ;
        RECT 23.535 1635.925 29.845 1636.045 ;
        RECT 23.535 1634.945 25.195 1635.925 ;
        RECT 0.000 1634.825 25.195 1634.945 ;
        RECT 26.295 1634.825 27.100 1635.925 ;
        RECT 28.200 1634.945 29.845 1635.925 ;
        RECT 31.415 1634.945 45.965 1636.045 ;
        RECT 47.535 1635.925 53.845 1636.045 ;
        RECT 47.535 1634.945 49.195 1635.925 ;
        RECT 28.200 1634.825 49.195 1634.945 ;
        RECT 50.295 1634.825 51.100 1635.925 ;
        RECT 52.200 1634.945 53.845 1635.925 ;
        RECT 55.415 1634.945 69.965 1636.045 ;
        RECT 71.535 1635.925 77.845 1636.045 ;
        RECT 71.535 1634.945 73.195 1635.925 ;
        RECT 52.200 1634.825 73.195 1634.945 ;
        RECT 74.295 1634.825 75.100 1635.925 ;
        RECT 76.200 1634.945 77.845 1635.925 ;
        RECT 79.415 1634.945 93.965 1636.045 ;
        RECT 95.535 1635.925 101.845 1636.045 ;
        RECT 95.535 1634.945 97.195 1635.925 ;
        RECT 76.200 1634.825 97.195 1634.945 ;
        RECT 98.295 1634.825 99.100 1635.925 ;
        RECT 100.200 1634.945 101.845 1635.925 ;
        RECT 103.415 1634.945 117.965 1636.045 ;
        RECT 119.535 1635.925 125.845 1636.045 ;
        RECT 119.535 1634.945 121.195 1635.925 ;
        RECT 100.200 1634.825 121.195 1634.945 ;
        RECT 122.295 1634.825 123.100 1635.925 ;
        RECT 124.200 1634.945 125.845 1635.925 ;
        RECT 127.415 1634.945 141.965 1636.045 ;
        RECT 143.535 1635.925 149.845 1636.045 ;
        RECT 143.535 1634.945 145.195 1635.925 ;
        RECT 124.200 1634.825 145.195 1634.945 ;
        RECT 146.295 1634.825 147.100 1635.925 ;
        RECT 148.200 1634.945 149.845 1635.925 ;
        RECT 151.415 1634.945 165.965 1636.045 ;
        RECT 167.535 1635.925 173.845 1636.045 ;
        RECT 167.535 1634.945 169.195 1635.925 ;
        RECT 148.200 1634.825 169.195 1634.945 ;
        RECT 170.295 1634.825 171.100 1635.925 ;
        RECT 172.200 1634.945 173.845 1635.925 ;
        RECT 175.415 1634.945 189.965 1636.045 ;
        RECT 191.535 1635.925 197.845 1636.045 ;
        RECT 191.535 1634.945 193.195 1635.925 ;
        RECT 172.200 1634.825 193.195 1634.945 ;
        RECT 194.295 1634.825 195.100 1635.925 ;
        RECT 196.200 1634.945 197.845 1635.925 ;
        RECT 199.415 1634.945 213.965 1636.045 ;
        RECT 215.535 1635.925 221.845 1636.045 ;
        RECT 215.535 1634.945 217.195 1635.925 ;
        RECT 196.200 1634.825 217.195 1634.945 ;
        RECT 218.295 1634.825 219.100 1635.925 ;
        RECT 220.200 1634.945 221.845 1635.925 ;
        RECT 223.415 1634.945 237.965 1636.045 ;
        RECT 239.535 1635.925 245.845 1636.045 ;
        RECT 239.535 1634.945 241.195 1635.925 ;
        RECT 220.200 1634.825 241.195 1634.945 ;
        RECT 242.295 1634.825 243.100 1635.925 ;
        RECT 244.200 1634.945 245.845 1635.925 ;
        RECT 247.415 1634.945 261.965 1636.045 ;
        RECT 263.535 1635.925 269.845 1636.045 ;
        RECT 263.535 1634.945 265.195 1635.925 ;
        RECT 244.200 1634.825 265.195 1634.945 ;
        RECT 266.295 1634.825 267.100 1635.925 ;
        RECT 268.200 1634.945 269.845 1635.925 ;
        RECT 271.415 1634.945 285.965 1636.045 ;
        RECT 287.535 1635.925 293.845 1636.045 ;
        RECT 287.535 1634.945 289.195 1635.925 ;
        RECT 268.200 1634.825 289.195 1634.945 ;
        RECT 290.295 1634.825 291.100 1635.925 ;
        RECT 292.200 1634.945 293.845 1635.925 ;
        RECT 295.415 1634.945 309.965 1636.045 ;
        RECT 311.535 1635.925 317.845 1636.045 ;
        RECT 311.535 1634.945 313.195 1635.925 ;
        RECT 292.200 1634.825 313.195 1634.945 ;
        RECT 314.295 1634.825 315.100 1635.925 ;
        RECT 316.200 1634.945 317.845 1635.925 ;
        RECT 319.415 1634.945 333.965 1636.045 ;
        RECT 335.535 1635.925 341.845 1636.045 ;
        RECT 335.535 1634.945 337.195 1635.925 ;
        RECT 316.200 1634.825 337.195 1634.945 ;
        RECT 338.295 1634.825 339.100 1635.925 ;
        RECT 340.200 1634.945 341.845 1635.925 ;
        RECT 343.415 1634.945 357.965 1636.045 ;
        RECT 359.535 1635.925 365.845 1636.045 ;
        RECT 359.535 1634.945 361.195 1635.925 ;
        RECT 340.200 1634.825 361.195 1634.945 ;
        RECT 362.295 1634.825 363.100 1635.925 ;
        RECT 364.200 1634.945 365.845 1635.925 ;
        RECT 367.415 1634.945 381.965 1636.045 ;
        RECT 383.535 1635.925 389.845 1636.045 ;
        RECT 383.535 1634.945 385.195 1635.925 ;
        RECT 364.200 1634.825 385.195 1634.945 ;
        RECT 386.295 1634.825 387.100 1635.925 ;
        RECT 388.200 1634.945 389.845 1635.925 ;
        RECT 391.415 1634.945 405.965 1636.045 ;
        RECT 407.535 1635.925 413.845 1636.045 ;
        RECT 407.535 1634.945 409.195 1635.925 ;
        RECT 388.200 1634.825 409.195 1634.945 ;
        RECT 410.295 1634.825 411.100 1635.925 ;
        RECT 412.200 1634.945 413.845 1635.925 ;
        RECT 415.415 1634.945 429.965 1636.045 ;
        RECT 431.535 1635.925 437.845 1636.045 ;
        RECT 431.535 1634.945 433.195 1635.925 ;
        RECT 412.200 1634.825 433.195 1634.945 ;
        RECT 434.295 1634.825 435.100 1635.925 ;
        RECT 436.200 1634.945 437.845 1635.925 ;
        RECT 439.415 1634.945 453.965 1636.045 ;
        RECT 455.535 1635.925 461.845 1636.045 ;
        RECT 455.535 1634.945 457.195 1635.925 ;
        RECT 436.200 1634.825 457.195 1634.945 ;
        RECT 458.295 1634.825 459.100 1635.925 ;
        RECT 460.200 1634.945 461.845 1635.925 ;
        RECT 463.415 1634.945 477.965 1636.045 ;
        RECT 479.535 1635.925 485.845 1636.045 ;
        RECT 479.535 1634.945 481.195 1635.925 ;
        RECT 460.200 1634.825 481.195 1634.945 ;
        RECT 482.295 1634.825 483.100 1635.925 ;
        RECT 484.200 1634.945 485.845 1635.925 ;
        RECT 487.415 1634.945 501.965 1636.045 ;
        RECT 503.535 1635.925 509.845 1636.045 ;
        RECT 503.535 1634.945 505.195 1635.925 ;
        RECT 484.200 1634.825 505.195 1634.945 ;
        RECT 506.295 1634.825 507.100 1635.925 ;
        RECT 508.200 1634.945 509.845 1635.925 ;
        RECT 511.415 1634.945 525.965 1636.045 ;
        RECT 527.535 1635.925 533.845 1636.045 ;
        RECT 527.535 1634.945 529.195 1635.925 ;
        RECT 508.200 1634.825 529.195 1634.945 ;
        RECT 530.295 1634.825 531.100 1635.925 ;
        RECT 532.200 1634.945 533.845 1635.925 ;
        RECT 535.415 1634.945 549.965 1636.045 ;
        RECT 551.535 1635.925 557.845 1636.045 ;
        RECT 551.535 1634.945 553.195 1635.925 ;
        RECT 532.200 1634.825 553.195 1634.945 ;
        RECT 554.295 1634.825 555.100 1635.925 ;
        RECT 556.200 1634.945 557.845 1635.925 ;
        RECT 559.415 1634.945 573.965 1636.045 ;
        RECT 575.535 1635.925 581.845 1636.045 ;
        RECT 575.535 1634.945 577.195 1635.925 ;
        RECT 556.200 1634.825 577.195 1634.945 ;
        RECT 578.295 1634.825 579.100 1635.925 ;
        RECT 580.200 1634.945 581.845 1635.925 ;
        RECT 583.415 1634.945 597.965 1636.045 ;
        RECT 599.535 1635.925 605.845 1636.045 ;
        RECT 599.535 1634.945 601.195 1635.925 ;
        RECT 580.200 1634.825 601.195 1634.945 ;
        RECT 602.295 1634.825 603.100 1635.925 ;
        RECT 604.200 1634.945 605.845 1635.925 ;
        RECT 607.415 1634.945 621.965 1636.045 ;
        RECT 623.535 1635.925 629.845 1636.045 ;
        RECT 623.535 1634.945 625.195 1635.925 ;
        RECT 604.200 1634.825 625.195 1634.945 ;
        RECT 626.295 1634.825 627.100 1635.925 ;
        RECT 628.200 1634.945 629.845 1635.925 ;
        RECT 631.415 1634.945 645.965 1636.045 ;
        RECT 647.535 1635.925 653.845 1636.045 ;
        RECT 647.535 1634.945 649.195 1635.925 ;
        RECT 628.200 1634.825 649.195 1634.945 ;
        RECT 650.295 1634.825 651.100 1635.925 ;
        RECT 652.200 1634.945 653.845 1635.925 ;
        RECT 655.415 1634.945 669.965 1636.045 ;
        RECT 671.535 1635.925 677.845 1636.045 ;
        RECT 671.535 1634.945 673.195 1635.925 ;
        RECT 652.200 1634.825 673.195 1634.945 ;
        RECT 674.295 1634.825 675.100 1635.925 ;
        RECT 676.200 1634.945 677.845 1635.925 ;
        RECT 679.415 1634.945 693.965 1636.045 ;
        RECT 695.535 1635.925 701.845 1636.045 ;
        RECT 695.535 1634.945 697.195 1635.925 ;
        RECT 676.200 1634.825 697.195 1634.945 ;
        RECT 698.295 1634.825 699.100 1635.925 ;
        RECT 700.200 1634.945 701.845 1635.925 ;
        RECT 703.415 1634.945 717.965 1636.045 ;
        RECT 719.535 1635.925 725.845 1636.045 ;
        RECT 719.535 1634.945 721.195 1635.925 ;
        RECT 700.200 1634.825 721.195 1634.945 ;
        RECT 722.295 1634.825 723.100 1635.925 ;
        RECT 724.200 1634.945 725.845 1635.925 ;
        RECT 727.415 1634.945 741.965 1636.045 ;
        RECT 743.535 1635.925 749.845 1636.045 ;
        RECT 743.535 1634.945 745.195 1635.925 ;
        RECT 724.200 1634.825 745.195 1634.945 ;
        RECT 746.295 1634.825 747.100 1635.925 ;
        RECT 748.200 1634.945 749.845 1635.925 ;
        RECT 751.415 1634.945 765.965 1636.045 ;
        RECT 767.535 1635.925 773.845 1636.045 ;
        RECT 767.535 1634.945 769.195 1635.925 ;
        RECT 748.200 1634.825 769.195 1634.945 ;
        RECT 770.295 1634.945 773.845 1635.925 ;
        RECT 775.415 1634.945 789.965 1636.045 ;
        RECT 791.535 1635.925 797.845 1636.045 ;
        RECT 791.535 1634.945 793.195 1635.925 ;
        RECT 770.295 1634.825 793.195 1634.945 ;
        RECT 794.295 1634.825 795.100 1635.925 ;
        RECT 796.200 1634.945 797.845 1635.925 ;
        RECT 799.415 1634.945 813.965 1636.045 ;
        RECT 815.535 1635.925 821.845 1636.045 ;
        RECT 815.535 1634.945 817.195 1635.925 ;
        RECT 796.200 1634.825 817.195 1634.945 ;
        RECT 818.295 1634.825 819.100 1635.925 ;
        RECT 820.200 1634.945 821.845 1635.925 ;
        RECT 823.415 1634.945 837.965 1636.045 ;
        RECT 839.535 1635.925 845.845 1636.045 ;
        RECT 839.535 1634.945 841.195 1635.925 ;
        RECT 820.200 1634.825 841.195 1634.945 ;
        RECT 842.295 1634.825 843.100 1635.925 ;
        RECT 844.200 1634.945 845.845 1635.925 ;
        RECT 847.415 1634.945 861.965 1636.045 ;
        RECT 863.535 1635.925 869.845 1636.045 ;
        RECT 863.535 1634.945 865.195 1635.925 ;
        RECT 844.200 1634.825 865.195 1634.945 ;
        RECT 866.295 1634.825 867.100 1635.925 ;
        RECT 868.200 1634.945 869.845 1635.925 ;
        RECT 871.415 1634.945 885.965 1636.045 ;
        RECT 887.535 1635.925 893.845 1636.045 ;
        RECT 887.535 1634.945 889.195 1635.925 ;
        RECT 868.200 1634.825 889.195 1634.945 ;
        RECT 890.295 1634.825 891.100 1635.925 ;
        RECT 892.200 1634.945 893.845 1635.925 ;
        RECT 895.415 1634.945 909.965 1636.045 ;
        RECT 911.535 1635.925 917.845 1636.045 ;
        RECT 911.535 1634.945 913.195 1635.925 ;
        RECT 892.200 1634.825 913.195 1634.945 ;
        RECT 914.295 1634.825 915.100 1635.925 ;
        RECT 916.200 1634.945 917.845 1635.925 ;
        RECT 919.415 1634.945 933.965 1636.045 ;
        RECT 935.535 1635.925 941.845 1636.045 ;
        RECT 935.535 1634.945 937.195 1635.925 ;
        RECT 916.200 1634.825 937.195 1634.945 ;
        RECT 938.295 1634.825 939.100 1635.925 ;
        RECT 940.200 1634.945 941.845 1635.925 ;
        RECT 943.415 1634.945 957.965 1636.045 ;
        RECT 959.535 1635.925 965.845 1636.045 ;
        RECT 959.535 1634.945 961.195 1635.925 ;
        RECT 940.200 1634.825 961.195 1634.945 ;
        RECT 962.295 1634.825 963.100 1635.925 ;
        RECT 964.200 1634.945 965.845 1635.925 ;
        RECT 967.415 1634.945 981.965 1636.045 ;
        RECT 983.535 1635.925 989.845 1636.045 ;
        RECT 983.535 1634.945 985.195 1635.925 ;
        RECT 964.200 1634.825 985.195 1634.945 ;
        RECT 986.295 1634.825 987.100 1635.925 ;
        RECT 988.200 1634.945 989.845 1635.925 ;
        RECT 991.415 1634.945 1005.965 1636.045 ;
        RECT 1007.535 1635.925 1013.845 1636.045 ;
        RECT 1007.535 1634.945 1009.195 1635.925 ;
        RECT 988.200 1634.825 1009.195 1634.945 ;
        RECT 1010.295 1634.825 1011.100 1635.925 ;
        RECT 1012.200 1634.945 1013.845 1635.925 ;
        RECT 1015.415 1634.945 1029.965 1636.045 ;
        RECT 1031.535 1635.925 1037.845 1636.045 ;
        RECT 1031.535 1634.945 1033.195 1635.925 ;
        RECT 1012.200 1634.825 1033.195 1634.945 ;
        RECT 1034.295 1634.825 1035.100 1635.925 ;
        RECT 1036.200 1634.945 1037.845 1635.925 ;
        RECT 1039.415 1634.945 1053.965 1636.045 ;
        RECT 1055.535 1635.925 1061.845 1636.045 ;
        RECT 1055.535 1634.945 1057.195 1635.925 ;
        RECT 1036.200 1634.825 1057.195 1634.945 ;
        RECT 1058.295 1634.825 1059.100 1635.925 ;
        RECT 1060.200 1634.945 1061.845 1635.925 ;
        RECT 1063.415 1634.945 1077.965 1636.045 ;
        RECT 1079.535 1635.925 1085.845 1636.045 ;
        RECT 1079.535 1634.945 1081.195 1635.925 ;
        RECT 1060.200 1634.825 1081.195 1634.945 ;
        RECT 1082.295 1634.825 1083.100 1635.925 ;
        RECT 1084.200 1634.945 1085.845 1635.925 ;
        RECT 1087.415 1634.945 1101.965 1636.045 ;
        RECT 1103.535 1635.925 1109.845 1636.045 ;
        RECT 1103.535 1634.945 1105.195 1635.925 ;
        RECT 1084.200 1634.825 1105.195 1634.945 ;
        RECT 1106.295 1634.825 1107.100 1635.925 ;
        RECT 1108.200 1634.945 1109.845 1635.925 ;
        RECT 1111.415 1634.945 1125.965 1636.045 ;
        RECT 1127.535 1635.925 1133.845 1636.045 ;
        RECT 1127.535 1634.945 1129.195 1635.925 ;
        RECT 1108.200 1634.825 1129.195 1634.945 ;
        RECT 1130.295 1634.825 1131.100 1635.925 ;
        RECT 1132.200 1634.945 1133.845 1635.925 ;
        RECT 1135.415 1634.945 1149.965 1636.045 ;
        RECT 1151.535 1635.925 1157.845 1636.045 ;
        RECT 1151.535 1634.945 1153.195 1635.925 ;
        RECT 1132.200 1634.825 1153.195 1634.945 ;
        RECT 1154.295 1634.825 1155.100 1635.925 ;
        RECT 1156.200 1634.945 1157.845 1635.925 ;
        RECT 1159.415 1634.945 1173.965 1636.045 ;
        RECT 1175.535 1635.925 1181.845 1636.045 ;
        RECT 1175.535 1634.945 1177.195 1635.925 ;
        RECT 1156.200 1634.825 1177.195 1634.945 ;
        RECT 1178.295 1634.825 1179.100 1635.925 ;
        RECT 1180.200 1634.945 1181.845 1635.925 ;
        RECT 1183.415 1634.945 1197.965 1636.045 ;
        RECT 1199.535 1635.925 1205.845 1636.045 ;
        RECT 1199.535 1634.945 1201.195 1635.925 ;
        RECT 1180.200 1634.825 1201.195 1634.945 ;
        RECT 1202.295 1634.825 1203.100 1635.925 ;
        RECT 1204.200 1634.945 1205.845 1635.925 ;
        RECT 1207.415 1634.945 1221.965 1636.045 ;
        RECT 1223.535 1635.925 1229.845 1636.045 ;
        RECT 1223.535 1634.945 1225.195 1635.925 ;
        RECT 1204.200 1634.825 1225.195 1634.945 ;
        RECT 1226.295 1634.825 1227.100 1635.925 ;
        RECT 1228.200 1634.945 1229.845 1635.925 ;
        RECT 1231.415 1634.945 1245.965 1636.045 ;
        RECT 1247.535 1635.925 1253.845 1636.045 ;
        RECT 1247.535 1634.945 1249.195 1635.925 ;
        RECT 1228.200 1634.825 1249.195 1634.945 ;
        RECT 1250.295 1634.825 1251.100 1635.925 ;
        RECT 1252.200 1634.945 1253.845 1635.925 ;
        RECT 1255.415 1634.945 1269.965 1636.045 ;
        RECT 1271.535 1635.925 1277.845 1636.045 ;
        RECT 1271.535 1634.945 1273.195 1635.925 ;
        RECT 1252.200 1634.825 1273.195 1634.945 ;
        RECT 1274.295 1634.825 1275.100 1635.925 ;
        RECT 1276.200 1634.945 1277.845 1635.925 ;
        RECT 1279.415 1634.945 1293.965 1636.045 ;
        RECT 1295.535 1635.925 1301.845 1636.045 ;
        RECT 1295.535 1634.945 1297.195 1635.925 ;
        RECT 1276.200 1634.825 1297.195 1634.945 ;
        RECT 1298.295 1634.825 1299.100 1635.925 ;
        RECT 1300.200 1634.945 1301.845 1635.925 ;
        RECT 1303.415 1634.945 1317.965 1636.045 ;
        RECT 1319.535 1635.925 1325.845 1636.045 ;
        RECT 1319.535 1634.945 1321.195 1635.925 ;
        RECT 1300.200 1634.825 1321.195 1634.945 ;
        RECT 1322.295 1634.825 1323.100 1635.925 ;
        RECT 1324.200 1634.945 1325.845 1635.925 ;
        RECT 1327.415 1634.945 1341.965 1636.045 ;
        RECT 1343.535 1635.925 1349.845 1636.045 ;
        RECT 1343.535 1634.945 1345.195 1635.925 ;
        RECT 1324.200 1634.825 1345.195 1634.945 ;
        RECT 1346.295 1634.825 1347.100 1635.925 ;
        RECT 1348.200 1634.945 1349.845 1635.925 ;
        RECT 1351.415 1634.945 1365.965 1636.045 ;
        RECT 1367.535 1635.925 1373.845 1636.045 ;
        RECT 1367.535 1634.945 1369.195 1635.925 ;
        RECT 1348.200 1634.825 1369.195 1634.945 ;
        RECT 1370.295 1634.825 1371.100 1635.925 ;
        RECT 1372.200 1634.945 1373.845 1635.925 ;
        RECT 1375.415 1634.945 1389.965 1636.045 ;
        RECT 1391.535 1635.925 1397.845 1636.045 ;
        RECT 1391.535 1634.945 1393.195 1635.925 ;
        RECT 1372.200 1634.825 1393.195 1634.945 ;
        RECT 1394.295 1634.825 1395.100 1635.925 ;
        RECT 1396.200 1634.945 1397.845 1635.925 ;
        RECT 1399.415 1634.945 1413.965 1636.045 ;
        RECT 1415.535 1635.925 1421.845 1636.045 ;
        RECT 1415.535 1634.945 1417.195 1635.925 ;
        RECT 1396.200 1634.825 1417.195 1634.945 ;
        RECT 1418.295 1634.825 1419.100 1635.925 ;
        RECT 1420.200 1634.945 1421.845 1635.925 ;
        RECT 1423.415 1634.945 1437.965 1636.045 ;
        RECT 1439.535 1635.925 1445.845 1636.045 ;
        RECT 1439.535 1634.945 1441.195 1635.925 ;
        RECT 1420.200 1634.825 1441.195 1634.945 ;
        RECT 1442.295 1634.825 1443.100 1635.925 ;
        RECT 1444.200 1634.945 1445.845 1635.925 ;
        RECT 1447.415 1634.945 1461.965 1636.045 ;
        RECT 1463.535 1635.925 1469.845 1636.045 ;
        RECT 1463.535 1634.945 1465.195 1635.925 ;
        RECT 1444.200 1634.825 1465.195 1634.945 ;
        RECT 1466.295 1634.825 1467.100 1635.925 ;
        RECT 1468.200 1634.945 1469.845 1635.925 ;
        RECT 1471.415 1634.945 1485.965 1636.045 ;
        RECT 1487.535 1635.925 1493.845 1636.045 ;
        RECT 1487.535 1634.945 1489.195 1635.925 ;
        RECT 1468.200 1634.825 1489.195 1634.945 ;
        RECT 1490.295 1634.825 1491.100 1635.925 ;
        RECT 1492.200 1634.945 1493.845 1635.925 ;
        RECT 1495.415 1634.945 1509.965 1636.045 ;
        RECT 1511.535 1635.925 1517.845 1636.045 ;
        RECT 1511.535 1634.945 1513.195 1635.925 ;
        RECT 1492.200 1634.825 1513.195 1634.945 ;
        RECT 1514.295 1634.825 1515.100 1635.925 ;
        RECT 1516.200 1634.945 1517.845 1635.925 ;
        RECT 1519.415 1634.945 1533.965 1636.045 ;
        RECT 1535.535 1635.925 1560.000 1636.045 ;
        RECT 1535.535 1634.945 1537.195 1635.925 ;
        RECT 1516.200 1634.825 1537.195 1634.945 ;
        RECT 1538.295 1634.825 1560.000 1635.925 ;
        RECT 0.000 1628.500 1560.000 1634.825 ;
        RECT 0.000 1627.400 2.340 1628.500 ;
        RECT 3.440 1627.400 1560.000 1628.500 ;
        RECT 0.000 1620.340 1560.000 1627.400 ;
        RECT 0.000 1619.240 2.340 1620.340 ;
        RECT 3.440 1619.240 1560.000 1620.340 ;
        RECT 0.000 1608.750 1560.000 1619.240 ;
        RECT 0.000 1607.650 2.340 1608.750 ;
        RECT 3.440 1607.650 1560.000 1608.750 ;
        RECT 0.000 1577.470 1560.000 1607.650 ;
        RECT 0.700 1576.370 1560.000 1577.470 ;
        RECT 0.000 1576.110 1560.000 1576.370 ;
        RECT 0.700 1574.330 1560.000 1576.110 ;
        RECT 0.000 1574.070 1560.000 1574.330 ;
        RECT 0.700 1572.970 1560.000 1574.070 ;
        RECT 0.000 1553.670 1560.000 1572.970 ;
        RECT 0.700 1552.570 1560.000 1553.670 ;
        RECT 0.000 1552.310 1560.000 1552.570 ;
        RECT 0.700 1550.530 1560.000 1552.310 ;
        RECT 0.000 1550.270 1560.000 1550.530 ;
        RECT 0.700 1549.170 1560.000 1550.270 ;
        RECT 0.000 1529.190 1560.000 1549.170 ;
        RECT 0.700 1527.410 1560.000 1529.190 ;
        RECT 0.000 1527.150 1560.000 1527.410 ;
        RECT 0.700 1526.050 1560.000 1527.150 ;
        RECT 0.000 1525.790 1560.000 1526.050 ;
        RECT 0.700 1524.690 1560.000 1525.790 ;
        RECT 0.000 1505.390 1560.000 1524.690 ;
        RECT 0.700 1504.290 1560.000 1505.390 ;
        RECT 0.000 1504.030 1560.000 1504.290 ;
        RECT 0.700 1502.250 1560.000 1504.030 ;
        RECT 0.000 1501.990 1560.000 1502.250 ;
        RECT 0.700 1500.890 1560.000 1501.990 ;
        RECT 0.000 1481.590 1560.000 1500.890 ;
        RECT 0.700 1480.490 1560.000 1481.590 ;
        RECT 0.000 1480.230 1560.000 1480.490 ;
        RECT 0.700 1478.450 1560.000 1480.230 ;
        RECT 0.000 1478.190 1560.000 1478.450 ;
        RECT 0.700 1477.090 1560.000 1478.190 ;
        RECT 0.000 1457.110 1560.000 1477.090 ;
        RECT 0.700 1455.330 1560.000 1457.110 ;
        RECT 0.000 1455.070 1560.000 1455.330 ;
        RECT 0.700 1453.290 1560.000 1455.070 ;
        RECT 0.000 1433.310 1560.000 1453.290 ;
        RECT 0.700 1432.210 1560.000 1433.310 ;
        RECT 0.000 1431.950 1560.000 1432.210 ;
        RECT 0.700 1430.170 1560.000 1431.950 ;
        RECT 0.000 1429.910 1560.000 1430.170 ;
        RECT 0.700 1428.810 1560.000 1429.910 ;
        RECT 0.000 1409.510 1560.000 1428.810 ;
        RECT 0.700 1408.410 1560.000 1409.510 ;
        RECT 0.000 1408.150 1560.000 1408.410 ;
        RECT 0.700 1407.050 1560.000 1408.150 ;
        RECT 0.000 1406.790 1560.000 1407.050 ;
        RECT 0.700 1405.010 1560.000 1406.790 ;
        RECT 0.000 1385.710 1560.000 1405.010 ;
        RECT 0.700 1384.610 1560.000 1385.710 ;
        RECT 0.000 1384.350 1560.000 1384.610 ;
        RECT 0.700 1383.250 1560.000 1384.350 ;
        RECT 0.000 1382.990 1560.000 1383.250 ;
        RECT 0.700 1381.210 1560.000 1382.990 ;
        RECT 0.000 1361.230 1560.000 1381.210 ;
        RECT 0.700 1359.450 1560.000 1361.230 ;
        RECT 0.000 1359.190 1560.000 1359.450 ;
        RECT 0.700 1358.090 1560.000 1359.190 ;
        RECT 0.000 1357.830 1560.000 1358.090 ;
        RECT 0.700 1356.730 1560.000 1357.830 ;
        RECT 0.000 1337.430 1560.000 1356.730 ;
        RECT 0.700 1335.650 1560.000 1337.430 ;
        RECT 0.000 1335.390 1560.000 1335.650 ;
        RECT 0.700 1334.290 1560.000 1335.390 ;
        RECT 0.000 1334.030 1560.000 1334.290 ;
        RECT 0.700 1332.930 1560.000 1334.030 ;
        RECT 0.000 1313.630 1560.000 1332.930 ;
        RECT 0.700 1312.530 1560.000 1313.630 ;
        RECT 0.000 1312.270 1560.000 1312.530 ;
        RECT 0.700 1310.490 1560.000 1312.270 ;
        RECT 0.000 1310.230 1560.000 1310.490 ;
        RECT 0.700 1309.130 1560.000 1310.230 ;
        RECT 0.000 1289.150 1560.000 1309.130 ;
        RECT 0.700 1287.370 1560.000 1289.150 ;
        RECT 0.000 1287.110 1560.000 1287.370 ;
        RECT 0.700 1285.330 1560.000 1287.110 ;
        RECT 0.000 1265.350 1560.000 1285.330 ;
        RECT 0.700 1264.250 1560.000 1265.350 ;
        RECT 0.000 1263.990 1560.000 1264.250 ;
        RECT 0.700 1262.210 1560.000 1263.990 ;
        RECT 0.000 1261.950 1560.000 1262.210 ;
        RECT 0.700 1260.850 1560.000 1261.950 ;
        RECT 0.000 1241.550 1560.000 1260.850 ;
        RECT 0.700 1240.450 1560.000 1241.550 ;
        RECT 0.000 1240.190 1560.000 1240.450 ;
        RECT 0.700 1238.410 1560.000 1240.190 ;
        RECT 0.000 1238.150 1560.000 1238.410 ;
        RECT 0.700 1237.050 1560.000 1238.150 ;
        RECT 0.000 1217.070 1560.000 1237.050 ;
        RECT 0.700 1215.290 1560.000 1217.070 ;
        RECT 0.000 1215.030 1560.000 1215.290 ;
        RECT 0.700 1213.250 1560.000 1215.030 ;
        RECT 0.000 1193.270 1560.000 1213.250 ;
        RECT 0.700 1192.170 1560.000 1193.270 ;
        RECT 0.000 1191.910 1560.000 1192.170 ;
        RECT 0.700 1190.130 1560.000 1191.910 ;
        RECT 0.000 1189.870 1560.000 1190.130 ;
        RECT 0.700 1188.770 1560.000 1189.870 ;
        RECT 0.000 1169.470 1560.000 1188.770 ;
        RECT 0.700 1168.370 1560.000 1169.470 ;
        RECT 0.000 1168.110 1560.000 1168.370 ;
        RECT 0.700 1166.330 1560.000 1168.110 ;
        RECT 0.000 1166.070 1560.000 1166.330 ;
        RECT 0.700 1164.970 1560.000 1166.070 ;
        RECT 0.000 1145.670 1560.000 1164.970 ;
        RECT 0.700 1144.570 1560.000 1145.670 ;
        RECT 0.000 1144.310 1560.000 1144.570 ;
        RECT 0.700 1142.530 1560.000 1144.310 ;
        RECT 0.000 1142.270 1560.000 1142.530 ;
        RECT 0.700 1141.170 1560.000 1142.270 ;
        RECT 0.000 1121.190 1560.000 1141.170 ;
        RECT 0.700 1119.410 1560.000 1121.190 ;
        RECT 0.000 1119.150 1560.000 1119.410 ;
        RECT 0.700 1118.050 1560.000 1119.150 ;
        RECT 0.000 1117.790 1560.000 1118.050 ;
        RECT 0.700 1116.690 1560.000 1117.790 ;
        RECT 0.000 1097.390 1560.000 1116.690 ;
        RECT 0.700 1096.290 1560.000 1097.390 ;
        RECT 0.000 1096.030 1560.000 1096.290 ;
        RECT 0.700 1094.250 1560.000 1096.030 ;
        RECT 0.000 1093.990 1560.000 1094.250 ;
        RECT 0.700 1092.890 1560.000 1093.990 ;
        RECT 0.000 1073.590 1560.000 1092.890 ;
        RECT 0.700 1072.490 1560.000 1073.590 ;
        RECT 0.000 1072.230 1560.000 1072.490 ;
        RECT 0.700 1070.450 1560.000 1072.230 ;
        RECT 0.000 1070.190 1560.000 1070.450 ;
        RECT 0.700 1069.090 1560.000 1070.190 ;
        RECT 0.000 1049.110 1560.000 1069.090 ;
        RECT 0.700 1047.330 1560.000 1049.110 ;
        RECT 0.000 1047.070 1560.000 1047.330 ;
        RECT 0.700 1045.290 1560.000 1047.070 ;
        RECT 0.000 1025.310 1560.000 1045.290 ;
        RECT 0.700 1024.210 1560.000 1025.310 ;
        RECT 0.000 1023.950 1560.000 1024.210 ;
        RECT 0.700 1022.170 1560.000 1023.950 ;
        RECT 0.000 1021.910 1560.000 1022.170 ;
        RECT 0.700 1020.810 1560.000 1021.910 ;
        RECT 0.000 1001.510 1560.000 1020.810 ;
        RECT 0.700 1000.410 1560.000 1001.510 ;
        RECT 0.000 1000.150 1560.000 1000.410 ;
        RECT 0.700 999.050 1560.000 1000.150 ;
        RECT 0.000 998.790 1560.000 999.050 ;
        RECT 0.700 997.010 1560.000 998.790 ;
        RECT 0.000 977.710 1560.000 997.010 ;
        RECT 0.700 976.610 1560.000 977.710 ;
        RECT 0.000 976.350 1560.000 976.610 ;
        RECT 0.700 975.250 1560.000 976.350 ;
        RECT 0.000 974.990 1560.000 975.250 ;
        RECT 0.700 973.210 1560.000 974.990 ;
        RECT 0.000 953.230 1560.000 973.210 ;
        RECT 0.700 951.450 1560.000 953.230 ;
        RECT 0.000 951.190 1560.000 951.450 ;
        RECT 0.700 950.090 1560.000 951.190 ;
        RECT 0.000 949.830 1560.000 950.090 ;
        RECT 0.700 948.730 1560.000 949.830 ;
        RECT 0.000 929.430 1560.000 948.730 ;
        RECT 0.700 927.650 1560.000 929.430 ;
        RECT 0.000 927.390 1560.000 927.650 ;
        RECT 0.700 926.290 1560.000 927.390 ;
        RECT 0.000 926.030 1560.000 926.290 ;
        RECT 0.700 924.930 1560.000 926.030 ;
        RECT 0.000 905.630 1560.000 924.930 ;
        RECT 0.700 904.530 1560.000 905.630 ;
        RECT 0.000 904.270 1560.000 904.530 ;
        RECT 0.700 902.490 1560.000 904.270 ;
        RECT 0.000 902.230 1560.000 902.490 ;
        RECT 0.700 901.130 1560.000 902.230 ;
        RECT 0.000 881.150 1560.000 901.130 ;
        RECT 0.700 879.370 1560.000 881.150 ;
        RECT 0.000 879.110 1560.000 879.370 ;
        RECT 0.700 877.330 1560.000 879.110 ;
        RECT 0.000 857.350 1560.000 877.330 ;
        RECT 0.700 856.250 1560.000 857.350 ;
        RECT 0.000 855.990 1560.000 856.250 ;
        RECT 0.700 854.210 1560.000 855.990 ;
        RECT 0.000 853.950 1560.000 854.210 ;
        RECT 0.700 852.850 1560.000 853.950 ;
        RECT 0.000 833.550 1560.000 852.850 ;
        RECT 0.700 832.450 1560.000 833.550 ;
        RECT 0.000 832.190 1560.000 832.450 ;
        RECT 0.700 830.410 1560.000 832.190 ;
        RECT 0.000 830.150 1560.000 830.410 ;
        RECT 0.700 829.050 1560.000 830.150 ;
        RECT 0.000 827.430 1560.000 829.050 ;
        RECT 0.000 826.330 1559.300 827.430 ;
        RECT 0.000 825.390 1560.000 826.330 ;
        RECT 0.000 824.290 1559.300 825.390 ;
        RECT 0.000 823.350 1560.000 824.290 ;
        RECT 0.000 822.250 1559.300 823.350 ;
        RECT 0.000 821.310 1560.000 822.250 ;
        RECT 0.000 820.210 1559.300 821.310 ;
        RECT 0.000 819.270 1560.000 820.210 ;
        RECT 0.000 818.170 1559.300 819.270 ;
        RECT 0.000 817.230 1560.000 818.170 ;
        RECT 0.000 816.130 1559.300 817.230 ;
        RECT 0.000 815.190 1560.000 816.130 ;
        RECT 0.000 814.090 1559.300 815.190 ;
        RECT 0.000 809.070 1560.000 814.090 ;
        RECT 0.700 807.290 1560.000 809.070 ;
        RECT 0.000 807.030 1560.000 807.290 ;
        RECT 0.700 805.250 1560.000 807.030 ;
        RECT 0.000 785.270 1560.000 805.250 ;
        RECT 0.700 784.170 1560.000 785.270 ;
        RECT 0.000 783.910 1560.000 784.170 ;
        RECT 0.700 782.130 1560.000 783.910 ;
        RECT 0.000 781.870 1560.000 782.130 ;
        RECT 0.700 780.770 1560.000 781.870 ;
        RECT 0.000 761.470 1560.000 780.770 ;
        RECT 0.700 760.370 1560.000 761.470 ;
        RECT 0.000 760.110 1560.000 760.370 ;
        RECT 0.700 758.330 1560.000 760.110 ;
        RECT 0.000 758.070 1560.000 758.330 ;
        RECT 0.700 756.970 1560.000 758.070 ;
        RECT 0.000 737.670 1560.000 756.970 ;
        RECT 0.700 736.570 1560.000 737.670 ;
        RECT 0.000 736.310 1560.000 736.570 ;
        RECT 0.700 734.530 1560.000 736.310 ;
        RECT 0.000 734.270 1560.000 734.530 ;
        RECT 0.700 733.170 1560.000 734.270 ;
        RECT 0.000 713.190 1560.000 733.170 ;
        RECT 0.700 711.410 1560.000 713.190 ;
        RECT 0.000 711.150 1560.000 711.410 ;
        RECT 0.700 710.050 1560.000 711.150 ;
        RECT 0.000 709.790 1560.000 710.050 ;
        RECT 0.700 708.690 1560.000 709.790 ;
        RECT 0.000 689.390 1560.000 708.690 ;
        RECT 0.700 688.290 1560.000 689.390 ;
        RECT 0.000 688.030 1560.000 688.290 ;
        RECT 0.700 686.250 1560.000 688.030 ;
        RECT 0.000 685.990 1560.000 686.250 ;
        RECT 0.700 684.890 1560.000 685.990 ;
        RECT 0.000 665.590 1560.000 684.890 ;
        RECT 0.700 664.490 1560.000 665.590 ;
        RECT 0.000 664.230 1560.000 664.490 ;
        RECT 0.700 662.450 1560.000 664.230 ;
        RECT 0.000 662.190 1560.000 662.450 ;
        RECT 0.700 661.090 1560.000 662.190 ;
        RECT 0.000 641.110 1560.000 661.090 ;
        RECT 0.700 639.330 1560.000 641.110 ;
        RECT 0.000 639.070 1560.000 639.330 ;
        RECT 0.700 637.290 1560.000 639.070 ;
        RECT 0.000 617.310 1560.000 637.290 ;
        RECT 0.700 616.210 1560.000 617.310 ;
        RECT 0.000 615.950 1560.000 616.210 ;
        RECT 0.700 614.170 1560.000 615.950 ;
        RECT 0.000 613.910 1560.000 614.170 ;
        RECT 0.700 612.810 1560.000 613.910 ;
        RECT 0.000 593.510 1560.000 612.810 ;
        RECT 0.700 592.410 1560.000 593.510 ;
        RECT 0.000 592.150 1560.000 592.410 ;
        RECT 0.700 591.050 1560.000 592.150 ;
        RECT 0.000 590.790 1560.000 591.050 ;
        RECT 0.700 589.010 1560.000 590.790 ;
        RECT 0.000 569.710 1560.000 589.010 ;
        RECT 0.700 568.610 1560.000 569.710 ;
        RECT 0.000 568.350 1560.000 568.610 ;
        RECT 0.700 567.250 1560.000 568.350 ;
        RECT 0.000 566.990 1560.000 567.250 ;
        RECT 0.700 565.210 1560.000 566.990 ;
        RECT 0.000 545.230 1560.000 565.210 ;
        RECT 0.700 543.450 1560.000 545.230 ;
        RECT 0.000 543.190 1560.000 543.450 ;
        RECT 0.700 542.090 1560.000 543.190 ;
        RECT 0.000 541.830 1560.000 542.090 ;
        RECT 0.700 540.730 1560.000 541.830 ;
        RECT 0.000 521.430 1560.000 540.730 ;
        RECT 0.700 519.650 1560.000 521.430 ;
        RECT 0.000 519.390 1560.000 519.650 ;
        RECT 0.700 518.290 1560.000 519.390 ;
        RECT 0.000 518.030 1560.000 518.290 ;
        RECT 0.700 516.930 1560.000 518.030 ;
        RECT 0.000 497.630 1560.000 516.930 ;
        RECT 0.700 496.530 1560.000 497.630 ;
        RECT 0.000 496.270 1560.000 496.530 ;
        RECT 0.700 494.490 1560.000 496.270 ;
        RECT 0.000 494.230 1560.000 494.490 ;
        RECT 0.700 493.130 1560.000 494.230 ;
        RECT 0.000 473.150 1560.000 493.130 ;
        RECT 0.700 471.370 1560.000 473.150 ;
        RECT 0.000 471.110 1560.000 471.370 ;
        RECT 0.700 469.330 1560.000 471.110 ;
        RECT 0.000 449.350 1560.000 469.330 ;
        RECT 0.700 448.250 1560.000 449.350 ;
        RECT 0.000 447.990 1560.000 448.250 ;
        RECT 0.700 446.210 1560.000 447.990 ;
        RECT 0.000 445.950 1560.000 446.210 ;
        RECT 0.700 444.850 1560.000 445.950 ;
        RECT 0.000 425.550 1560.000 444.850 ;
        RECT 0.700 424.450 1560.000 425.550 ;
        RECT 0.000 424.190 1560.000 424.450 ;
        RECT 0.700 422.410 1560.000 424.190 ;
        RECT 0.000 422.150 1560.000 422.410 ;
        RECT 0.700 421.050 1560.000 422.150 ;
        RECT 0.000 401.070 1560.000 421.050 ;
        RECT 0.700 399.290 1560.000 401.070 ;
        RECT 0.000 399.030 1560.000 399.290 ;
        RECT 0.700 397.250 1560.000 399.030 ;
        RECT 0.000 377.270 1560.000 397.250 ;
        RECT 0.700 376.170 1560.000 377.270 ;
        RECT 0.000 375.910 1560.000 376.170 ;
        RECT 0.700 374.130 1560.000 375.910 ;
        RECT 0.000 373.870 1560.000 374.130 ;
        RECT 0.700 372.770 1560.000 373.870 ;
        RECT 0.000 353.470 1560.000 372.770 ;
        RECT 0.700 352.370 1560.000 353.470 ;
        RECT 0.000 352.110 1560.000 352.370 ;
        RECT 0.700 350.330 1560.000 352.110 ;
        RECT 0.000 350.070 1560.000 350.330 ;
        RECT 0.700 348.970 1560.000 350.070 ;
        RECT 0.000 329.670 1560.000 348.970 ;
        RECT 0.700 328.570 1560.000 329.670 ;
        RECT 0.000 328.310 1560.000 328.570 ;
        RECT 0.700 326.530 1560.000 328.310 ;
        RECT 0.000 326.270 1560.000 326.530 ;
        RECT 0.700 325.170 1560.000 326.270 ;
        RECT 0.000 305.190 1560.000 325.170 ;
        RECT 0.700 303.410 1560.000 305.190 ;
        RECT 0.000 303.150 1560.000 303.410 ;
        RECT 0.700 302.050 1560.000 303.150 ;
        RECT 0.000 301.790 1560.000 302.050 ;
        RECT 0.700 300.690 1560.000 301.790 ;
        RECT 0.000 281.390 1560.000 300.690 ;
        RECT 0.700 280.290 1560.000 281.390 ;
        RECT 0.000 280.030 1560.000 280.290 ;
        RECT 0.700 278.250 1560.000 280.030 ;
        RECT 0.000 277.990 1560.000 278.250 ;
        RECT 0.700 276.890 1560.000 277.990 ;
        RECT 0.000 257.590 1560.000 276.890 ;
        RECT 0.700 256.490 1560.000 257.590 ;
        RECT 0.000 256.230 1560.000 256.490 ;
        RECT 0.700 254.450 1560.000 256.230 ;
        RECT 0.000 254.190 1560.000 254.450 ;
        RECT 0.700 253.090 1560.000 254.190 ;
        RECT 0.000 233.110 1560.000 253.090 ;
        RECT 0.700 231.330 1560.000 233.110 ;
        RECT 0.000 231.070 1560.000 231.330 ;
        RECT 0.700 229.290 1560.000 231.070 ;
        RECT 0.000 209.310 1560.000 229.290 ;
        RECT 0.700 208.210 1560.000 209.310 ;
        RECT 0.000 207.950 1560.000 208.210 ;
        RECT 0.700 206.170 1560.000 207.950 ;
        RECT 0.000 205.910 1560.000 206.170 ;
        RECT 0.700 204.810 1560.000 205.910 ;
        RECT 0.000 185.510 1560.000 204.810 ;
        RECT 0.700 184.410 1560.000 185.510 ;
        RECT 0.000 184.150 1560.000 184.410 ;
        RECT 0.700 183.050 1560.000 184.150 ;
        RECT 0.000 182.790 1560.000 183.050 ;
        RECT 0.700 181.010 1560.000 182.790 ;
        RECT 0.000 161.710 1560.000 181.010 ;
        RECT 0.700 160.610 1560.000 161.710 ;
        RECT 0.000 160.350 1560.000 160.610 ;
        RECT 0.700 159.250 1560.000 160.350 ;
        RECT 0.000 158.990 1560.000 159.250 ;
        RECT 0.700 157.210 1560.000 158.990 ;
        RECT 0.000 137.230 1560.000 157.210 ;
        RECT 0.700 135.450 1560.000 137.230 ;
        RECT 0.000 135.190 1560.000 135.450 ;
        RECT 0.700 134.090 1560.000 135.190 ;
        RECT 0.000 133.830 1560.000 134.090 ;
        RECT 0.700 132.730 1560.000 133.830 ;
        RECT 0.000 113.430 1560.000 132.730 ;
        RECT 0.700 111.650 1560.000 113.430 ;
        RECT 0.000 111.390 1560.000 111.650 ;
        RECT 0.700 110.290 1560.000 111.390 ;
        RECT 0.000 110.030 1560.000 110.290 ;
        RECT 0.700 108.930 1560.000 110.030 ;
        RECT 0.000 89.630 1560.000 108.930 ;
        RECT 0.700 88.530 1560.000 89.630 ;
        RECT 0.000 88.270 1560.000 88.530 ;
        RECT 0.700 86.490 1560.000 88.270 ;
        RECT 0.000 86.230 1560.000 86.490 ;
        RECT 0.700 85.130 1560.000 86.230 ;
        RECT 0.000 65.150 1560.000 85.130 ;
        RECT 0.700 63.370 1560.000 65.150 ;
        RECT 0.000 63.110 1560.000 63.370 ;
        RECT 0.700 61.330 1560.000 63.110 ;
        RECT 0.000 31.150 1560.000 61.330 ;
        RECT 0.000 30.050 2.340 31.150 ;
        RECT 3.440 30.050 1560.000 31.150 ;
        RECT 0.000 19.620 1560.000 30.050 ;
        RECT 0.000 18.520 2.340 19.620 ;
        RECT 3.440 18.520 1560.000 19.620 ;
        RECT 0.000 10.780 1560.000 18.520 ;
        RECT 0.000 9.680 2.340 10.780 ;
        RECT 3.440 9.680 1560.000 10.780 ;
        RECT 0.000 2.280 1560.000 9.680 ;
        RECT 0.000 2.160 25.195 2.280 ;
        RECT 0.000 1.060 5.845 2.160 ;
        RECT 7.415 1.060 21.965 2.160 ;
        RECT 23.535 1.180 25.195 2.160 ;
        RECT 26.295 1.180 27.100 2.280 ;
        RECT 28.200 2.160 49.195 2.280 ;
        RECT 28.200 1.180 29.845 2.160 ;
        RECT 23.535 1.060 29.845 1.180 ;
        RECT 31.415 1.060 45.965 2.160 ;
        RECT 47.535 1.180 49.195 2.160 ;
        RECT 50.295 1.180 51.100 2.280 ;
        RECT 52.200 2.160 73.195 2.280 ;
        RECT 52.200 1.180 53.845 2.160 ;
        RECT 47.535 1.060 53.845 1.180 ;
        RECT 55.415 1.060 69.965 2.160 ;
        RECT 71.535 1.180 73.195 2.160 ;
        RECT 74.295 1.180 75.100 2.280 ;
        RECT 76.200 2.160 97.195 2.280 ;
        RECT 76.200 1.180 77.845 2.160 ;
        RECT 71.535 1.060 77.845 1.180 ;
        RECT 79.415 1.060 93.965 2.160 ;
        RECT 95.535 1.180 97.195 2.160 ;
        RECT 98.295 1.180 99.100 2.280 ;
        RECT 100.200 2.160 121.195 2.280 ;
        RECT 100.200 1.180 101.845 2.160 ;
        RECT 95.535 1.060 101.845 1.180 ;
        RECT 103.415 1.060 117.965 2.160 ;
        RECT 119.535 1.180 121.195 2.160 ;
        RECT 122.295 1.180 123.100 2.280 ;
        RECT 124.200 2.160 145.195 2.280 ;
        RECT 124.200 1.180 125.845 2.160 ;
        RECT 119.535 1.060 125.845 1.180 ;
        RECT 127.415 1.060 141.965 2.160 ;
        RECT 143.535 1.180 145.195 2.160 ;
        RECT 146.295 1.180 147.100 2.280 ;
        RECT 148.200 2.160 169.195 2.280 ;
        RECT 148.200 1.180 149.845 2.160 ;
        RECT 143.535 1.060 149.845 1.180 ;
        RECT 151.415 1.060 165.965 2.160 ;
        RECT 167.535 1.180 169.195 2.160 ;
        RECT 170.295 1.180 171.100 2.280 ;
        RECT 172.200 2.160 193.195 2.280 ;
        RECT 172.200 1.180 173.845 2.160 ;
        RECT 167.535 1.060 173.845 1.180 ;
        RECT 175.415 1.060 189.965 2.160 ;
        RECT 191.535 1.180 193.195 2.160 ;
        RECT 194.295 1.180 195.100 2.280 ;
        RECT 196.200 2.160 217.195 2.280 ;
        RECT 196.200 1.180 197.845 2.160 ;
        RECT 191.535 1.060 197.845 1.180 ;
        RECT 199.415 1.060 213.965 2.160 ;
        RECT 215.535 1.180 217.195 2.160 ;
        RECT 218.295 1.180 219.100 2.280 ;
        RECT 220.200 2.160 241.195 2.280 ;
        RECT 220.200 1.180 221.845 2.160 ;
        RECT 215.535 1.060 221.845 1.180 ;
        RECT 223.415 1.060 237.965 2.160 ;
        RECT 239.535 1.180 241.195 2.160 ;
        RECT 242.295 1.180 243.100 2.280 ;
        RECT 244.200 2.160 265.195 2.280 ;
        RECT 244.200 1.180 245.845 2.160 ;
        RECT 239.535 1.060 245.845 1.180 ;
        RECT 247.415 1.060 261.965 2.160 ;
        RECT 263.535 1.180 265.195 2.160 ;
        RECT 266.295 1.180 267.100 2.280 ;
        RECT 268.200 2.160 289.195 2.280 ;
        RECT 268.200 1.180 269.845 2.160 ;
        RECT 263.535 1.060 269.845 1.180 ;
        RECT 271.415 1.060 285.965 2.160 ;
        RECT 287.535 1.180 289.195 2.160 ;
        RECT 290.295 1.180 291.100 2.280 ;
        RECT 292.200 2.160 313.195 2.280 ;
        RECT 292.200 1.180 293.845 2.160 ;
        RECT 287.535 1.060 293.845 1.180 ;
        RECT 295.415 1.060 309.965 2.160 ;
        RECT 311.535 1.180 313.195 2.160 ;
        RECT 314.295 1.180 315.100 2.280 ;
        RECT 316.200 2.160 337.195 2.280 ;
        RECT 316.200 1.180 317.845 2.160 ;
        RECT 311.535 1.060 317.845 1.180 ;
        RECT 319.415 1.060 333.965 2.160 ;
        RECT 335.535 1.180 337.195 2.160 ;
        RECT 338.295 1.180 339.100 2.280 ;
        RECT 340.200 2.160 361.195 2.280 ;
        RECT 340.200 1.180 341.845 2.160 ;
        RECT 335.535 1.060 341.845 1.180 ;
        RECT 343.415 1.060 357.965 2.160 ;
        RECT 359.535 1.180 361.195 2.160 ;
        RECT 362.295 1.180 363.100 2.280 ;
        RECT 364.200 2.160 385.195 2.280 ;
        RECT 364.200 1.180 365.845 2.160 ;
        RECT 359.535 1.060 365.845 1.180 ;
        RECT 367.415 1.060 381.965 2.160 ;
        RECT 383.535 1.180 385.195 2.160 ;
        RECT 386.295 1.180 387.100 2.280 ;
        RECT 388.200 2.160 409.195 2.280 ;
        RECT 388.200 1.180 389.845 2.160 ;
        RECT 383.535 1.060 389.845 1.180 ;
        RECT 391.415 1.060 405.965 2.160 ;
        RECT 407.535 1.180 409.195 2.160 ;
        RECT 410.295 1.180 411.100 2.280 ;
        RECT 412.200 2.160 433.195 2.280 ;
        RECT 412.200 1.180 413.845 2.160 ;
        RECT 407.535 1.060 413.845 1.180 ;
        RECT 415.415 1.060 429.965 2.160 ;
        RECT 431.535 1.180 433.195 2.160 ;
        RECT 434.295 1.180 435.100 2.280 ;
        RECT 436.200 2.160 457.195 2.280 ;
        RECT 436.200 1.180 437.845 2.160 ;
        RECT 431.535 1.060 437.845 1.180 ;
        RECT 439.415 1.060 453.965 2.160 ;
        RECT 455.535 1.180 457.195 2.160 ;
        RECT 458.295 1.180 459.100 2.280 ;
        RECT 460.200 2.160 481.195 2.280 ;
        RECT 460.200 1.180 461.845 2.160 ;
        RECT 455.535 1.060 461.845 1.180 ;
        RECT 463.415 1.060 477.965 2.160 ;
        RECT 479.535 1.180 481.195 2.160 ;
        RECT 482.295 1.180 483.100 2.280 ;
        RECT 484.200 2.160 505.195 2.280 ;
        RECT 484.200 1.180 485.845 2.160 ;
        RECT 479.535 1.060 485.845 1.180 ;
        RECT 487.415 1.060 501.965 2.160 ;
        RECT 503.535 1.180 505.195 2.160 ;
        RECT 506.295 1.180 507.100 2.280 ;
        RECT 508.200 2.160 529.195 2.280 ;
        RECT 508.200 1.180 509.845 2.160 ;
        RECT 503.535 1.060 509.845 1.180 ;
        RECT 511.415 1.060 525.965 2.160 ;
        RECT 527.535 1.180 529.195 2.160 ;
        RECT 530.295 1.180 531.100 2.280 ;
        RECT 532.200 2.160 553.195 2.280 ;
        RECT 532.200 1.180 533.845 2.160 ;
        RECT 527.535 1.060 533.845 1.180 ;
        RECT 535.415 1.060 549.965 2.160 ;
        RECT 551.535 1.180 553.195 2.160 ;
        RECT 554.295 1.180 555.100 2.280 ;
        RECT 556.200 2.160 577.195 2.280 ;
        RECT 556.200 1.180 557.845 2.160 ;
        RECT 551.535 1.060 557.845 1.180 ;
        RECT 559.415 1.060 573.965 2.160 ;
        RECT 575.535 1.180 577.195 2.160 ;
        RECT 578.295 1.180 579.100 2.280 ;
        RECT 580.200 2.160 601.195 2.280 ;
        RECT 580.200 1.180 581.845 2.160 ;
        RECT 575.535 1.060 581.845 1.180 ;
        RECT 583.415 1.060 597.965 2.160 ;
        RECT 599.535 1.180 601.195 2.160 ;
        RECT 602.295 1.180 603.100 2.280 ;
        RECT 604.200 2.160 625.195 2.280 ;
        RECT 604.200 1.180 605.845 2.160 ;
        RECT 599.535 1.060 605.845 1.180 ;
        RECT 607.415 1.060 621.965 2.160 ;
        RECT 623.535 1.180 625.195 2.160 ;
        RECT 626.295 1.180 627.100 2.280 ;
        RECT 628.200 2.160 649.195 2.280 ;
        RECT 628.200 1.180 629.845 2.160 ;
        RECT 623.535 1.060 629.845 1.180 ;
        RECT 631.415 1.060 645.965 2.160 ;
        RECT 647.535 1.180 649.195 2.160 ;
        RECT 650.295 1.180 651.100 2.280 ;
        RECT 652.200 2.160 673.195 2.280 ;
        RECT 652.200 1.180 653.845 2.160 ;
        RECT 647.535 1.060 653.845 1.180 ;
        RECT 655.415 1.060 669.965 2.160 ;
        RECT 671.535 1.180 673.195 2.160 ;
        RECT 674.295 1.180 675.100 2.280 ;
        RECT 676.200 2.160 697.195 2.280 ;
        RECT 676.200 1.180 677.845 2.160 ;
        RECT 671.535 1.060 677.845 1.180 ;
        RECT 679.415 1.060 693.965 2.160 ;
        RECT 695.535 1.180 697.195 2.160 ;
        RECT 698.295 1.180 699.100 2.280 ;
        RECT 700.200 2.160 721.195 2.280 ;
        RECT 700.200 1.180 701.845 2.160 ;
        RECT 695.535 1.060 701.845 1.180 ;
        RECT 703.415 1.060 717.965 2.160 ;
        RECT 719.535 1.180 721.195 2.160 ;
        RECT 722.295 1.180 723.100 2.280 ;
        RECT 724.200 2.160 745.195 2.280 ;
        RECT 724.200 1.180 725.845 2.160 ;
        RECT 719.535 1.060 725.845 1.180 ;
        RECT 727.415 1.060 741.965 2.160 ;
        RECT 743.535 1.180 745.195 2.160 ;
        RECT 746.295 1.180 747.100 2.280 ;
        RECT 748.200 2.160 769.195 2.280 ;
        RECT 748.200 1.180 749.845 2.160 ;
        RECT 743.535 1.060 749.845 1.180 ;
        RECT 751.415 1.060 765.965 2.160 ;
        RECT 767.535 1.180 769.195 2.160 ;
        RECT 770.295 2.160 793.195 2.280 ;
        RECT 770.295 1.180 773.845 2.160 ;
        RECT 767.535 1.060 773.845 1.180 ;
        RECT 775.415 1.060 789.965 2.160 ;
        RECT 791.535 1.180 793.195 2.160 ;
        RECT 794.295 1.180 795.100 2.280 ;
        RECT 796.200 2.160 817.195 2.280 ;
        RECT 796.200 1.180 797.845 2.160 ;
        RECT 791.535 1.060 797.845 1.180 ;
        RECT 799.415 1.060 813.965 2.160 ;
        RECT 815.535 1.180 817.195 2.160 ;
        RECT 818.295 1.180 819.100 2.280 ;
        RECT 820.200 2.160 841.195 2.280 ;
        RECT 820.200 1.180 821.845 2.160 ;
        RECT 815.535 1.060 821.845 1.180 ;
        RECT 823.415 1.060 837.965 2.160 ;
        RECT 839.535 1.180 841.195 2.160 ;
        RECT 842.295 1.180 843.100 2.280 ;
        RECT 844.200 2.160 865.195 2.280 ;
        RECT 844.200 1.180 845.845 2.160 ;
        RECT 839.535 1.060 845.845 1.180 ;
        RECT 847.415 1.060 861.965 2.160 ;
        RECT 863.535 1.180 865.195 2.160 ;
        RECT 866.295 1.180 867.100 2.280 ;
        RECT 868.200 2.160 889.195 2.280 ;
        RECT 868.200 1.180 869.845 2.160 ;
        RECT 863.535 1.060 869.845 1.180 ;
        RECT 871.415 1.060 885.965 2.160 ;
        RECT 887.535 1.180 889.195 2.160 ;
        RECT 890.295 1.180 891.100 2.280 ;
        RECT 892.200 2.160 913.195 2.280 ;
        RECT 892.200 1.180 893.845 2.160 ;
        RECT 887.535 1.060 893.845 1.180 ;
        RECT 895.415 1.060 909.965 2.160 ;
        RECT 911.535 1.180 913.195 2.160 ;
        RECT 914.295 1.180 915.100 2.280 ;
        RECT 916.200 2.160 937.195 2.280 ;
        RECT 916.200 1.180 917.845 2.160 ;
        RECT 911.535 1.060 917.845 1.180 ;
        RECT 919.415 1.060 933.965 2.160 ;
        RECT 935.535 1.180 937.195 2.160 ;
        RECT 938.295 1.180 939.100 2.280 ;
        RECT 940.200 2.160 961.195 2.280 ;
        RECT 940.200 1.180 941.845 2.160 ;
        RECT 935.535 1.060 941.845 1.180 ;
        RECT 943.415 1.060 957.965 2.160 ;
        RECT 959.535 1.180 961.195 2.160 ;
        RECT 962.295 1.180 963.100 2.280 ;
        RECT 964.200 2.160 985.195 2.280 ;
        RECT 964.200 1.180 965.845 2.160 ;
        RECT 959.535 1.060 965.845 1.180 ;
        RECT 967.415 1.060 981.965 2.160 ;
        RECT 983.535 1.180 985.195 2.160 ;
        RECT 986.295 1.180 987.100 2.280 ;
        RECT 988.200 2.160 1009.195 2.280 ;
        RECT 988.200 1.180 989.845 2.160 ;
        RECT 983.535 1.060 989.845 1.180 ;
        RECT 991.415 1.060 1005.965 2.160 ;
        RECT 1007.535 1.180 1009.195 2.160 ;
        RECT 1010.295 1.180 1011.100 2.280 ;
        RECT 1012.200 2.160 1033.195 2.280 ;
        RECT 1012.200 1.180 1013.845 2.160 ;
        RECT 1007.535 1.060 1013.845 1.180 ;
        RECT 1015.415 1.060 1029.965 2.160 ;
        RECT 1031.535 1.180 1033.195 2.160 ;
        RECT 1034.295 1.180 1035.100 2.280 ;
        RECT 1036.200 2.160 1057.195 2.280 ;
        RECT 1036.200 1.180 1037.845 2.160 ;
        RECT 1031.535 1.060 1037.845 1.180 ;
        RECT 1039.415 1.060 1053.965 2.160 ;
        RECT 1055.535 1.180 1057.195 2.160 ;
        RECT 1058.295 1.180 1059.100 2.280 ;
        RECT 1060.200 2.160 1081.195 2.280 ;
        RECT 1060.200 1.180 1061.845 2.160 ;
        RECT 1055.535 1.060 1061.845 1.180 ;
        RECT 1063.415 1.060 1077.965 2.160 ;
        RECT 1079.535 1.180 1081.195 2.160 ;
        RECT 1082.295 1.180 1083.100 2.280 ;
        RECT 1084.200 2.160 1105.195 2.280 ;
        RECT 1084.200 1.180 1085.845 2.160 ;
        RECT 1079.535 1.060 1085.845 1.180 ;
        RECT 1087.415 1.060 1101.965 2.160 ;
        RECT 1103.535 1.180 1105.195 2.160 ;
        RECT 1106.295 1.180 1107.100 2.280 ;
        RECT 1108.200 2.160 1129.195 2.280 ;
        RECT 1108.200 1.180 1109.845 2.160 ;
        RECT 1103.535 1.060 1109.845 1.180 ;
        RECT 1111.415 1.060 1125.965 2.160 ;
        RECT 1127.535 1.180 1129.195 2.160 ;
        RECT 1130.295 1.180 1131.100 2.280 ;
        RECT 1132.200 2.160 1153.195 2.280 ;
        RECT 1132.200 1.180 1133.845 2.160 ;
        RECT 1127.535 1.060 1133.845 1.180 ;
        RECT 1135.415 1.060 1149.965 2.160 ;
        RECT 1151.535 1.180 1153.195 2.160 ;
        RECT 1154.295 1.180 1155.100 2.280 ;
        RECT 1156.200 2.160 1177.195 2.280 ;
        RECT 1156.200 1.180 1157.845 2.160 ;
        RECT 1151.535 1.060 1157.845 1.180 ;
        RECT 1159.415 1.060 1173.965 2.160 ;
        RECT 1175.535 1.180 1177.195 2.160 ;
        RECT 1178.295 1.180 1179.100 2.280 ;
        RECT 1180.200 2.160 1201.195 2.280 ;
        RECT 1180.200 1.180 1181.845 2.160 ;
        RECT 1175.535 1.060 1181.845 1.180 ;
        RECT 1183.415 1.060 1197.965 2.160 ;
        RECT 1199.535 1.180 1201.195 2.160 ;
        RECT 1202.295 1.180 1203.100 2.280 ;
        RECT 1204.200 2.160 1225.195 2.280 ;
        RECT 1204.200 1.180 1205.845 2.160 ;
        RECT 1199.535 1.060 1205.845 1.180 ;
        RECT 1207.415 1.060 1221.965 2.160 ;
        RECT 1223.535 1.180 1225.195 2.160 ;
        RECT 1226.295 1.180 1227.100 2.280 ;
        RECT 1228.200 2.160 1249.195 2.280 ;
        RECT 1228.200 1.180 1229.845 2.160 ;
        RECT 1223.535 1.060 1229.845 1.180 ;
        RECT 1231.415 1.060 1245.965 2.160 ;
        RECT 1247.535 1.180 1249.195 2.160 ;
        RECT 1250.295 1.180 1251.100 2.280 ;
        RECT 1252.200 2.160 1273.195 2.280 ;
        RECT 1252.200 1.180 1253.845 2.160 ;
        RECT 1247.535 1.060 1253.845 1.180 ;
        RECT 1255.415 1.060 1269.965 2.160 ;
        RECT 1271.535 1.180 1273.195 2.160 ;
        RECT 1274.295 1.180 1275.100 2.280 ;
        RECT 1276.200 2.160 1297.195 2.280 ;
        RECT 1276.200 1.180 1277.845 2.160 ;
        RECT 1271.535 1.060 1277.845 1.180 ;
        RECT 1279.415 1.060 1293.965 2.160 ;
        RECT 1295.535 1.180 1297.195 2.160 ;
        RECT 1298.295 1.180 1299.100 2.280 ;
        RECT 1300.200 2.160 1321.195 2.280 ;
        RECT 1300.200 1.180 1301.845 2.160 ;
        RECT 1295.535 1.060 1301.845 1.180 ;
        RECT 1303.415 1.060 1317.965 2.160 ;
        RECT 1319.535 1.180 1321.195 2.160 ;
        RECT 1322.295 1.180 1323.100 2.280 ;
        RECT 1324.200 2.160 1345.195 2.280 ;
        RECT 1324.200 1.180 1325.845 2.160 ;
        RECT 1319.535 1.060 1325.845 1.180 ;
        RECT 1327.415 1.060 1341.965 2.160 ;
        RECT 1343.535 1.180 1345.195 2.160 ;
        RECT 1346.295 1.180 1347.100 2.280 ;
        RECT 1348.200 2.160 1369.195 2.280 ;
        RECT 1348.200 1.180 1349.845 2.160 ;
        RECT 1343.535 1.060 1349.845 1.180 ;
        RECT 1351.415 1.060 1365.965 2.160 ;
        RECT 1367.535 1.180 1369.195 2.160 ;
        RECT 1370.295 1.180 1371.100 2.280 ;
        RECT 1372.200 2.160 1393.195 2.280 ;
        RECT 1372.200 1.180 1373.845 2.160 ;
        RECT 1367.535 1.060 1373.845 1.180 ;
        RECT 1375.415 1.060 1389.965 2.160 ;
        RECT 1391.535 1.180 1393.195 2.160 ;
        RECT 1394.295 1.180 1395.100 2.280 ;
        RECT 1396.200 2.160 1417.195 2.280 ;
        RECT 1396.200 1.180 1397.845 2.160 ;
        RECT 1391.535 1.060 1397.845 1.180 ;
        RECT 1399.415 1.060 1413.965 2.160 ;
        RECT 1415.535 1.180 1417.195 2.160 ;
        RECT 1418.295 1.180 1419.100 2.280 ;
        RECT 1420.200 2.160 1441.195 2.280 ;
        RECT 1420.200 1.180 1421.845 2.160 ;
        RECT 1415.535 1.060 1421.845 1.180 ;
        RECT 1423.415 1.060 1437.965 2.160 ;
        RECT 1439.535 1.180 1441.195 2.160 ;
        RECT 1442.295 1.180 1443.100 2.280 ;
        RECT 1444.200 2.160 1465.195 2.280 ;
        RECT 1444.200 1.180 1445.845 2.160 ;
        RECT 1439.535 1.060 1445.845 1.180 ;
        RECT 1447.415 1.060 1461.965 2.160 ;
        RECT 1463.535 1.180 1465.195 2.160 ;
        RECT 1466.295 1.180 1467.100 2.280 ;
        RECT 1468.200 2.160 1489.195 2.280 ;
        RECT 1468.200 1.180 1469.845 2.160 ;
        RECT 1463.535 1.060 1469.845 1.180 ;
        RECT 1471.415 1.060 1485.965 2.160 ;
        RECT 1487.535 1.180 1489.195 2.160 ;
        RECT 1490.295 1.180 1491.100 2.280 ;
        RECT 1492.200 2.160 1513.195 2.280 ;
        RECT 1492.200 1.180 1493.845 2.160 ;
        RECT 1487.535 1.060 1493.845 1.180 ;
        RECT 1495.415 1.060 1509.965 2.160 ;
        RECT 1511.535 1.180 1513.195 2.160 ;
        RECT 1514.295 1.180 1515.100 2.280 ;
        RECT 1516.200 2.160 1537.195 2.280 ;
        RECT 1516.200 1.180 1517.845 2.160 ;
        RECT 1511.535 1.060 1517.845 1.180 ;
        RECT 1519.415 1.060 1533.965 2.160 ;
        RECT 1535.535 1.180 1537.195 2.160 ;
        RECT 1538.295 1.180 1560.000 2.280 ;
        RECT 1535.535 1.060 1560.000 1.180 ;
        RECT 0.000 0.995 1560.000 1.060 ;
        RECT 0.000 0.945 1538.850 0.995 ;
        RECT 0.000 0.125 3.100 0.945 ;
        RECT 4.200 0.125 771.100 0.945 ;
        RECT 772.200 0.125 1538.850 0.945 ;
        RECT 1543.350 0.125 1560.000 0.995 ;
      LAYER met4 ;
        RECT 1.565 52.450 1539.815 1638.440 ;
        RECT 1.565 49.990 368.395 52.450 ;
        RECT 380.985 49.990 1539.815 52.450 ;
        RECT 1.565 0.000 1539.815 49.990 ;
      LAYER met5 ;
        RECT 0.000 0.475 1541.380 1637.965 ;
  END
END pixel_4tile
END LIBRARY

